VERSION 5.7 ;
BUSBITCHARS "[]" ;
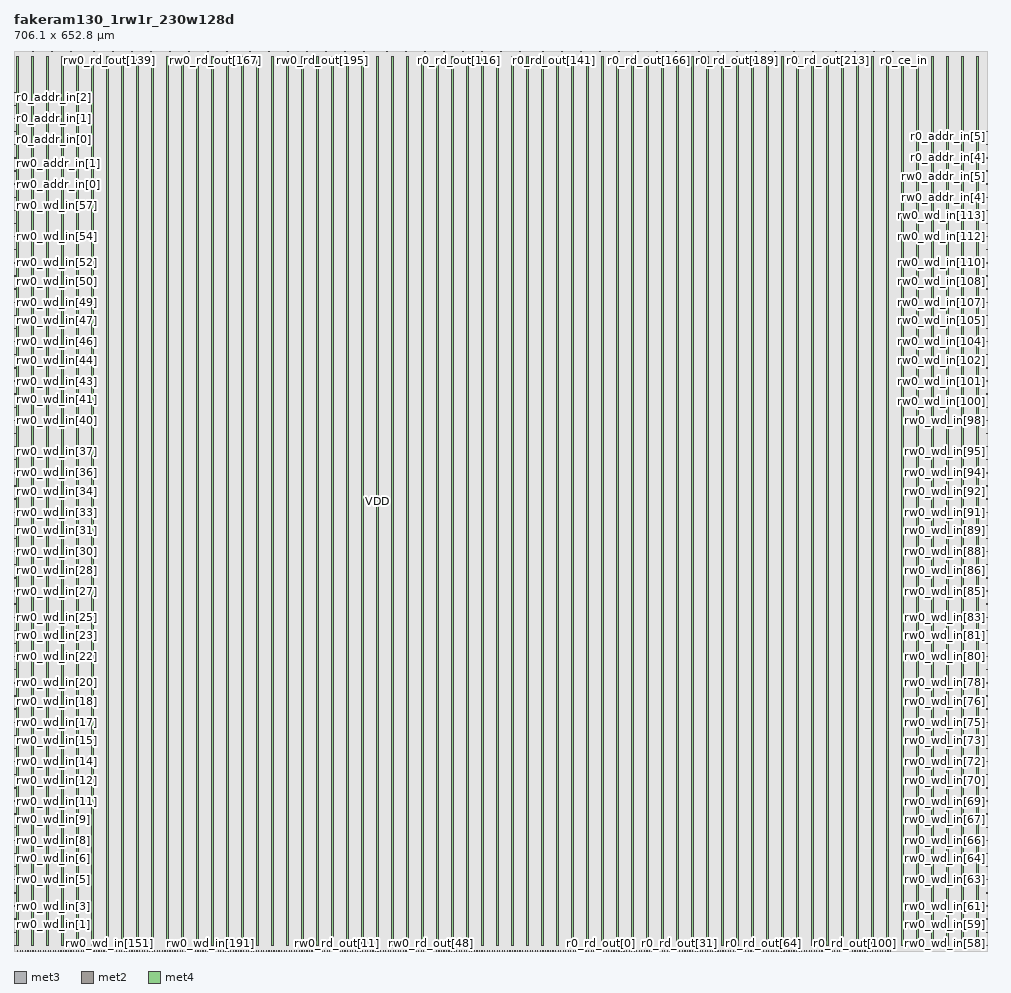
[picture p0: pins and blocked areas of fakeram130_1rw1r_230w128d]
MACRO fakeram130_1rw1r_230w128d
  FOREIGN fakeram130_1rw1r_230w128d 0 0 ;
  SYMMETRY X Y R90 ;
  SIZE 706.100 BY 652.800 ;
  CLASS BLOCK ;
  PIN rw0_wd_in[0]
    DIRECTION INPUT ;
    USE SIGNAL ;
    SHAPE ABUTMENT ;
    PORT
      LAYER met3 ;
      RECT 0.000 3.930 0.900 4.230 ;
    END
  END rw0_wd_in[0]
  PIN rw0_wd_in[1]
    DIRECTION INPUT ;
    USE SIGNAL ;
    SHAPE ABUTMENT ;
    PORT
      LAYER met3 ;
      RECT 0.000 13.450 0.900 13.750 ;
    END
  END rw0_wd_in[1]
  PIN rw0_wd_in[2]
    DIRECTION INPUT ;
    USE SIGNAL ;
    SHAPE ABUTMENT ;
    PORT
      LAYER met3 ;
      RECT 0.000 22.970 0.900 23.270 ;
    END
  END rw0_wd_in[2]
  PIN rw0_wd_in[3]
    DIRECTION INPUT ;
    USE SIGNAL ;
    SHAPE ABUTMENT ;
    PORT
      LAYER met3 ;
      RECT 0.000 32.490 0.900 32.790 ;
    END
  END rw0_wd_in[3]
  PIN rw0_wd_in[4]
    DIRECTION INPUT ;
    USE SIGNAL ;
    SHAPE ABUTMENT ;
    PORT
      LAYER met3 ;
      RECT 0.000 42.010 0.900 42.310 ;
    END
  END rw0_wd_in[4]
  PIN rw0_wd_in[5]
    DIRECTION INPUT ;
    USE SIGNAL ;
    SHAPE ABUTMENT ;
    PORT
      LAYER met3 ;
      RECT 0.000 51.530 0.900 51.830 ;
    END
  END rw0_wd_in[5]
  PIN rw0_wd_in[6]
    DIRECTION INPUT ;
    USE SIGNAL ;
    SHAPE ABUTMENT ;
    PORT
      LAYER met3 ;
      RECT 0.000 61.050 0.900 61.350 ;
    END
  END rw0_wd_in[6]
  PIN rw0_wd_in[7]
    DIRECTION INPUT ;
    USE SIGNAL ;
    SHAPE ABUTMENT ;
    PORT
      LAYER met3 ;
      RECT 0.000 70.570 0.900 70.870 ;
    END
  END rw0_wd_in[7]
  PIN rw0_wd_in[8]
    DIRECTION INPUT ;
    USE SIGNAL ;
    SHAPE ABUTMENT ;
    PORT
      LAYER met3 ;
      RECT 0.000 80.090 0.900 80.390 ;
    END
  END rw0_wd_in[8]
  PIN rw0_wd_in[9]
    DIRECTION INPUT ;
    USE SIGNAL ;
    SHAPE ABUTMENT ;
    PORT
      LAYER met3 ;
      RECT 0.000 89.610 0.900 89.910 ;
    END
  END rw0_wd_in[9]
  PIN rw0_wd_in[10]
    DIRECTION INPUT ;
    USE SIGNAL ;
    SHAPE ABUTMENT ;
    PORT
      LAYER met3 ;
      RECT 0.000 99.130 0.900 99.430 ;
    END
  END rw0_wd_in[10]
  PIN rw0_wd_in[11]
    DIRECTION INPUT ;
    USE SIGNAL ;
    SHAPE ABUTMENT ;
    PORT
      LAYER met3 ;
      RECT 0.000 108.650 0.900 108.950 ;
    END
  END rw0_wd_in[11]
  PIN rw0_wd_in[12]
    DIRECTION INPUT ;
    USE SIGNAL ;
    SHAPE ABUTMENT ;
    PORT
      LAYER met3 ;
      RECT 0.000 118.170 0.900 118.470 ;
    END
  END rw0_wd_in[12]
  PIN rw0_wd_in[13]
    DIRECTION INPUT ;
    USE SIGNAL ;
    SHAPE ABUTMENT ;
    PORT
      LAYER met3 ;
      RECT 0.000 127.690 0.900 127.990 ;
    END
  END rw0_wd_in[13]
  PIN rw0_wd_in[14]
    DIRECTION INPUT ;
    USE SIGNAL ;
    SHAPE ABUTMENT ;
    PORT
      LAYER met3 ;
      RECT 0.000 137.210 0.900 137.510 ;
    END
  END rw0_wd_in[14]
  PIN rw0_wd_in[15]
    DIRECTION INPUT ;
    USE SIGNAL ;
    SHAPE ABUTMENT ;
    PORT
      LAYER met3 ;
      RECT 0.000 146.730 0.900 147.030 ;
    END
  END rw0_wd_in[15]
  PIN rw0_wd_in[16]
    DIRECTION INPUT ;
    USE SIGNAL ;
    SHAPE ABUTMENT ;
    PORT
      LAYER met3 ;
      RECT 0.000 156.250 0.900 156.550 ;
    END
  END rw0_wd_in[16]
  PIN rw0_wd_in[17]
    DIRECTION INPUT ;
    USE SIGNAL ;
    SHAPE ABUTMENT ;
    PORT
      LAYER met3 ;
      RECT 0.000 165.770 0.900 166.070 ;
    END
  END rw0_wd_in[17]
  PIN rw0_wd_in[18]
    DIRECTION INPUT ;
    USE SIGNAL ;
    SHAPE ABUTMENT ;
    PORT
      LAYER met3 ;
      RECT 0.000 175.290 0.900 175.590 ;
    END
  END rw0_wd_in[18]
  PIN rw0_wd_in[19]
    DIRECTION INPUT ;
    USE SIGNAL ;
    SHAPE ABUTMENT ;
    PORT
      LAYER met3 ;
      RECT 0.000 184.810 0.900 185.110 ;
    END
  END rw0_wd_in[19]
  PIN rw0_wd_in[20]
    DIRECTION INPUT ;
    USE SIGNAL ;
    SHAPE ABUTMENT ;
    PORT
      LAYER met3 ;
      RECT 0.000 194.330 0.900 194.630 ;
    END
  END rw0_wd_in[20]
  PIN rw0_wd_in[21]
    DIRECTION INPUT ;
    USE SIGNAL ;
    SHAPE ABUTMENT ;
    PORT
      LAYER met3 ;
      RECT 0.000 203.850 0.900 204.150 ;
    END
  END rw0_wd_in[21]
  PIN rw0_wd_in[22]
    DIRECTION INPUT ;
    USE SIGNAL ;
    SHAPE ABUTMENT ;
    PORT
      LAYER met3 ;
      RECT 0.000 213.370 0.900 213.670 ;
    END
  END rw0_wd_in[22]
  PIN rw0_wd_in[23]
    DIRECTION INPUT ;
    USE SIGNAL ;
    SHAPE ABUTMENT ;
    PORT
      LAYER met3 ;
      RECT 0.000 222.890 0.900 223.190 ;
    END
  END rw0_wd_in[23]
  PIN rw0_wd_in[24]
    DIRECTION INPUT ;
    USE SIGNAL ;
    SHAPE ABUTMENT ;
    PORT
      LAYER met3 ;
      RECT 0.000 232.410 0.900 232.710 ;
    END
  END rw0_wd_in[24]
  PIN rw0_wd_in[25]
    DIRECTION INPUT ;
    USE SIGNAL ;
    SHAPE ABUTMENT ;
    PORT
      LAYER met3 ;
      RECT 0.000 241.930 0.900 242.230 ;
    END
  END rw0_wd_in[25]
  PIN rw0_wd_in[26]
    DIRECTION INPUT ;
    USE SIGNAL ;
    SHAPE ABUTMENT ;
    PORT
      LAYER met3 ;
      RECT 0.000 251.450 0.900 251.750 ;
    END
  END rw0_wd_in[26]
  PIN rw0_wd_in[27]
    DIRECTION INPUT ;
    USE SIGNAL ;
    SHAPE ABUTMENT ;
    PORT
      LAYER met3 ;
      RECT 0.000 260.970 0.900 261.270 ;
    END
  END rw0_wd_in[27]
  PIN rw0_wd_in[28]
    DIRECTION INPUT ;
    USE SIGNAL ;
    SHAPE ABUTMENT ;
    PORT
      LAYER met3 ;
      RECT 0.000 270.490 0.900 270.790 ;
    END
  END rw0_wd_in[28]
  PIN rw0_wd_in[29]
    DIRECTION INPUT ;
    USE SIGNAL ;
    SHAPE ABUTMENT ;
    PORT
      LAYER met3 ;
      RECT 0.000 280.010 0.900 280.310 ;
    END
  END rw0_wd_in[29]
  PIN rw0_wd_in[30]
    DIRECTION INPUT ;
    USE SIGNAL ;
    SHAPE ABUTMENT ;
    PORT
      LAYER met3 ;
      RECT 0.000 289.530 0.900 289.830 ;
    END
  END rw0_wd_in[30]
  PIN rw0_wd_in[31]
    DIRECTION INPUT ;
    USE SIGNAL ;
    SHAPE ABUTMENT ;
    PORT
      LAYER met3 ;
      RECT 0.000 299.050 0.900 299.350 ;
    END
  END rw0_wd_in[31]
  PIN rw0_wd_in[32]
    DIRECTION INPUT ;
    USE SIGNAL ;
    SHAPE ABUTMENT ;
    PORT
      LAYER met3 ;
      RECT 0.000 308.570 0.900 308.870 ;
    END
  END rw0_wd_in[32]
  PIN rw0_wd_in[33]
    DIRECTION INPUT ;
    USE SIGNAL ;
    SHAPE ABUTMENT ;
    PORT
      LAYER met3 ;
      RECT 0.000 318.090 0.900 318.390 ;
    END
  END rw0_wd_in[33]
  PIN rw0_wd_in[34]
    DIRECTION INPUT ;
    USE SIGNAL ;
    SHAPE ABUTMENT ;
    PORT
      LAYER met3 ;
      RECT 0.000 327.610 0.900 327.910 ;
    END
  END rw0_wd_in[34]
  PIN rw0_wd_in[35]
    DIRECTION INPUT ;
    USE SIGNAL ;
    SHAPE ABUTMENT ;
    PORT
      LAYER met3 ;
      RECT 0.000 337.130 0.900 337.430 ;
    END
  END rw0_wd_in[35]
  PIN rw0_wd_in[36]
    DIRECTION INPUT ;
    USE SIGNAL ;
    SHAPE ABUTMENT ;
    PORT
      LAYER met3 ;
      RECT 0.000 346.650 0.900 346.950 ;
    END
  END rw0_wd_in[36]
  PIN rw0_wd_in[37]
    DIRECTION INPUT ;
    USE SIGNAL ;
    SHAPE ABUTMENT ;
    PORT
      LAYER met3 ;
      RECT 0.000 356.170 0.900 356.470 ;
    END
  END rw0_wd_in[37]
  PIN rw0_wd_in[38]
    DIRECTION INPUT ;
    USE SIGNAL ;
    SHAPE ABUTMENT ;
    PORT
      LAYER met3 ;
      RECT 0.000 365.690 0.900 365.990 ;
    END
  END rw0_wd_in[38]
  PIN rw0_wd_in[39]
    DIRECTION INPUT ;
    USE SIGNAL ;
    SHAPE ABUTMENT ;
    PORT
      LAYER met3 ;
      RECT 0.000 375.210 0.900 375.510 ;
    END
  END rw0_wd_in[39]
  PIN rw0_wd_in[40]
    DIRECTION INPUT ;
    USE SIGNAL ;
    SHAPE ABUTMENT ;
    PORT
      LAYER met3 ;
      RECT 0.000 384.730 0.900 385.030 ;
    END
  END rw0_wd_in[40]
  PIN rw0_wd_in[41]
    DIRECTION INPUT ;
    USE SIGNAL ;
    SHAPE ABUTMENT ;
    PORT
      LAYER met3 ;
      RECT 0.000 394.250 0.900 394.550 ;
    END
  END rw0_wd_in[41]
  PIN rw0_wd_in[42]
    DIRECTION INPUT ;
    USE SIGNAL ;
    SHAPE ABUTMENT ;
    PORT
      LAYER met3 ;
      RECT 0.000 403.770 0.900 404.070 ;
    END
  END rw0_wd_in[42]
  PIN rw0_wd_in[43]
    DIRECTION INPUT ;
    USE SIGNAL ;
    SHAPE ABUTMENT ;
    PORT
      LAYER met3 ;
      RECT 0.000 413.290 0.900 413.590 ;
    END
  END rw0_wd_in[43]
  PIN rw0_wd_in[44]
    DIRECTION INPUT ;
    USE SIGNAL ;
    SHAPE ABUTMENT ;
    PORT
      LAYER met3 ;
      RECT 0.000 422.810 0.900 423.110 ;
    END
  END rw0_wd_in[44]
  PIN rw0_wd_in[45]
    DIRECTION INPUT ;
    USE SIGNAL ;
    SHAPE ABUTMENT ;
    PORT
      LAYER met3 ;
      RECT 0.000 432.330 0.900 432.630 ;
    END
  END rw0_wd_in[45]
  PIN rw0_wd_in[46]
    DIRECTION INPUT ;
    USE SIGNAL ;
    SHAPE ABUTMENT ;
    PORT
      LAYER met3 ;
      RECT 0.000 441.850 0.900 442.150 ;
    END
  END rw0_wd_in[46]
  PIN rw0_wd_in[47]
    DIRECTION INPUT ;
    USE SIGNAL ;
    SHAPE ABUTMENT ;
    PORT
      LAYER met3 ;
      RECT 0.000 451.370 0.900 451.670 ;
    END
  END rw0_wd_in[47]
  PIN rw0_wd_in[48]
    DIRECTION INPUT ;
    USE SIGNAL ;
    SHAPE ABUTMENT ;
    PORT
      LAYER met3 ;
      RECT 0.000 460.890 0.900 461.190 ;
    END
  END rw0_wd_in[48]
  PIN rw0_wd_in[49]
    DIRECTION INPUT ;
    USE SIGNAL ;
    SHAPE ABUTMENT ;
    PORT
      LAYER met3 ;
      RECT 0.000 470.410 0.900 470.710 ;
    END
  END rw0_wd_in[49]
  PIN rw0_wd_in[50]
    DIRECTION INPUT ;
    USE SIGNAL ;
    SHAPE ABUTMENT ;
    PORT
      LAYER met3 ;
      RECT 0.000 479.930 0.900 480.230 ;
    END
  END rw0_wd_in[50]
  PIN rw0_wd_in[51]
    DIRECTION INPUT ;
    USE SIGNAL ;
    SHAPE ABUTMENT ;
    PORT
      LAYER met3 ;
      RECT 0.000 489.450 0.900 489.750 ;
    END
  END rw0_wd_in[51]
  PIN rw0_wd_in[52]
    DIRECTION INPUT ;
    USE SIGNAL ;
    SHAPE ABUTMENT ;
    PORT
      LAYER met3 ;
      RECT 0.000 498.970 0.900 499.270 ;
    END
  END rw0_wd_in[52]
  PIN rw0_wd_in[53]
    DIRECTION INPUT ;
    USE SIGNAL ;
    SHAPE ABUTMENT ;
    PORT
      LAYER met3 ;
      RECT 0.000 508.490 0.900 508.790 ;
    END
  END rw0_wd_in[53]
  PIN rw0_wd_in[54]
    DIRECTION INPUT ;
    USE SIGNAL ;
    SHAPE ABUTMENT ;
    PORT
      LAYER met3 ;
      RECT 0.000 518.010 0.900 518.310 ;
    END
  END rw0_wd_in[54]
  PIN rw0_wd_in[55]
    DIRECTION INPUT ;
    USE SIGNAL ;
    SHAPE ABUTMENT ;
    PORT
      LAYER met3 ;
      RECT 0.000 527.530 0.900 527.830 ;
    END
  END rw0_wd_in[55]
  PIN rw0_wd_in[56]
    DIRECTION INPUT ;
    USE SIGNAL ;
    SHAPE ABUTMENT ;
    PORT
      LAYER met3 ;
      RECT 0.000 537.050 0.900 537.350 ;
    END
  END rw0_wd_in[56]
  PIN rw0_wd_in[57]
    DIRECTION INPUT ;
    USE SIGNAL ;
    SHAPE ABUTMENT ;
    PORT
      LAYER met3 ;
      RECT 0.000 546.570 0.900 546.870 ;
    END
  END rw0_wd_in[57]
  PIN rw0_wd_in[58]
    DIRECTION INPUT ;
    USE SIGNAL ;
    SHAPE ABUTMENT ;
    PORT
      LAYER met3 ;
      RECT 705.200 3.930 706.100 4.230 ;
    END
  END rw0_wd_in[58]
  PIN rw0_wd_in[59]
    DIRECTION INPUT ;
    USE SIGNAL ;
    SHAPE ABUTMENT ;
    PORT
      LAYER met3 ;
      RECT 705.200 13.450 706.100 13.750 ;
    END
  END rw0_wd_in[59]
  PIN rw0_wd_in[60]
    DIRECTION INPUT ;
    USE SIGNAL ;
    SHAPE ABUTMENT ;
    PORT
      LAYER met3 ;
      RECT 705.200 22.970 706.100 23.270 ;
    END
  END rw0_wd_in[60]
  PIN rw0_wd_in[61]
    DIRECTION INPUT ;
    USE SIGNAL ;
    SHAPE ABUTMENT ;
    PORT
      LAYER met3 ;
      RECT 705.200 32.490 706.100 32.790 ;
    END
  END rw0_wd_in[61]
  PIN rw0_wd_in[62]
    DIRECTION INPUT ;
    USE SIGNAL ;
    SHAPE ABUTMENT ;
    PORT
      LAYER met3 ;
      RECT 705.200 42.010 706.100 42.310 ;
    END
  END rw0_wd_in[62]
  PIN rw0_wd_in[63]
    DIRECTION INPUT ;
    USE SIGNAL ;
    SHAPE ABUTMENT ;
    PORT
      LAYER met3 ;
      RECT 705.200 51.530 706.100 51.830 ;
    END
  END rw0_wd_in[63]
  PIN rw0_wd_in[64]
    DIRECTION INPUT ;
    USE SIGNAL ;
    SHAPE ABUTMENT ;
    PORT
      LAYER met3 ;
      RECT 705.200 61.050 706.100 61.350 ;
    END
  END rw0_wd_in[64]
  PIN rw0_wd_in[65]
    DIRECTION INPUT ;
    USE SIGNAL ;
    SHAPE ABUTMENT ;
    PORT
      LAYER met3 ;
      RECT 705.200 70.570 706.100 70.870 ;
    END
  END rw0_wd_in[65]
  PIN rw0_wd_in[66]
    DIRECTION INPUT ;
    USE SIGNAL ;
    SHAPE ABUTMENT ;
    PORT
      LAYER met3 ;
      RECT 705.200 80.090 706.100 80.390 ;
    END
  END rw0_wd_in[66]
  PIN rw0_wd_in[67]
    DIRECTION INPUT ;
    USE SIGNAL ;
    SHAPE ABUTMENT ;
    PORT
      LAYER met3 ;
      RECT 705.200 89.610 706.100 89.910 ;
    END
  END rw0_wd_in[67]
  PIN rw0_wd_in[68]
    DIRECTION INPUT ;
    USE SIGNAL ;
    SHAPE ABUTMENT ;
    PORT
      LAYER met3 ;
      RECT 705.200 99.130 706.100 99.430 ;
    END
  END rw0_wd_in[68]
  PIN rw0_wd_in[69]
    DIRECTION INPUT ;
    USE SIGNAL ;
    SHAPE ABUTMENT ;
    PORT
      LAYER met3 ;
      RECT 705.200 108.650 706.100 108.950 ;
    END
  END rw0_wd_in[69]
  PIN rw0_wd_in[70]
    DIRECTION INPUT ;
    USE SIGNAL ;
    SHAPE ABUTMENT ;
    PORT
      LAYER met3 ;
      RECT 705.200 118.170 706.100 118.470 ;
    END
  END rw0_wd_in[70]
  PIN rw0_wd_in[71]
    DIRECTION INPUT ;
    USE SIGNAL ;
    SHAPE ABUTMENT ;
    PORT
      LAYER met3 ;
      RECT 705.200 127.690 706.100 127.990 ;
    END
  END rw0_wd_in[71]
  PIN rw0_wd_in[72]
    DIRECTION INPUT ;
    USE SIGNAL ;
    SHAPE ABUTMENT ;
    PORT
      LAYER met3 ;
      RECT 705.200 137.210 706.100 137.510 ;
    END
  END rw0_wd_in[72]
  PIN rw0_wd_in[73]
    DIRECTION INPUT ;
    USE SIGNAL ;
    SHAPE ABUTMENT ;
    PORT
      LAYER met3 ;
      RECT 705.200 146.730 706.100 147.030 ;
    END
  END rw0_wd_in[73]
  PIN rw0_wd_in[74]
    DIRECTION INPUT ;
    USE SIGNAL ;
    SHAPE ABUTMENT ;
    PORT
      LAYER met3 ;
      RECT 705.200 156.250 706.100 156.550 ;
    END
  END rw0_wd_in[74]
  PIN rw0_wd_in[75]
    DIRECTION INPUT ;
    USE SIGNAL ;
    SHAPE ABUTMENT ;
    PORT
      LAYER met3 ;
      RECT 705.200 165.770 706.100 166.070 ;
    END
  END rw0_wd_in[75]
  PIN rw0_wd_in[76]
    DIRECTION INPUT ;
    USE SIGNAL ;
    SHAPE ABUTMENT ;
    PORT
      LAYER met3 ;
      RECT 705.200 175.290 706.100 175.590 ;
    END
  END rw0_wd_in[76]
  PIN rw0_wd_in[77]
    DIRECTION INPUT ;
    USE SIGNAL ;
    SHAPE ABUTMENT ;
    PORT
      LAYER met3 ;
      RECT 705.200 184.810 706.100 185.110 ;
    END
  END rw0_wd_in[77]
  PIN rw0_wd_in[78]
    DIRECTION INPUT ;
    USE SIGNAL ;
    SHAPE ABUTMENT ;
    PORT
      LAYER met3 ;
      RECT 705.200 194.330 706.100 194.630 ;
    END
  END rw0_wd_in[78]
  PIN rw0_wd_in[79]
    DIRECTION INPUT ;
    USE SIGNAL ;
    SHAPE ABUTMENT ;
    PORT
      LAYER met3 ;
      RECT 705.200 203.850 706.100 204.150 ;
    END
  END rw0_wd_in[79]
  PIN rw0_wd_in[80]
    DIRECTION INPUT ;
    USE SIGNAL ;
    SHAPE ABUTMENT ;
    PORT
      LAYER met3 ;
      RECT 705.200 213.370 706.100 213.670 ;
    END
  END rw0_wd_in[80]
  PIN rw0_wd_in[81]
    DIRECTION INPUT ;
    USE SIGNAL ;
    SHAPE ABUTMENT ;
    PORT
      LAYER met3 ;
      RECT 705.200 222.890 706.100 223.190 ;
    END
  END rw0_wd_in[81]
  PIN rw0_wd_in[82]
    DIRECTION INPUT ;
    USE SIGNAL ;
    SHAPE ABUTMENT ;
    PORT
      LAYER met3 ;
      RECT 705.200 232.410 706.100 232.710 ;
    END
  END rw0_wd_in[82]
  PIN rw0_wd_in[83]
    DIRECTION INPUT ;
    USE SIGNAL ;
    SHAPE ABUTMENT ;
    PORT
      LAYER met3 ;
      RECT 705.200 241.930 706.100 242.230 ;
    END
  END rw0_wd_in[83]
  PIN rw0_wd_in[84]
    DIRECTION INPUT ;
    USE SIGNAL ;
    SHAPE ABUTMENT ;
    PORT
      LAYER met3 ;
      RECT 705.200 251.450 706.100 251.750 ;
    END
  END rw0_wd_in[84]
  PIN rw0_wd_in[85]
    DIRECTION INPUT ;
    USE SIGNAL ;
    SHAPE ABUTMENT ;
    PORT
      LAYER met3 ;
      RECT 705.200 260.970 706.100 261.270 ;
    END
  END rw0_wd_in[85]
  PIN rw0_wd_in[86]
    DIRECTION INPUT ;
    USE SIGNAL ;
    SHAPE ABUTMENT ;
    PORT
      LAYER met3 ;
      RECT 705.200 270.490 706.100 270.790 ;
    END
  END rw0_wd_in[86]
  PIN rw0_wd_in[87]
    DIRECTION INPUT ;
    USE SIGNAL ;
    SHAPE ABUTMENT ;
    PORT
      LAYER met3 ;
      RECT 705.200 280.010 706.100 280.310 ;
    END
  END rw0_wd_in[87]
  PIN rw0_wd_in[88]
    DIRECTION INPUT ;
    USE SIGNAL ;
    SHAPE ABUTMENT ;
    PORT
      LAYER met3 ;
      RECT 705.200 289.530 706.100 289.830 ;
    END
  END rw0_wd_in[88]
  PIN rw0_wd_in[89]
    DIRECTION INPUT ;
    USE SIGNAL ;
    SHAPE ABUTMENT ;
    PORT
      LAYER met3 ;
      RECT 705.200 299.050 706.100 299.350 ;
    END
  END rw0_wd_in[89]
  PIN rw0_wd_in[90]
    DIRECTION INPUT ;
    USE SIGNAL ;
    SHAPE ABUTMENT ;
    PORT
      LAYER met3 ;
      RECT 705.200 308.570 706.100 308.870 ;
    END
  END rw0_wd_in[90]
  PIN rw0_wd_in[91]
    DIRECTION INPUT ;
    USE SIGNAL ;
    SHAPE ABUTMENT ;
    PORT
      LAYER met3 ;
      RECT 705.200 318.090 706.100 318.390 ;
    END
  END rw0_wd_in[91]
  PIN rw0_wd_in[92]
    DIRECTION INPUT ;
    USE SIGNAL ;
    SHAPE ABUTMENT ;
    PORT
      LAYER met3 ;
      RECT 705.200 327.610 706.100 327.910 ;
    END
  END rw0_wd_in[92]
  PIN rw0_wd_in[93]
    DIRECTION INPUT ;
    USE SIGNAL ;
    SHAPE ABUTMENT ;
    PORT
      LAYER met3 ;
      RECT 705.200 337.130 706.100 337.430 ;
    END
  END rw0_wd_in[93]
  PIN rw0_wd_in[94]
    DIRECTION INPUT ;
    USE SIGNAL ;
    SHAPE ABUTMENT ;
    PORT
      LAYER met3 ;
      RECT 705.200 346.650 706.100 346.950 ;
    END
  END rw0_wd_in[94]
  PIN rw0_wd_in[95]
    DIRECTION INPUT ;
    USE SIGNAL ;
    SHAPE ABUTMENT ;
    PORT
      LAYER met3 ;
      RECT 705.200 356.170 706.100 356.470 ;
    END
  END rw0_wd_in[95]
  PIN rw0_wd_in[96]
    DIRECTION INPUT ;
    USE SIGNAL ;
    SHAPE ABUTMENT ;
    PORT
      LAYER met3 ;
      RECT 705.200 365.690 706.100 365.990 ;
    END
  END rw0_wd_in[96]
  PIN rw0_wd_in[97]
    DIRECTION INPUT ;
    USE SIGNAL ;
    SHAPE ABUTMENT ;
    PORT
      LAYER met3 ;
      RECT 705.200 375.210 706.100 375.510 ;
    END
  END rw0_wd_in[97]
  PIN rw0_wd_in[98]
    DIRECTION INPUT ;
    USE SIGNAL ;
    SHAPE ABUTMENT ;
    PORT
      LAYER met3 ;
      RECT 705.200 384.730 706.100 385.030 ;
    END
  END rw0_wd_in[98]
  PIN rw0_wd_in[99]
    DIRECTION INPUT ;
    USE SIGNAL ;
    SHAPE ABUTMENT ;
    PORT
      LAYER met3 ;
      RECT 705.200 394.250 706.100 394.550 ;
    END
  END rw0_wd_in[99]
  PIN rw0_wd_in[100]
    DIRECTION INPUT ;
    USE SIGNAL ;
    SHAPE ABUTMENT ;
    PORT
      LAYER met3 ;
      RECT 705.200 403.770 706.100 404.070 ;
    END
  END rw0_wd_in[100]
  PIN rw0_wd_in[101]
    DIRECTION INPUT ;
    USE SIGNAL ;
    SHAPE ABUTMENT ;
    PORT
      LAYER met3 ;
      RECT 705.200 413.290 706.100 413.590 ;
    END
  END rw0_wd_in[101]
  PIN rw0_wd_in[102]
    DIRECTION INPUT ;
    USE SIGNAL ;
    SHAPE ABUTMENT ;
    PORT
      LAYER met3 ;
      RECT 705.200 422.810 706.100 423.110 ;
    END
  END rw0_wd_in[102]
  PIN rw0_wd_in[103]
    DIRECTION INPUT ;
    USE SIGNAL ;
    SHAPE ABUTMENT ;
    PORT
      LAYER met3 ;
      RECT 705.200 432.330 706.100 432.630 ;
    END
  END rw0_wd_in[103]
  PIN rw0_wd_in[104]
    DIRECTION INPUT ;
    USE SIGNAL ;
    SHAPE ABUTMENT ;
    PORT
      LAYER met3 ;
      RECT 705.200 441.850 706.100 442.150 ;
    END
  END rw0_wd_in[104]
  PIN rw0_wd_in[105]
    DIRECTION INPUT ;
    USE SIGNAL ;
    SHAPE ABUTMENT ;
    PORT
      LAYER met3 ;
      RECT 705.200 451.370 706.100 451.670 ;
    END
  END rw0_wd_in[105]
  PIN rw0_wd_in[106]
    DIRECTION INPUT ;
    USE SIGNAL ;
    SHAPE ABUTMENT ;
    PORT
      LAYER met3 ;
      RECT 705.200 460.890 706.100 461.190 ;
    END
  END rw0_wd_in[106]
  PIN rw0_wd_in[107]
    DIRECTION INPUT ;
    USE SIGNAL ;
    SHAPE ABUTMENT ;
    PORT
      LAYER met3 ;
      RECT 705.200 470.410 706.100 470.710 ;
    END
  END rw0_wd_in[107]
  PIN rw0_wd_in[108]
    DIRECTION INPUT ;
    USE SIGNAL ;
    SHAPE ABUTMENT ;
    PORT
      LAYER met3 ;
      RECT 705.200 479.930 706.100 480.230 ;
    END
  END rw0_wd_in[108]
  PIN rw0_wd_in[109]
    DIRECTION INPUT ;
    USE SIGNAL ;
    SHAPE ABUTMENT ;
    PORT
      LAYER met3 ;
      RECT 705.200 489.450 706.100 489.750 ;
    END
  END rw0_wd_in[109]
  PIN rw0_wd_in[110]
    DIRECTION INPUT ;
    USE SIGNAL ;
    SHAPE ABUTMENT ;
    PORT
      LAYER met3 ;
      RECT 705.200 498.970 706.100 499.270 ;
    END
  END rw0_wd_in[110]
  PIN rw0_wd_in[111]
    DIRECTION INPUT ;
    USE SIGNAL ;
    SHAPE ABUTMENT ;
    PORT
      LAYER met3 ;
      RECT 705.200 508.490 706.100 508.790 ;
    END
  END rw0_wd_in[111]
  PIN rw0_wd_in[112]
    DIRECTION INPUT ;
    USE SIGNAL ;
    SHAPE ABUTMENT ;
    PORT
      LAYER met3 ;
      RECT 705.200 518.010 706.100 518.310 ;
    END
  END rw0_wd_in[112]
  PIN rw0_wd_in[113]
    DIRECTION INPUT ;
    USE SIGNAL ;
    SHAPE ABUTMENT ;
    PORT
      LAYER met3 ;
      RECT 705.200 527.530 706.100 527.830 ;
    END
  END rw0_wd_in[113]
  PIN rw0_wd_in[114]
    DIRECTION INPUT ;
    USE SIGNAL ;
    SHAPE ABUTMENT ;
    PORT
      LAYER met3 ;
      RECT 705.200 537.050 706.100 537.350 ;
    END
  END rw0_wd_in[114]
  PIN rw0_wd_in[115]
    DIRECTION OUTPUT ;
    USE SIGNAL ;
    SHAPE ABUTMENT ;
    PORT
      LAYER met2 ;
      RECT 2.690 0.000 2.830 0.420 ;
    END
  END rw0_wd_in[115]
  PIN rw0_wd_in[116]
    DIRECTION OUTPUT ;
    USE SIGNAL ;
    SHAPE ABUTMENT ;
    PORT
      LAYER met2 ;
      RECT 4.530 0.000 4.670 0.420 ;
    END
  END rw0_wd_in[116]
  PIN rw0_wd_in[117]
    DIRECTION OUTPUT ;
    USE SIGNAL ;
    SHAPE ABUTMENT ;
    PORT
      LAYER met2 ;
      RECT 6.370 0.000 6.510 0.420 ;
    END
  END rw0_wd_in[117]
  PIN rw0_wd_in[118]
    DIRECTION OUTPUT ;
    USE SIGNAL ;
    SHAPE ABUTMENT ;
    PORT
      LAYER met2 ;
      RECT 8.210 0.000 8.350 0.420 ;
    END
  END rw0_wd_in[118]
  PIN rw0_wd_in[119]
    DIRECTION OUTPUT ;
    USE SIGNAL ;
    SHAPE ABUTMENT ;
    PORT
      LAYER met2 ;
      RECT 10.050 0.000 10.190 0.420 ;
    END
  END rw0_wd_in[119]
  PIN rw0_wd_in[120]
    DIRECTION OUTPUT ;
    USE SIGNAL ;
    SHAPE ABUTMENT ;
    PORT
      LAYER met2 ;
      RECT 11.890 0.000 12.030 0.420 ;
    END
  END rw0_wd_in[120]
  PIN rw0_wd_in[121]
    DIRECTION OUTPUT ;
    USE SIGNAL ;
    SHAPE ABUTMENT ;
    PORT
      LAYER met2 ;
      RECT 13.730 0.000 13.870 0.420 ;
    END
  END rw0_wd_in[121]
  PIN rw0_wd_in[122]
    DIRECTION OUTPUT ;
    USE SIGNAL ;
    SHAPE ABUTMENT ;
    PORT
      LAYER met2 ;
      RECT 15.570 0.000 15.710 0.420 ;
    END
  END rw0_wd_in[122]
  PIN rw0_wd_in[123]
    DIRECTION OUTPUT ;
    USE SIGNAL ;
    SHAPE ABUTMENT ;
    PORT
      LAYER met2 ;
      RECT 17.410 0.000 17.550 0.420 ;
    END
  END rw0_wd_in[123]
  PIN rw0_wd_in[124]
    DIRECTION OUTPUT ;
    USE SIGNAL ;
    SHAPE ABUTMENT ;
    PORT
      LAYER met2 ;
      RECT 19.250 0.000 19.390 0.420 ;
    END
  END rw0_wd_in[124]
  PIN rw0_wd_in[125]
    DIRECTION OUTPUT ;
    USE SIGNAL ;
    SHAPE ABUTMENT ;
    PORT
      LAYER met2 ;
      RECT 21.090 0.000 21.230 0.420 ;
    END
  END rw0_wd_in[125]
  PIN rw0_wd_in[126]
    DIRECTION OUTPUT ;
    USE SIGNAL ;
    SHAPE ABUTMENT ;
    PORT
      LAYER met2 ;
      RECT 22.930 0.000 23.070 0.420 ;
    END
  END rw0_wd_in[126]
  PIN rw0_wd_in[127]
    DIRECTION OUTPUT ;
    USE SIGNAL ;
    SHAPE ABUTMENT ;
    PORT
      LAYER met2 ;
      RECT 24.770 0.000 24.910 0.420 ;
    END
  END rw0_wd_in[127]
  PIN rw0_wd_in[128]
    DIRECTION OUTPUT ;
    USE SIGNAL ;
    SHAPE ABUTMENT ;
    PORT
      LAYER met2 ;
      RECT 26.610 0.000 26.750 0.420 ;
    END
  END rw0_wd_in[128]
  PIN rw0_wd_in[129]
    DIRECTION OUTPUT ;
    USE SIGNAL ;
    SHAPE ABUTMENT ;
    PORT
      LAYER met2 ;
      RECT 28.450 0.000 28.590 0.420 ;
    END
  END rw0_wd_in[129]
  PIN rw0_wd_in[130]
    DIRECTION OUTPUT ;
    USE SIGNAL ;
    SHAPE ABUTMENT ;
    PORT
      LAYER met2 ;
      RECT 30.290 0.000 30.430 0.420 ;
    END
  END rw0_wd_in[130]
  PIN rw0_wd_in[131]
    DIRECTION OUTPUT ;
    USE SIGNAL ;
    SHAPE ABUTMENT ;
    PORT
      LAYER met2 ;
      RECT 32.130 0.000 32.270 0.420 ;
    END
  END rw0_wd_in[131]
  PIN rw0_wd_in[132]
    DIRECTION OUTPUT ;
    USE SIGNAL ;
    SHAPE ABUTMENT ;
    PORT
      LAYER met2 ;
      RECT 33.970 0.000 34.110 0.420 ;
    END
  END rw0_wd_in[132]
  PIN rw0_wd_in[133]
    DIRECTION OUTPUT ;
    USE SIGNAL ;
    SHAPE ABUTMENT ;
    PORT
      LAYER met2 ;
      RECT 35.810 0.000 35.950 0.420 ;
    END
  END rw0_wd_in[133]
  PIN rw0_wd_in[134]
    DIRECTION OUTPUT ;
    USE SIGNAL ;
    SHAPE ABUTMENT ;
    PORT
      LAYER met2 ;
      RECT 37.650 0.000 37.790 0.420 ;
    END
  END rw0_wd_in[134]
  PIN rw0_wd_in[135]
    DIRECTION OUTPUT ;
    USE SIGNAL ;
    SHAPE ABUTMENT ;
    PORT
      LAYER met2 ;
      RECT 39.490 0.000 39.630 0.420 ;
    END
  END rw0_wd_in[135]
  PIN rw0_wd_in[136]
    DIRECTION OUTPUT ;
    USE SIGNAL ;
    SHAPE ABUTMENT ;
    PORT
      LAYER met2 ;
      RECT 41.330 0.000 41.470 0.420 ;
    END
  END rw0_wd_in[136]
  PIN rw0_wd_in[137]
    DIRECTION OUTPUT ;
    USE SIGNAL ;
    SHAPE ABUTMENT ;
    PORT
      LAYER met2 ;
      RECT 43.170 0.000 43.310 0.420 ;
    END
  END rw0_wd_in[137]
  PIN rw0_wd_in[138]
    DIRECTION OUTPUT ;
    USE SIGNAL ;
    SHAPE ABUTMENT ;
    PORT
      LAYER met2 ;
      RECT 45.010 0.000 45.150 0.420 ;
    END
  END rw0_wd_in[138]
  PIN rw0_wd_in[139]
    DIRECTION OUTPUT ;
    USE SIGNAL ;
    SHAPE ABUTMENT ;
    PORT
      LAYER met2 ;
      RECT 46.850 0.000 46.990 0.420 ;
    END
  END rw0_wd_in[139]
  PIN rw0_wd_in[140]
    DIRECTION OUTPUT ;
    USE SIGNAL ;
    SHAPE ABUTMENT ;
    PORT
      LAYER met2 ;
      RECT 48.690 0.000 48.830 0.420 ;
    END
  END rw0_wd_in[140]
  PIN rw0_wd_in[141]
    DIRECTION OUTPUT ;
    USE SIGNAL ;
    SHAPE ABUTMENT ;
    PORT
      LAYER met2 ;
      RECT 50.530 0.000 50.670 0.420 ;
    END
  END rw0_wd_in[141]
  PIN rw0_wd_in[142]
    DIRECTION OUTPUT ;
    USE SIGNAL ;
    SHAPE ABUTMENT ;
    PORT
      LAYER met2 ;
      RECT 52.370 0.000 52.510 0.420 ;
    END
  END rw0_wd_in[142]
  PIN rw0_wd_in[143]
    DIRECTION OUTPUT ;
    USE SIGNAL ;
    SHAPE ABUTMENT ;
    PORT
      LAYER met2 ;
      RECT 54.210 0.000 54.350 0.420 ;
    END
  END rw0_wd_in[143]
  PIN rw0_wd_in[144]
    DIRECTION OUTPUT ;
    USE SIGNAL ;
    SHAPE ABUTMENT ;
    PORT
      LAYER met2 ;
      RECT 56.050 0.000 56.190 0.420 ;
    END
  END rw0_wd_in[144]
  PIN rw0_wd_in[145]
    DIRECTION OUTPUT ;
    USE SIGNAL ;
    SHAPE ABUTMENT ;
    PORT
      LAYER met2 ;
      RECT 57.890 0.000 58.030 0.420 ;
    END
  END rw0_wd_in[145]
  PIN rw0_wd_in[146]
    DIRECTION OUTPUT ;
    USE SIGNAL ;
    SHAPE ABUTMENT ;
    PORT
      LAYER met2 ;
      RECT 59.730 0.000 59.870 0.420 ;
    END
  END rw0_wd_in[146]
  PIN rw0_wd_in[147]
    DIRECTION OUTPUT ;
    USE SIGNAL ;
    SHAPE ABUTMENT ;
    PORT
      LAYER met2 ;
      RECT 61.570 0.000 61.710 0.420 ;
    END
  END rw0_wd_in[147]
  PIN rw0_wd_in[148]
    DIRECTION OUTPUT ;
    USE SIGNAL ;
    SHAPE ABUTMENT ;
    PORT
      LAYER met2 ;
      RECT 63.410 0.000 63.550 0.420 ;
    END
  END rw0_wd_in[148]
  PIN rw0_wd_in[149]
    DIRECTION OUTPUT ;
    USE SIGNAL ;
    SHAPE ABUTMENT ;
    PORT
      LAYER met2 ;
      RECT 65.250 0.000 65.390 0.420 ;
    END
  END rw0_wd_in[149]
  PIN rw0_wd_in[150]
    DIRECTION OUTPUT ;
    USE SIGNAL ;
    SHAPE ABUTMENT ;
    PORT
      LAYER met2 ;
      RECT 67.090 0.000 67.230 0.420 ;
    END
  END rw0_wd_in[150]
  PIN rw0_wd_in[151]
    DIRECTION OUTPUT ;
    USE SIGNAL ;
    SHAPE ABUTMENT ;
    PORT
      LAYER met2 ;
      RECT 68.930 0.000 69.070 0.420 ;
    END
  END rw0_wd_in[151]
  PIN rw0_wd_in[152]
    DIRECTION OUTPUT ;
    USE SIGNAL ;
    SHAPE ABUTMENT ;
    PORT
      LAYER met2 ;
      RECT 70.770 0.000 70.910 0.420 ;
    END
  END rw0_wd_in[152]
  PIN rw0_wd_in[153]
    DIRECTION OUTPUT ;
    USE SIGNAL ;
    SHAPE ABUTMENT ;
    PORT
      LAYER met2 ;
      RECT 72.610 0.000 72.750 0.420 ;
    END
  END rw0_wd_in[153]
  PIN rw0_wd_in[154]
    DIRECTION OUTPUT ;
    USE SIGNAL ;
    SHAPE ABUTMENT ;
    PORT
      LAYER met2 ;
      RECT 74.450 0.000 74.590 0.420 ;
    END
  END rw0_wd_in[154]
  PIN rw0_wd_in[155]
    DIRECTION OUTPUT ;
    USE SIGNAL ;
    SHAPE ABUTMENT ;
    PORT
      LAYER met2 ;
      RECT 76.290 0.000 76.430 0.420 ;
    END
  END rw0_wd_in[155]
  PIN rw0_wd_in[156]
    DIRECTION OUTPUT ;
    USE SIGNAL ;
    SHAPE ABUTMENT ;
    PORT
      LAYER met2 ;
      RECT 78.130 0.000 78.270 0.420 ;
    END
  END rw0_wd_in[156]
  PIN rw0_wd_in[157]
    DIRECTION OUTPUT ;
    USE SIGNAL ;
    SHAPE ABUTMENT ;
    PORT
      LAYER met2 ;
      RECT 79.970 0.000 80.110 0.420 ;
    END
  END rw0_wd_in[157]
  PIN rw0_wd_in[158]
    DIRECTION OUTPUT ;
    USE SIGNAL ;
    SHAPE ABUTMENT ;
    PORT
      LAYER met2 ;
      RECT 81.810 0.000 81.950 0.420 ;
    END
  END rw0_wd_in[158]
  PIN rw0_wd_in[159]
    DIRECTION OUTPUT ;
    USE SIGNAL ;
    SHAPE ABUTMENT ;
    PORT
      LAYER met2 ;
      RECT 83.650 0.000 83.790 0.420 ;
    END
  END rw0_wd_in[159]
  PIN rw0_wd_in[160]
    DIRECTION OUTPUT ;
    USE SIGNAL ;
    SHAPE ABUTMENT ;
    PORT
      LAYER met2 ;
      RECT 85.490 0.000 85.630 0.420 ;
    END
  END rw0_wd_in[160]
  PIN rw0_wd_in[161]
    DIRECTION OUTPUT ;
    USE SIGNAL ;
    SHAPE ABUTMENT ;
    PORT
      LAYER met2 ;
      RECT 87.330 0.000 87.470 0.420 ;
    END
  END rw0_wd_in[161]
  PIN rw0_wd_in[162]
    DIRECTION OUTPUT ;
    USE SIGNAL ;
    SHAPE ABUTMENT ;
    PORT
      LAYER met2 ;
      RECT 89.170 0.000 89.310 0.420 ;
    END
  END rw0_wd_in[162]
  PIN rw0_wd_in[163]
    DIRECTION OUTPUT ;
    USE SIGNAL ;
    SHAPE ABUTMENT ;
    PORT
      LAYER met2 ;
      RECT 91.010 0.000 91.150 0.420 ;
    END
  END rw0_wd_in[163]
  PIN rw0_wd_in[164]
    DIRECTION OUTPUT ;
    USE SIGNAL ;
    SHAPE ABUTMENT ;
    PORT
      LAYER met2 ;
      RECT 92.850 0.000 92.990 0.420 ;
    END
  END rw0_wd_in[164]
  PIN rw0_wd_in[165]
    DIRECTION OUTPUT ;
    USE SIGNAL ;
    SHAPE ABUTMENT ;
    PORT
      LAYER met2 ;
      RECT 94.690 0.000 94.830 0.420 ;
    END
  END rw0_wd_in[165]
  PIN rw0_wd_in[166]
    DIRECTION OUTPUT ;
    USE SIGNAL ;
    SHAPE ABUTMENT ;
    PORT
      LAYER met2 ;
      RECT 96.530 0.000 96.670 0.420 ;
    END
  END rw0_wd_in[166]
  PIN rw0_wd_in[167]
    DIRECTION OUTPUT ;
    USE SIGNAL ;
    SHAPE ABUTMENT ;
    PORT
      LAYER met2 ;
      RECT 98.370 0.000 98.510 0.420 ;
    END
  END rw0_wd_in[167]
  PIN rw0_wd_in[168]
    DIRECTION OUTPUT ;
    USE SIGNAL ;
    SHAPE ABUTMENT ;
    PORT
      LAYER met2 ;
      RECT 100.210 0.000 100.350 0.420 ;
    END
  END rw0_wd_in[168]
  PIN rw0_wd_in[169]
    DIRECTION OUTPUT ;
    USE SIGNAL ;
    SHAPE ABUTMENT ;
    PORT
      LAYER met2 ;
      RECT 102.050 0.000 102.190 0.420 ;
    END
  END rw0_wd_in[169]
  PIN rw0_wd_in[170]
    DIRECTION OUTPUT ;
    USE SIGNAL ;
    SHAPE ABUTMENT ;
    PORT
      LAYER met2 ;
      RECT 103.890 0.000 104.030 0.420 ;
    END
  END rw0_wd_in[170]
  PIN rw0_wd_in[171]
    DIRECTION OUTPUT ;
    USE SIGNAL ;
    SHAPE ABUTMENT ;
    PORT
      LAYER met2 ;
      RECT 105.730 0.000 105.870 0.420 ;
    END
  END rw0_wd_in[171]
  PIN rw0_wd_in[172]
    DIRECTION OUTPUT ;
    USE SIGNAL ;
    SHAPE ABUTMENT ;
    PORT
      LAYER met2 ;
      RECT 107.570 0.000 107.710 0.420 ;
    END
  END rw0_wd_in[172]
  PIN rw0_wd_in[173]
    DIRECTION OUTPUT ;
    USE SIGNAL ;
    SHAPE ABUTMENT ;
    PORT
      LAYER met2 ;
      RECT 109.410 0.000 109.550 0.420 ;
    END
  END rw0_wd_in[173]
  PIN rw0_wd_in[174]
    DIRECTION OUTPUT ;
    USE SIGNAL ;
    SHAPE ABUTMENT ;
    PORT
      LAYER met2 ;
      RECT 111.250 0.000 111.390 0.420 ;
    END
  END rw0_wd_in[174]
  PIN rw0_wd_in[175]
    DIRECTION OUTPUT ;
    USE SIGNAL ;
    SHAPE ABUTMENT ;
    PORT
      LAYER met2 ;
      RECT 113.090 0.000 113.230 0.420 ;
    END
  END rw0_wd_in[175]
  PIN rw0_wd_in[176]
    DIRECTION OUTPUT ;
    USE SIGNAL ;
    SHAPE ABUTMENT ;
    PORT
      LAYER met2 ;
      RECT 114.930 0.000 115.070 0.420 ;
    END
  END rw0_wd_in[176]
  PIN rw0_wd_in[177]
    DIRECTION OUTPUT ;
    USE SIGNAL ;
    SHAPE ABUTMENT ;
    PORT
      LAYER met2 ;
      RECT 116.770 0.000 116.910 0.420 ;
    END
  END rw0_wd_in[177]
  PIN rw0_wd_in[178]
    DIRECTION OUTPUT ;
    USE SIGNAL ;
    SHAPE ABUTMENT ;
    PORT
      LAYER met2 ;
      RECT 118.610 0.000 118.750 0.420 ;
    END
  END rw0_wd_in[178]
  PIN rw0_wd_in[179]
    DIRECTION OUTPUT ;
    USE SIGNAL ;
    SHAPE ABUTMENT ;
    PORT
      LAYER met2 ;
      RECT 120.450 0.000 120.590 0.420 ;
    END
  END rw0_wd_in[179]
  PIN rw0_wd_in[180]
    DIRECTION OUTPUT ;
    USE SIGNAL ;
    SHAPE ABUTMENT ;
    PORT
      LAYER met2 ;
      RECT 122.290 0.000 122.430 0.420 ;
    END
  END rw0_wd_in[180]
  PIN rw0_wd_in[181]
    DIRECTION OUTPUT ;
    USE SIGNAL ;
    SHAPE ABUTMENT ;
    PORT
      LAYER met2 ;
      RECT 124.130 0.000 124.270 0.420 ;
    END
  END rw0_wd_in[181]
  PIN rw0_wd_in[182]
    DIRECTION OUTPUT ;
    USE SIGNAL ;
    SHAPE ABUTMENT ;
    PORT
      LAYER met2 ;
      RECT 125.970 0.000 126.110 0.420 ;
    END
  END rw0_wd_in[182]
  PIN rw0_wd_in[183]
    DIRECTION OUTPUT ;
    USE SIGNAL ;
    SHAPE ABUTMENT ;
    PORT
      LAYER met2 ;
      RECT 127.810 0.000 127.950 0.420 ;
    END
  END rw0_wd_in[183]
  PIN rw0_wd_in[184]
    DIRECTION OUTPUT ;
    USE SIGNAL ;
    SHAPE ABUTMENT ;
    PORT
      LAYER met2 ;
      RECT 129.650 0.000 129.790 0.420 ;
    END
  END rw0_wd_in[184]
  PIN rw0_wd_in[185]
    DIRECTION OUTPUT ;
    USE SIGNAL ;
    SHAPE ABUTMENT ;
    PORT
      LAYER met2 ;
      RECT 131.490 0.000 131.630 0.420 ;
    END
  END rw0_wd_in[185]
  PIN rw0_wd_in[186]
    DIRECTION OUTPUT ;
    USE SIGNAL ;
    SHAPE ABUTMENT ;
    PORT
      LAYER met2 ;
      RECT 133.330 0.000 133.470 0.420 ;
    END
  END rw0_wd_in[186]
  PIN rw0_wd_in[187]
    DIRECTION OUTPUT ;
    USE SIGNAL ;
    SHAPE ABUTMENT ;
    PORT
      LAYER met2 ;
      RECT 135.170 0.000 135.310 0.420 ;
    END
  END rw0_wd_in[187]
  PIN rw0_wd_in[188]
    DIRECTION OUTPUT ;
    USE SIGNAL ;
    SHAPE ABUTMENT ;
    PORT
      LAYER met2 ;
      RECT 137.010 0.000 137.150 0.420 ;
    END
  END rw0_wd_in[188]
  PIN rw0_wd_in[189]
    DIRECTION OUTPUT ;
    USE SIGNAL ;
    SHAPE ABUTMENT ;
    PORT
      LAYER met2 ;
      RECT 138.850 0.000 138.990 0.420 ;
    END
  END rw0_wd_in[189]
  PIN rw0_wd_in[190]
    DIRECTION OUTPUT ;
    USE SIGNAL ;
    SHAPE ABUTMENT ;
    PORT
      LAYER met2 ;
      RECT 140.690 0.000 140.830 0.420 ;
    END
  END rw0_wd_in[190]
  PIN rw0_wd_in[191]
    DIRECTION OUTPUT ;
    USE SIGNAL ;
    SHAPE ABUTMENT ;
    PORT
      LAYER met2 ;
      RECT 142.530 0.000 142.670 0.420 ;
    END
  END rw0_wd_in[191]
  PIN rw0_wd_in[192]
    DIRECTION OUTPUT ;
    USE SIGNAL ;
    SHAPE ABUTMENT ;
    PORT
      LAYER met2 ;
      RECT 144.370 0.000 144.510 0.420 ;
    END
  END rw0_wd_in[192]
  PIN rw0_wd_in[193]
    DIRECTION OUTPUT ;
    USE SIGNAL ;
    SHAPE ABUTMENT ;
    PORT
      LAYER met2 ;
      RECT 146.210 0.000 146.350 0.420 ;
    END
  END rw0_wd_in[193]
  PIN rw0_wd_in[194]
    DIRECTION OUTPUT ;
    USE SIGNAL ;
    SHAPE ABUTMENT ;
    PORT
      LAYER met2 ;
      RECT 148.050 0.000 148.190 0.420 ;
    END
  END rw0_wd_in[194]
  PIN rw0_wd_in[195]
    DIRECTION OUTPUT ;
    USE SIGNAL ;
    SHAPE ABUTMENT ;
    PORT
      LAYER met2 ;
      RECT 149.890 0.000 150.030 0.420 ;
    END
  END rw0_wd_in[195]
  PIN rw0_wd_in[196]
    DIRECTION OUTPUT ;
    USE SIGNAL ;
    SHAPE ABUTMENT ;
    PORT
      LAYER met2 ;
      RECT 151.730 0.000 151.870 0.420 ;
    END
  END rw0_wd_in[196]
  PIN rw0_wd_in[197]
    DIRECTION OUTPUT ;
    USE SIGNAL ;
    SHAPE ABUTMENT ;
    PORT
      LAYER met2 ;
      RECT 153.570 0.000 153.710 0.420 ;
    END
  END rw0_wd_in[197]
  PIN rw0_wd_in[198]
    DIRECTION OUTPUT ;
    USE SIGNAL ;
    SHAPE ABUTMENT ;
    PORT
      LAYER met2 ;
      RECT 155.410 0.000 155.550 0.420 ;
    END
  END rw0_wd_in[198]
  PIN rw0_wd_in[199]
    DIRECTION OUTPUT ;
    USE SIGNAL ;
    SHAPE ABUTMENT ;
    PORT
      LAYER met2 ;
      RECT 157.250 0.000 157.390 0.420 ;
    END
  END rw0_wd_in[199]
  PIN rw0_wd_in[200]
    DIRECTION OUTPUT ;
    USE SIGNAL ;
    SHAPE ABUTMENT ;
    PORT
      LAYER met2 ;
      RECT 159.090 0.000 159.230 0.420 ;
    END
  END rw0_wd_in[200]
  PIN rw0_wd_in[201]
    DIRECTION OUTPUT ;
    USE SIGNAL ;
    SHAPE ABUTMENT ;
    PORT
      LAYER met2 ;
      RECT 160.930 0.000 161.070 0.420 ;
    END
  END rw0_wd_in[201]
  PIN rw0_wd_in[202]
    DIRECTION OUTPUT ;
    USE SIGNAL ;
    SHAPE ABUTMENT ;
    PORT
      LAYER met2 ;
      RECT 162.770 0.000 162.910 0.420 ;
    END
  END rw0_wd_in[202]
  PIN rw0_wd_in[203]
    DIRECTION OUTPUT ;
    USE SIGNAL ;
    SHAPE ABUTMENT ;
    PORT
      LAYER met2 ;
      RECT 164.610 0.000 164.750 0.420 ;
    END
  END rw0_wd_in[203]
  PIN rw0_wd_in[204]
    DIRECTION OUTPUT ;
    USE SIGNAL ;
    SHAPE ABUTMENT ;
    PORT
      LAYER met2 ;
      RECT 166.450 0.000 166.590 0.420 ;
    END
  END rw0_wd_in[204]
  PIN rw0_wd_in[205]
    DIRECTION OUTPUT ;
    USE SIGNAL ;
    SHAPE ABUTMENT ;
    PORT
      LAYER met2 ;
      RECT 168.290 0.000 168.430 0.420 ;
    END
  END rw0_wd_in[205]
  PIN rw0_wd_in[206]
    DIRECTION OUTPUT ;
    USE SIGNAL ;
    SHAPE ABUTMENT ;
    PORT
      LAYER met2 ;
      RECT 170.130 0.000 170.270 0.420 ;
    END
  END rw0_wd_in[206]
  PIN rw0_wd_in[207]
    DIRECTION OUTPUT ;
    USE SIGNAL ;
    SHAPE ABUTMENT ;
    PORT
      LAYER met2 ;
      RECT 171.970 0.000 172.110 0.420 ;
    END
  END rw0_wd_in[207]
  PIN rw0_wd_in[208]
    DIRECTION OUTPUT ;
    USE SIGNAL ;
    SHAPE ABUTMENT ;
    PORT
      LAYER met2 ;
      RECT 173.810 0.000 173.950 0.420 ;
    END
  END rw0_wd_in[208]
  PIN rw0_wd_in[209]
    DIRECTION OUTPUT ;
    USE SIGNAL ;
    SHAPE ABUTMENT ;
    PORT
      LAYER met2 ;
      RECT 175.650 0.000 175.790 0.420 ;
    END
  END rw0_wd_in[209]
  PIN rw0_wd_in[210]
    DIRECTION OUTPUT ;
    USE SIGNAL ;
    SHAPE ABUTMENT ;
    PORT
      LAYER met2 ;
      RECT 177.490 0.000 177.630 0.420 ;
    END
  END rw0_wd_in[210]
  PIN rw0_wd_in[211]
    DIRECTION OUTPUT ;
    USE SIGNAL ;
    SHAPE ABUTMENT ;
    PORT
      LAYER met2 ;
      RECT 179.330 0.000 179.470 0.420 ;
    END
  END rw0_wd_in[211]
  PIN rw0_wd_in[212]
    DIRECTION OUTPUT ;
    USE SIGNAL ;
    SHAPE ABUTMENT ;
    PORT
      LAYER met2 ;
      RECT 181.170 0.000 181.310 0.420 ;
    END
  END rw0_wd_in[212]
  PIN rw0_wd_in[213]
    DIRECTION OUTPUT ;
    USE SIGNAL ;
    SHAPE ABUTMENT ;
    PORT
      LAYER met2 ;
      RECT 183.010 0.000 183.150 0.420 ;
    END
  END rw0_wd_in[213]
  PIN rw0_wd_in[214]
    DIRECTION OUTPUT ;
    USE SIGNAL ;
    SHAPE ABUTMENT ;
    PORT
      LAYER met2 ;
      RECT 184.850 0.000 184.990 0.420 ;
    END
  END rw0_wd_in[214]
  PIN rw0_wd_in[215]
    DIRECTION OUTPUT ;
    USE SIGNAL ;
    SHAPE ABUTMENT ;
    PORT
      LAYER met2 ;
      RECT 186.690 0.000 186.830 0.420 ;
    END
  END rw0_wd_in[215]
  PIN rw0_wd_in[216]
    DIRECTION OUTPUT ;
    USE SIGNAL ;
    SHAPE ABUTMENT ;
    PORT
      LAYER met2 ;
      RECT 188.530 0.000 188.670 0.420 ;
    END
  END rw0_wd_in[216]
  PIN rw0_wd_in[217]
    DIRECTION OUTPUT ;
    USE SIGNAL ;
    SHAPE ABUTMENT ;
    PORT
      LAYER met2 ;
      RECT 190.370 0.000 190.510 0.420 ;
    END
  END rw0_wd_in[217]
  PIN rw0_wd_in[218]
    DIRECTION OUTPUT ;
    USE SIGNAL ;
    SHAPE ABUTMENT ;
    PORT
      LAYER met2 ;
      RECT 192.210 0.000 192.350 0.420 ;
    END
  END rw0_wd_in[218]
  PIN rw0_wd_in[219]
    DIRECTION OUTPUT ;
    USE SIGNAL ;
    SHAPE ABUTMENT ;
    PORT
      LAYER met2 ;
      RECT 194.050 0.000 194.190 0.420 ;
    END
  END rw0_wd_in[219]
  PIN rw0_wd_in[220]
    DIRECTION OUTPUT ;
    USE SIGNAL ;
    SHAPE ABUTMENT ;
    PORT
      LAYER met2 ;
      RECT 195.890 0.000 196.030 0.420 ;
    END
  END rw0_wd_in[220]
  PIN rw0_wd_in[221]
    DIRECTION OUTPUT ;
    USE SIGNAL ;
    SHAPE ABUTMENT ;
    PORT
      LAYER met2 ;
      RECT 197.730 0.000 197.870 0.420 ;
    END
  END rw0_wd_in[221]
  PIN rw0_wd_in[222]
    DIRECTION OUTPUT ;
    USE SIGNAL ;
    SHAPE ABUTMENT ;
    PORT
      LAYER met2 ;
      RECT 199.570 0.000 199.710 0.420 ;
    END
  END rw0_wd_in[222]
  PIN rw0_wd_in[223]
    DIRECTION OUTPUT ;
    USE SIGNAL ;
    SHAPE ABUTMENT ;
    PORT
      LAYER met2 ;
      RECT 201.410 0.000 201.550 0.420 ;
    END
  END rw0_wd_in[223]
  PIN rw0_wd_in[224]
    DIRECTION OUTPUT ;
    USE SIGNAL ;
    SHAPE ABUTMENT ;
    PORT
      LAYER met2 ;
      RECT 203.250 0.000 203.390 0.420 ;
    END
  END rw0_wd_in[224]
  PIN rw0_wd_in[225]
    DIRECTION OUTPUT ;
    USE SIGNAL ;
    SHAPE ABUTMENT ;
    PORT
      LAYER met2 ;
      RECT 205.090 0.000 205.230 0.420 ;
    END
  END rw0_wd_in[225]
  PIN rw0_wd_in[226]
    DIRECTION OUTPUT ;
    USE SIGNAL ;
    SHAPE ABUTMENT ;
    PORT
      LAYER met2 ;
      RECT 206.930 0.000 207.070 0.420 ;
    END
  END rw0_wd_in[226]
  PIN rw0_wd_in[227]
    DIRECTION OUTPUT ;
    USE SIGNAL ;
    SHAPE ABUTMENT ;
    PORT
      LAYER met2 ;
      RECT 208.770 0.000 208.910 0.420 ;
    END
  END rw0_wd_in[227]
  PIN rw0_wd_in[228]
    DIRECTION OUTPUT ;
    USE SIGNAL ;
    SHAPE ABUTMENT ;
    PORT
      LAYER met2 ;
      RECT 210.610 0.000 210.750 0.420 ;
    END
  END rw0_wd_in[228]
  PIN rw0_wd_in[229]
    DIRECTION OUTPUT ;
    USE SIGNAL ;
    SHAPE ABUTMENT ;
    PORT
      LAYER met2 ;
      RECT 212.450 0.000 212.590 0.420 ;
    END
  END rw0_wd_in[229]
  PIN rw0_rd_out[0]
    DIRECTION OUTPUT ;
    USE SIGNAL ;
    SHAPE ABUTMENT ;
    PORT
      LAYER met2 ;
      RECT 214.290 0.000 214.430 0.420 ;
    END
  END rw0_rd_out[0]
  PIN rw0_rd_out[1]
    DIRECTION OUTPUT ;
    USE SIGNAL ;
    SHAPE ABUTMENT ;
    PORT
      LAYER met2 ;
      RECT 216.130 0.000 216.270 0.420 ;
    END
  END rw0_rd_out[1]
  PIN rw0_rd_out[2]
    DIRECTION OUTPUT ;
    USE SIGNAL ;
    SHAPE ABUTMENT ;
    PORT
      LAYER met2 ;
      RECT 217.970 0.000 218.110 0.420 ;
    END
  END rw0_rd_out[2]
  PIN rw0_rd_out[3]
    DIRECTION OUTPUT ;
    USE SIGNAL ;
    SHAPE ABUTMENT ;
    PORT
      LAYER met2 ;
      RECT 219.810 0.000 219.950 0.420 ;
    END
  END rw0_rd_out[3]
  PIN rw0_rd_out[4]
    DIRECTION OUTPUT ;
    USE SIGNAL ;
    SHAPE ABUTMENT ;
    PORT
      LAYER met2 ;
      RECT 221.650 0.000 221.790 0.420 ;
    END
  END rw0_rd_out[4]
  PIN rw0_rd_out[5]
    DIRECTION OUTPUT ;
    USE SIGNAL ;
    SHAPE ABUTMENT ;
    PORT
      LAYER met2 ;
      RECT 223.490 0.000 223.630 0.420 ;
    END
  END rw0_rd_out[5]
  PIN rw0_rd_out[6]
    DIRECTION OUTPUT ;
    USE SIGNAL ;
    SHAPE ABUTMENT ;
    PORT
      LAYER met2 ;
      RECT 225.330 0.000 225.470 0.420 ;
    END
  END rw0_rd_out[6]
  PIN rw0_rd_out[7]
    DIRECTION OUTPUT ;
    USE SIGNAL ;
    SHAPE ABUTMENT ;
    PORT
      LAYER met2 ;
      RECT 227.170 0.000 227.310 0.420 ;
    END
  END rw0_rd_out[7]
  PIN rw0_rd_out[8]
    DIRECTION OUTPUT ;
    USE SIGNAL ;
    SHAPE ABUTMENT ;
    PORT
      LAYER met2 ;
      RECT 229.010 0.000 229.150 0.420 ;
    END
  END rw0_rd_out[8]
  PIN rw0_rd_out[9]
    DIRECTION OUTPUT ;
    USE SIGNAL ;
    SHAPE ABUTMENT ;
    PORT
      LAYER met2 ;
      RECT 230.850 0.000 230.990 0.420 ;
    END
  END rw0_rd_out[9]
  PIN rw0_rd_out[10]
    DIRECTION OUTPUT ;
    USE SIGNAL ;
    SHAPE ABUTMENT ;
    PORT
      LAYER met2 ;
      RECT 232.690 0.000 232.830 0.420 ;
    END
  END rw0_rd_out[10]
  PIN rw0_rd_out[11]
    DIRECTION OUTPUT ;
    USE SIGNAL ;
    SHAPE ABUTMENT ;
    PORT
      LAYER met2 ;
      RECT 234.530 0.000 234.670 0.420 ;
    END
  END rw0_rd_out[11]
  PIN rw0_rd_out[12]
    DIRECTION OUTPUT ;
    USE SIGNAL ;
    SHAPE ABUTMENT ;
    PORT
      LAYER met2 ;
      RECT 236.370 0.000 236.510 0.420 ;
    END
  END rw0_rd_out[12]
  PIN rw0_rd_out[13]
    DIRECTION OUTPUT ;
    USE SIGNAL ;
    SHAPE ABUTMENT ;
    PORT
      LAYER met2 ;
      RECT 238.210 0.000 238.350 0.420 ;
    END
  END rw0_rd_out[13]
  PIN rw0_rd_out[14]
    DIRECTION OUTPUT ;
    USE SIGNAL ;
    SHAPE ABUTMENT ;
    PORT
      LAYER met2 ;
      RECT 240.050 0.000 240.190 0.420 ;
    END
  END rw0_rd_out[14]
  PIN rw0_rd_out[15]
    DIRECTION OUTPUT ;
    USE SIGNAL ;
    SHAPE ABUTMENT ;
    PORT
      LAYER met2 ;
      RECT 241.890 0.000 242.030 0.420 ;
    END
  END rw0_rd_out[15]
  PIN rw0_rd_out[16]
    DIRECTION OUTPUT ;
    USE SIGNAL ;
    SHAPE ABUTMENT ;
    PORT
      LAYER met2 ;
      RECT 243.730 0.000 243.870 0.420 ;
    END
  END rw0_rd_out[16]
  PIN rw0_rd_out[17]
    DIRECTION OUTPUT ;
    USE SIGNAL ;
    SHAPE ABUTMENT ;
    PORT
      LAYER met2 ;
      RECT 245.570 0.000 245.710 0.420 ;
    END
  END rw0_rd_out[17]
  PIN rw0_rd_out[18]
    DIRECTION OUTPUT ;
    USE SIGNAL ;
    SHAPE ABUTMENT ;
    PORT
      LAYER met2 ;
      RECT 247.410 0.000 247.550 0.420 ;
    END
  END rw0_rd_out[18]
  PIN rw0_rd_out[19]
    DIRECTION OUTPUT ;
    USE SIGNAL ;
    SHAPE ABUTMENT ;
    PORT
      LAYER met2 ;
      RECT 249.250 0.000 249.390 0.420 ;
    END
  END rw0_rd_out[19]
  PIN rw0_rd_out[20]
    DIRECTION OUTPUT ;
    USE SIGNAL ;
    SHAPE ABUTMENT ;
    PORT
      LAYER met2 ;
      RECT 251.090 0.000 251.230 0.420 ;
    END
  END rw0_rd_out[20]
  PIN rw0_rd_out[21]
    DIRECTION OUTPUT ;
    USE SIGNAL ;
    SHAPE ABUTMENT ;
    PORT
      LAYER met2 ;
      RECT 252.930 0.000 253.070 0.420 ;
    END
  END rw0_rd_out[21]
  PIN rw0_rd_out[22]
    DIRECTION OUTPUT ;
    USE SIGNAL ;
    SHAPE ABUTMENT ;
    PORT
      LAYER met2 ;
      RECT 254.770 0.000 254.910 0.420 ;
    END
  END rw0_rd_out[22]
  PIN rw0_rd_out[23]
    DIRECTION OUTPUT ;
    USE SIGNAL ;
    SHAPE ABUTMENT ;
    PORT
      LAYER met2 ;
      RECT 256.610 0.000 256.750 0.420 ;
    END
  END rw0_rd_out[23]
  PIN rw0_rd_out[24]
    DIRECTION OUTPUT ;
    USE SIGNAL ;
    SHAPE ABUTMENT ;
    PORT
      LAYER met2 ;
      RECT 258.450 0.000 258.590 0.420 ;
    END
  END rw0_rd_out[24]
  PIN rw0_rd_out[25]
    DIRECTION OUTPUT ;
    USE SIGNAL ;
    SHAPE ABUTMENT ;
    PORT
      LAYER met2 ;
      RECT 260.290 0.000 260.430 0.420 ;
    END
  END rw0_rd_out[25]
  PIN rw0_rd_out[26]
    DIRECTION OUTPUT ;
    USE SIGNAL ;
    SHAPE ABUTMENT ;
    PORT
      LAYER met2 ;
      RECT 262.130 0.000 262.270 0.420 ;
    END
  END rw0_rd_out[26]
  PIN rw0_rd_out[27]
    DIRECTION OUTPUT ;
    USE SIGNAL ;
    SHAPE ABUTMENT ;
    PORT
      LAYER met2 ;
      RECT 263.970 0.000 264.110 0.420 ;
    END
  END rw0_rd_out[27]
  PIN rw0_rd_out[28]
    DIRECTION OUTPUT ;
    USE SIGNAL ;
    SHAPE ABUTMENT ;
    PORT
      LAYER met2 ;
      RECT 265.810 0.000 265.950 0.420 ;
    END
  END rw0_rd_out[28]
  PIN rw0_rd_out[29]
    DIRECTION OUTPUT ;
    USE SIGNAL ;
    SHAPE ABUTMENT ;
    PORT
      LAYER met2 ;
      RECT 267.650 0.000 267.790 0.420 ;
    END
  END rw0_rd_out[29]
  PIN rw0_rd_out[30]
    DIRECTION OUTPUT ;
    USE SIGNAL ;
    SHAPE ABUTMENT ;
    PORT
      LAYER met2 ;
      RECT 269.490 0.000 269.630 0.420 ;
    END
  END rw0_rd_out[30]
  PIN rw0_rd_out[31]
    DIRECTION OUTPUT ;
    USE SIGNAL ;
    SHAPE ABUTMENT ;
    PORT
      LAYER met2 ;
      RECT 271.330 0.000 271.470 0.420 ;
    END
  END rw0_rd_out[31]
  PIN rw0_rd_out[32]
    DIRECTION OUTPUT ;
    USE SIGNAL ;
    SHAPE ABUTMENT ;
    PORT
      LAYER met2 ;
      RECT 273.170 0.000 273.310 0.420 ;
    END
  END rw0_rd_out[32]
  PIN rw0_rd_out[33]
    DIRECTION OUTPUT ;
    USE SIGNAL ;
    SHAPE ABUTMENT ;
    PORT
      LAYER met2 ;
      RECT 275.010 0.000 275.150 0.420 ;
    END
  END rw0_rd_out[33]
  PIN rw0_rd_out[34]
    DIRECTION OUTPUT ;
    USE SIGNAL ;
    SHAPE ABUTMENT ;
    PORT
      LAYER met2 ;
      RECT 276.850 0.000 276.990 0.420 ;
    END
  END rw0_rd_out[34]
  PIN rw0_rd_out[35]
    DIRECTION OUTPUT ;
    USE SIGNAL ;
    SHAPE ABUTMENT ;
    PORT
      LAYER met2 ;
      RECT 278.690 0.000 278.830 0.420 ;
    END
  END rw0_rd_out[35]
  PIN rw0_rd_out[36]
    DIRECTION OUTPUT ;
    USE SIGNAL ;
    SHAPE ABUTMENT ;
    PORT
      LAYER met2 ;
      RECT 280.530 0.000 280.670 0.420 ;
    END
  END rw0_rd_out[36]
  PIN rw0_rd_out[37]
    DIRECTION OUTPUT ;
    USE SIGNAL ;
    SHAPE ABUTMENT ;
    PORT
      LAYER met2 ;
      RECT 282.370 0.000 282.510 0.420 ;
    END
  END rw0_rd_out[37]
  PIN rw0_rd_out[38]
    DIRECTION OUTPUT ;
    USE SIGNAL ;
    SHAPE ABUTMENT ;
    PORT
      LAYER met2 ;
      RECT 284.210 0.000 284.350 0.420 ;
    END
  END rw0_rd_out[38]
  PIN rw0_rd_out[39]
    DIRECTION OUTPUT ;
    USE SIGNAL ;
    SHAPE ABUTMENT ;
    PORT
      LAYER met2 ;
      RECT 286.050 0.000 286.190 0.420 ;
    END
  END rw0_rd_out[39]
  PIN rw0_rd_out[40]
    DIRECTION OUTPUT ;
    USE SIGNAL ;
    SHAPE ABUTMENT ;
    PORT
      LAYER met2 ;
      RECT 287.890 0.000 288.030 0.420 ;
    END
  END rw0_rd_out[40]
  PIN rw0_rd_out[41]
    DIRECTION OUTPUT ;
    USE SIGNAL ;
    SHAPE ABUTMENT ;
    PORT
      LAYER met2 ;
      RECT 289.730 0.000 289.870 0.420 ;
    END
  END rw0_rd_out[41]
  PIN rw0_rd_out[42]
    DIRECTION OUTPUT ;
    USE SIGNAL ;
    SHAPE ABUTMENT ;
    PORT
      LAYER met2 ;
      RECT 291.570 0.000 291.710 0.420 ;
    END
  END rw0_rd_out[42]
  PIN rw0_rd_out[43]
    DIRECTION OUTPUT ;
    USE SIGNAL ;
    SHAPE ABUTMENT ;
    PORT
      LAYER met2 ;
      RECT 293.410 0.000 293.550 0.420 ;
    END
  END rw0_rd_out[43]
  PIN rw0_rd_out[44]
    DIRECTION OUTPUT ;
    USE SIGNAL ;
    SHAPE ABUTMENT ;
    PORT
      LAYER met2 ;
      RECT 295.250 0.000 295.390 0.420 ;
    END
  END rw0_rd_out[44]
  PIN rw0_rd_out[45]
    DIRECTION OUTPUT ;
    USE SIGNAL ;
    SHAPE ABUTMENT ;
    PORT
      LAYER met2 ;
      RECT 297.090 0.000 297.230 0.420 ;
    END
  END rw0_rd_out[45]
  PIN rw0_rd_out[46]
    DIRECTION OUTPUT ;
    USE SIGNAL ;
    SHAPE ABUTMENT ;
    PORT
      LAYER met2 ;
      RECT 298.930 0.000 299.070 0.420 ;
    END
  END rw0_rd_out[46]
  PIN rw0_rd_out[47]
    DIRECTION OUTPUT ;
    USE SIGNAL ;
    SHAPE ABUTMENT ;
    PORT
      LAYER met2 ;
      RECT 300.770 0.000 300.910 0.420 ;
    END
  END rw0_rd_out[47]
  PIN rw0_rd_out[48]
    DIRECTION OUTPUT ;
    USE SIGNAL ;
    SHAPE ABUTMENT ;
    PORT
      LAYER met2 ;
      RECT 302.610 0.000 302.750 0.420 ;
    END
  END rw0_rd_out[48]
  PIN rw0_rd_out[49]
    DIRECTION OUTPUT ;
    USE SIGNAL ;
    SHAPE ABUTMENT ;
    PORT
      LAYER met2 ;
      RECT 304.450 0.000 304.590 0.420 ;
    END
  END rw0_rd_out[49]
  PIN rw0_rd_out[50]
    DIRECTION OUTPUT ;
    USE SIGNAL ;
    SHAPE ABUTMENT ;
    PORT
      LAYER met2 ;
      RECT 306.290 0.000 306.430 0.420 ;
    END
  END rw0_rd_out[50]
  PIN rw0_rd_out[51]
    DIRECTION OUTPUT ;
    USE SIGNAL ;
    SHAPE ABUTMENT ;
    PORT
      LAYER met2 ;
      RECT 308.130 0.000 308.270 0.420 ;
    END
  END rw0_rd_out[51]
  PIN rw0_rd_out[52]
    DIRECTION OUTPUT ;
    USE SIGNAL ;
    SHAPE ABUTMENT ;
    PORT
      LAYER met2 ;
      RECT 309.970 0.000 310.110 0.420 ;
    END
  END rw0_rd_out[52]
  PIN rw0_rd_out[53]
    DIRECTION OUTPUT ;
    USE SIGNAL ;
    SHAPE ABUTMENT ;
    PORT
      LAYER met2 ;
      RECT 311.810 0.000 311.950 0.420 ;
    END
  END rw0_rd_out[53]
  PIN rw0_rd_out[54]
    DIRECTION OUTPUT ;
    USE SIGNAL ;
    SHAPE ABUTMENT ;
    PORT
      LAYER met2 ;
      RECT 313.650 0.000 313.790 0.420 ;
    END
  END rw0_rd_out[54]
  PIN rw0_rd_out[55]
    DIRECTION OUTPUT ;
    USE SIGNAL ;
    SHAPE ABUTMENT ;
    PORT
      LAYER met2 ;
      RECT 315.490 0.000 315.630 0.420 ;
    END
  END rw0_rd_out[55]
  PIN rw0_rd_out[56]
    DIRECTION OUTPUT ;
    USE SIGNAL ;
    SHAPE ABUTMENT ;
    PORT
      LAYER met2 ;
      RECT 317.330 0.000 317.470 0.420 ;
    END
  END rw0_rd_out[56]
  PIN rw0_rd_out[57]
    DIRECTION OUTPUT ;
    USE SIGNAL ;
    SHAPE ABUTMENT ;
    PORT
      LAYER met2 ;
      RECT 319.170 0.000 319.310 0.420 ;
    END
  END rw0_rd_out[57]
  PIN rw0_rd_out[58]
    DIRECTION OUTPUT ;
    USE SIGNAL ;
    SHAPE ABUTMENT ;
    PORT
      LAYER met2 ;
      RECT 321.010 0.000 321.150 0.420 ;
    END
  END rw0_rd_out[58]
  PIN rw0_rd_out[59]
    DIRECTION OUTPUT ;
    USE SIGNAL ;
    SHAPE ABUTMENT ;
    PORT
      LAYER met2 ;
      RECT 322.850 0.000 322.990 0.420 ;
    END
  END rw0_rd_out[59]
  PIN rw0_rd_out[60]
    DIRECTION OUTPUT ;
    USE SIGNAL ;
    SHAPE ABUTMENT ;
    PORT
      LAYER met2 ;
      RECT 324.690 0.000 324.830 0.420 ;
    END
  END rw0_rd_out[60]
  PIN rw0_rd_out[61]
    DIRECTION OUTPUT ;
    USE SIGNAL ;
    SHAPE ABUTMENT ;
    PORT
      LAYER met2 ;
      RECT 326.530 0.000 326.670 0.420 ;
    END
  END rw0_rd_out[61]
  PIN rw0_rd_out[62]
    DIRECTION OUTPUT ;
    USE SIGNAL ;
    SHAPE ABUTMENT ;
    PORT
      LAYER met2 ;
      RECT 328.370 0.000 328.510 0.420 ;
    END
  END rw0_rd_out[62]
  PIN rw0_rd_out[63]
    DIRECTION OUTPUT ;
    USE SIGNAL ;
    SHAPE ABUTMENT ;
    PORT
      LAYER met2 ;
      RECT 330.210 0.000 330.350 0.420 ;
    END
  END rw0_rd_out[63]
  PIN rw0_rd_out[64]
    DIRECTION OUTPUT ;
    USE SIGNAL ;
    SHAPE ABUTMENT ;
    PORT
      LAYER met2 ;
      RECT 332.050 0.000 332.190 0.420 ;
    END
  END rw0_rd_out[64]
  PIN rw0_rd_out[65]
    DIRECTION OUTPUT ;
    USE SIGNAL ;
    SHAPE ABUTMENT ;
    PORT
      LAYER met2 ;
      RECT 333.890 0.000 334.030 0.420 ;
    END
  END rw0_rd_out[65]
  PIN rw0_rd_out[66]
    DIRECTION OUTPUT ;
    USE SIGNAL ;
    SHAPE ABUTMENT ;
    PORT
      LAYER met2 ;
      RECT 335.730 0.000 335.870 0.420 ;
    END
  END rw0_rd_out[66]
  PIN rw0_rd_out[67]
    DIRECTION OUTPUT ;
    USE SIGNAL ;
    SHAPE ABUTMENT ;
    PORT
      LAYER met2 ;
      RECT 337.570 0.000 337.710 0.420 ;
    END
  END rw0_rd_out[67]
  PIN rw0_rd_out[68]
    DIRECTION OUTPUT ;
    USE SIGNAL ;
    SHAPE ABUTMENT ;
    PORT
      LAYER met2 ;
      RECT 339.410 0.000 339.550 0.420 ;
    END
  END rw0_rd_out[68]
  PIN rw0_rd_out[69]
    DIRECTION OUTPUT ;
    USE SIGNAL ;
    SHAPE ABUTMENT ;
    PORT
      LAYER met2 ;
      RECT 341.250 0.000 341.390 0.420 ;
    END
  END rw0_rd_out[69]
  PIN rw0_rd_out[70]
    DIRECTION OUTPUT ;
    USE SIGNAL ;
    SHAPE ABUTMENT ;
    PORT
      LAYER met2 ;
      RECT 343.090 0.000 343.230 0.420 ;
    END
  END rw0_rd_out[70]
  PIN rw0_rd_out[71]
    DIRECTION OUTPUT ;
    USE SIGNAL ;
    SHAPE ABUTMENT ;
    PORT
      LAYER met2 ;
      RECT 344.930 0.000 345.070 0.420 ;
    END
  END rw0_rd_out[71]
  PIN rw0_rd_out[72]
    DIRECTION OUTPUT ;
    USE SIGNAL ;
    SHAPE ABUTMENT ;
    PORT
      LAYER met2 ;
      RECT 346.770 0.000 346.910 0.420 ;
    END
  END rw0_rd_out[72]
  PIN rw0_rd_out[73]
    DIRECTION OUTPUT ;
    USE SIGNAL ;
    SHAPE ABUTMENT ;
    PORT
      LAYER met2 ;
      RECT 348.610 0.000 348.750 0.420 ;
    END
  END rw0_rd_out[73]
  PIN rw0_rd_out[74]
    DIRECTION OUTPUT ;
    USE SIGNAL ;
    SHAPE ABUTMENT ;
    PORT
      LAYER met2 ;
      RECT 350.450 0.000 350.590 0.420 ;
    END
  END rw0_rd_out[74]
  PIN rw0_rd_out[75]
    DIRECTION OUTPUT ;
    USE SIGNAL ;
    SHAPE ABUTMENT ;
    PORT
      LAYER met2 ;
      RECT 352.290 0.000 352.430 0.420 ;
    END
  END rw0_rd_out[75]
  PIN rw0_rd_out[76]
    DIRECTION OUTPUT ;
    USE SIGNAL ;
    SHAPE ABUTMENT ;
    PORT
      LAYER met2 ;
      RECT 354.130 0.000 354.270 0.420 ;
    END
  END rw0_rd_out[76]
  PIN rw0_rd_out[77]
    DIRECTION OUTPUT ;
    USE SIGNAL ;
    SHAPE ABUTMENT ;
    PORT
      LAYER met2 ;
      RECT 355.970 0.000 356.110 0.420 ;
    END
  END rw0_rd_out[77]
  PIN rw0_rd_out[78]
    DIRECTION OUTPUT ;
    USE SIGNAL ;
    SHAPE ABUTMENT ;
    PORT
      LAYER met2 ;
      RECT 357.810 0.000 357.950 0.420 ;
    END
  END rw0_rd_out[78]
  PIN rw0_rd_out[79]
    DIRECTION OUTPUT ;
    USE SIGNAL ;
    SHAPE ABUTMENT ;
    PORT
      LAYER met2 ;
      RECT 359.650 0.000 359.790 0.420 ;
    END
  END rw0_rd_out[79]
  PIN rw0_rd_out[80]
    DIRECTION OUTPUT ;
    USE SIGNAL ;
    SHAPE ABUTMENT ;
    PORT
      LAYER met2 ;
      RECT 361.490 0.000 361.630 0.420 ;
    END
  END rw0_rd_out[80]
  PIN rw0_rd_out[81]
    DIRECTION OUTPUT ;
    USE SIGNAL ;
    SHAPE ABUTMENT ;
    PORT
      LAYER met2 ;
      RECT 363.330 0.000 363.470 0.420 ;
    END
  END rw0_rd_out[81]
  PIN rw0_rd_out[82]
    DIRECTION OUTPUT ;
    USE SIGNAL ;
    SHAPE ABUTMENT ;
    PORT
      LAYER met2 ;
      RECT 365.170 0.000 365.310 0.420 ;
    END
  END rw0_rd_out[82]
  PIN rw0_rd_out[83]
    DIRECTION OUTPUT ;
    USE SIGNAL ;
    SHAPE ABUTMENT ;
    PORT
      LAYER met2 ;
      RECT 367.010 0.000 367.150 0.420 ;
    END
  END rw0_rd_out[83]
  PIN rw0_rd_out[84]
    DIRECTION OUTPUT ;
    USE SIGNAL ;
    SHAPE ABUTMENT ;
    PORT
      LAYER met2 ;
      RECT 368.850 0.000 368.990 0.420 ;
    END
  END rw0_rd_out[84]
  PIN rw0_rd_out[85]
    DIRECTION OUTPUT ;
    USE SIGNAL ;
    SHAPE ABUTMENT ;
    PORT
      LAYER met2 ;
      RECT 370.690 0.000 370.830 0.420 ;
    END
  END rw0_rd_out[85]
  PIN rw0_rd_out[86]
    DIRECTION OUTPUT ;
    USE SIGNAL ;
    SHAPE ABUTMENT ;
    PORT
      LAYER met2 ;
      RECT 372.530 0.000 372.670 0.420 ;
    END
  END rw0_rd_out[86]
  PIN rw0_rd_out[87]
    DIRECTION OUTPUT ;
    USE SIGNAL ;
    SHAPE ABUTMENT ;
    PORT
      LAYER met2 ;
      RECT 374.370 0.000 374.510 0.420 ;
    END
  END rw0_rd_out[87]
  PIN rw0_rd_out[88]
    DIRECTION OUTPUT ;
    USE SIGNAL ;
    SHAPE ABUTMENT ;
    PORT
      LAYER met2 ;
      RECT 376.210 0.000 376.350 0.420 ;
    END
  END rw0_rd_out[88]
  PIN rw0_rd_out[89]
    DIRECTION OUTPUT ;
    USE SIGNAL ;
    SHAPE ABUTMENT ;
    PORT
      LAYER met2 ;
      RECT 378.050 0.000 378.190 0.420 ;
    END
  END rw0_rd_out[89]
  PIN rw0_rd_out[90]
    DIRECTION OUTPUT ;
    USE SIGNAL ;
    SHAPE ABUTMENT ;
    PORT
      LAYER met2 ;
      RECT 379.890 0.000 380.030 0.420 ;
    END
  END rw0_rd_out[90]
  PIN rw0_rd_out[91]
    DIRECTION OUTPUT ;
    USE SIGNAL ;
    SHAPE ABUTMENT ;
    PORT
      LAYER met2 ;
      RECT 381.730 0.000 381.870 0.420 ;
    END
  END rw0_rd_out[91]
  PIN rw0_rd_out[92]
    DIRECTION OUTPUT ;
    USE SIGNAL ;
    SHAPE ABUTMENT ;
    PORT
      LAYER met2 ;
      RECT 383.570 0.000 383.710 0.420 ;
    END
  END rw0_rd_out[92]
  PIN rw0_rd_out[93]
    DIRECTION OUTPUT ;
    USE SIGNAL ;
    SHAPE ABUTMENT ;
    PORT
      LAYER met2 ;
      RECT 385.410 0.000 385.550 0.420 ;
    END
  END rw0_rd_out[93]
  PIN rw0_rd_out[94]
    DIRECTION OUTPUT ;
    USE SIGNAL ;
    SHAPE ABUTMENT ;
    PORT
      LAYER met2 ;
      RECT 387.250 0.000 387.390 0.420 ;
    END
  END rw0_rd_out[94]
  PIN rw0_rd_out[95]
    DIRECTION OUTPUT ;
    USE SIGNAL ;
    SHAPE ABUTMENT ;
    PORT
      LAYER met2 ;
      RECT 389.090 0.000 389.230 0.420 ;
    END
  END rw0_rd_out[95]
  PIN rw0_rd_out[96]
    DIRECTION OUTPUT ;
    USE SIGNAL ;
    SHAPE ABUTMENT ;
    PORT
      LAYER met2 ;
      RECT 390.930 0.000 391.070 0.420 ;
    END
  END rw0_rd_out[96]
  PIN rw0_rd_out[97]
    DIRECTION OUTPUT ;
    USE SIGNAL ;
    SHAPE ABUTMENT ;
    PORT
      LAYER met2 ;
      RECT 392.770 0.000 392.910 0.420 ;
    END
  END rw0_rd_out[97]
  PIN rw0_rd_out[98]
    DIRECTION OUTPUT ;
    USE SIGNAL ;
    SHAPE ABUTMENT ;
    PORT
      LAYER met2 ;
      RECT 394.610 0.000 394.750 0.420 ;
    END
  END rw0_rd_out[98]
  PIN rw0_rd_out[99]
    DIRECTION OUTPUT ;
    USE SIGNAL ;
    SHAPE ABUTMENT ;
    PORT
      LAYER met2 ;
      RECT 396.450 0.000 396.590 0.420 ;
    END
  END rw0_rd_out[99]
  PIN rw0_rd_out[100]
    DIRECTION OUTPUT ;
    USE SIGNAL ;
    SHAPE ABUTMENT ;
    PORT
      LAYER met2 ;
      RECT 398.290 0.000 398.430 0.420 ;
    END
  END rw0_rd_out[100]
  PIN rw0_rd_out[101]
    DIRECTION OUTPUT ;
    USE SIGNAL ;
    SHAPE ABUTMENT ;
    PORT
      LAYER met2 ;
      RECT 400.130 0.000 400.270 0.420 ;
    END
  END rw0_rd_out[101]
  PIN rw0_rd_out[102]
    DIRECTION OUTPUT ;
    USE SIGNAL ;
    SHAPE ABUTMENT ;
    PORT
      LAYER met2 ;
      RECT 401.970 0.000 402.110 0.420 ;
    END
  END rw0_rd_out[102]
  PIN rw0_rd_out[103]
    DIRECTION OUTPUT ;
    USE SIGNAL ;
    SHAPE ABUTMENT ;
    PORT
      LAYER met2 ;
      RECT 403.810 0.000 403.950 0.420 ;
    END
  END rw0_rd_out[103]
  PIN rw0_rd_out[104]
    DIRECTION OUTPUT ;
    USE SIGNAL ;
    SHAPE ABUTMENT ;
    PORT
      LAYER met2 ;
      RECT 405.650 0.000 405.790 0.420 ;
    END
  END rw0_rd_out[104]
  PIN rw0_rd_out[105]
    DIRECTION OUTPUT ;
    USE SIGNAL ;
    SHAPE ABUTMENT ;
    PORT
      LAYER met2 ;
      RECT 407.490 0.000 407.630 0.420 ;
    END
  END rw0_rd_out[105]
  PIN rw0_rd_out[106]
    DIRECTION OUTPUT ;
    USE SIGNAL ;
    SHAPE ABUTMENT ;
    PORT
      LAYER met2 ;
      RECT 409.330 0.000 409.470 0.420 ;
    END
  END rw0_rd_out[106]
  PIN rw0_rd_out[107]
    DIRECTION OUTPUT ;
    USE SIGNAL ;
    SHAPE ABUTMENT ;
    PORT
      LAYER met2 ;
      RECT 411.170 0.000 411.310 0.420 ;
    END
  END rw0_rd_out[107]
  PIN rw0_rd_out[108]
    DIRECTION OUTPUT ;
    USE SIGNAL ;
    SHAPE ABUTMENT ;
    PORT
      LAYER met2 ;
      RECT 413.010 0.000 413.150 0.420 ;
    END
  END rw0_rd_out[108]
  PIN rw0_rd_out[109]
    DIRECTION OUTPUT ;
    USE SIGNAL ;
    SHAPE ABUTMENT ;
    PORT
      LAYER met2 ;
      RECT 414.850 0.000 414.990 0.420 ;
    END
  END rw0_rd_out[109]
  PIN rw0_rd_out[110]
    DIRECTION OUTPUT ;
    USE SIGNAL ;
    SHAPE ABUTMENT ;
    PORT
      LAYER met2 ;
      RECT 416.690 0.000 416.830 0.420 ;
    END
  END rw0_rd_out[110]
  PIN rw0_rd_out[111]
    DIRECTION OUTPUT ;
    USE SIGNAL ;
    SHAPE ABUTMENT ;
    PORT
      LAYER met2 ;
      RECT 418.530 0.000 418.670 0.420 ;
    END
  END rw0_rd_out[111]
  PIN rw0_rd_out[112]
    DIRECTION OUTPUT ;
    USE SIGNAL ;
    SHAPE ABUTMENT ;
    PORT
      LAYER met2 ;
      RECT 420.370 0.000 420.510 0.420 ;
    END
  END rw0_rd_out[112]
  PIN rw0_rd_out[113]
    DIRECTION OUTPUT ;
    USE SIGNAL ;
    SHAPE ABUTMENT ;
    PORT
      LAYER met2 ;
      RECT 422.210 0.000 422.350 0.420 ;
    END
  END rw0_rd_out[113]
  PIN rw0_rd_out[114]
    DIRECTION OUTPUT ;
    USE SIGNAL ;
    SHAPE ABUTMENT ;
    PORT
      LAYER met2 ;
      RECT 424.050 0.000 424.190 0.420 ;
    END
  END rw0_rd_out[114]
  PIN rw0_rd_out[115]
    DIRECTION OUTPUT ;
    USE SIGNAL ;
    SHAPE ABUTMENT ;
    PORT
      LAYER met2 ;
      RECT 2.690 652.380 2.830 652.800 ;
    END
  END rw0_rd_out[115]
  PIN rw0_rd_out[116]
    DIRECTION OUTPUT ;
    USE SIGNAL ;
    SHAPE ABUTMENT ;
    PORT
      LAYER met2 ;
      RECT 5.450 652.380 5.590 652.800 ;
    END
  END rw0_rd_out[116]
  PIN rw0_rd_out[117]
    DIRECTION OUTPUT ;
    USE SIGNAL ;
    SHAPE ABUTMENT ;
    PORT
      LAYER met2 ;
      RECT 8.210 652.380 8.350 652.800 ;
    END
  END rw0_rd_out[117]
  PIN rw0_rd_out[118]
    DIRECTION OUTPUT ;
    USE SIGNAL ;
    SHAPE ABUTMENT ;
    PORT
      LAYER met2 ;
      RECT 10.970 652.380 11.110 652.800 ;
    END
  END rw0_rd_out[118]
  PIN rw0_rd_out[119]
    DIRECTION OUTPUT ;
    USE SIGNAL ;
    SHAPE ABUTMENT ;
    PORT
      LAYER met2 ;
      RECT 13.730 652.380 13.870 652.800 ;
    END
  END rw0_rd_out[119]
  PIN rw0_rd_out[120]
    DIRECTION OUTPUT ;
    USE SIGNAL ;
    SHAPE ABUTMENT ;
    PORT
      LAYER met2 ;
      RECT 16.490 652.380 16.630 652.800 ;
    END
  END rw0_rd_out[120]
  PIN rw0_rd_out[121]
    DIRECTION OUTPUT ;
    USE SIGNAL ;
    SHAPE ABUTMENT ;
    PORT
      LAYER met2 ;
      RECT 19.250 652.380 19.390 652.800 ;
    END
  END rw0_rd_out[121]
  PIN rw0_rd_out[122]
    DIRECTION OUTPUT ;
    USE SIGNAL ;
    SHAPE ABUTMENT ;
    PORT
      LAYER met2 ;
      RECT 22.010 652.380 22.150 652.800 ;
    END
  END rw0_rd_out[122]
  PIN rw0_rd_out[123]
    DIRECTION OUTPUT ;
    USE SIGNAL ;
    SHAPE ABUTMENT ;
    PORT
      LAYER met2 ;
      RECT 24.770 652.380 24.910 652.800 ;
    END
  END rw0_rd_out[123]
  PIN rw0_rd_out[124]
    DIRECTION OUTPUT ;
    USE SIGNAL ;
    SHAPE ABUTMENT ;
    PORT
      LAYER met2 ;
      RECT 27.530 652.380 27.670 652.800 ;
    END
  END rw0_rd_out[124]
  PIN rw0_rd_out[125]
    DIRECTION OUTPUT ;
    USE SIGNAL ;
    SHAPE ABUTMENT ;
    PORT
      LAYER met2 ;
      RECT 30.290 652.380 30.430 652.800 ;
    END
  END rw0_rd_out[125]
  PIN rw0_rd_out[126]
    DIRECTION OUTPUT ;
    USE SIGNAL ;
    SHAPE ABUTMENT ;
    PORT
      LAYER met2 ;
      RECT 33.050 652.380 33.190 652.800 ;
    END
  END rw0_rd_out[126]
  PIN rw0_rd_out[127]
    DIRECTION OUTPUT ;
    USE SIGNAL ;
    SHAPE ABUTMENT ;
    PORT
      LAYER met2 ;
      RECT 35.810 652.380 35.950 652.800 ;
    END
  END rw0_rd_out[127]
  PIN rw0_rd_out[128]
    DIRECTION OUTPUT ;
    USE SIGNAL ;
    SHAPE ABUTMENT ;
    PORT
      LAYER met2 ;
      RECT 38.570 652.380 38.710 652.800 ;
    END
  END rw0_rd_out[128]
  PIN rw0_rd_out[129]
    DIRECTION OUTPUT ;
    USE SIGNAL ;
    SHAPE ABUTMENT ;
    PORT
      LAYER met2 ;
      RECT 41.330 652.380 41.470 652.800 ;
    END
  END rw0_rd_out[129]
  PIN rw0_rd_out[130]
    DIRECTION OUTPUT ;
    USE SIGNAL ;
    SHAPE ABUTMENT ;
    PORT
      LAYER met2 ;
      RECT 44.090 652.380 44.230 652.800 ;
    END
  END rw0_rd_out[130]
  PIN rw0_rd_out[131]
    DIRECTION OUTPUT ;
    USE SIGNAL ;
    SHAPE ABUTMENT ;
    PORT
      LAYER met2 ;
      RECT 46.850 652.380 46.990 652.800 ;
    END
  END rw0_rd_out[131]
  PIN rw0_rd_out[132]
    DIRECTION OUTPUT ;
    USE SIGNAL ;
    SHAPE ABUTMENT ;
    PORT
      LAYER met2 ;
      RECT 49.610 652.380 49.750 652.800 ;
    END
  END rw0_rd_out[132]
  PIN rw0_rd_out[133]
    DIRECTION OUTPUT ;
    USE SIGNAL ;
    SHAPE ABUTMENT ;
    PORT
      LAYER met2 ;
      RECT 52.370 652.380 52.510 652.800 ;
    END
  END rw0_rd_out[133]
  PIN rw0_rd_out[134]
    DIRECTION OUTPUT ;
    USE SIGNAL ;
    SHAPE ABUTMENT ;
    PORT
      LAYER met2 ;
      RECT 55.130 652.380 55.270 652.800 ;
    END
  END rw0_rd_out[134]
  PIN rw0_rd_out[135]
    DIRECTION OUTPUT ;
    USE SIGNAL ;
    SHAPE ABUTMENT ;
    PORT
      LAYER met2 ;
      RECT 57.890 652.380 58.030 652.800 ;
    END
  END rw0_rd_out[135]
  PIN rw0_rd_out[136]
    DIRECTION OUTPUT ;
    USE SIGNAL ;
    SHAPE ABUTMENT ;
    PORT
      LAYER met2 ;
      RECT 60.650 652.380 60.790 652.800 ;
    END
  END rw0_rd_out[136]
  PIN rw0_rd_out[137]
    DIRECTION OUTPUT ;
    USE SIGNAL ;
    SHAPE ABUTMENT ;
    PORT
      LAYER met2 ;
      RECT 63.410 652.380 63.550 652.800 ;
    END
  END rw0_rd_out[137]
  PIN rw0_rd_out[138]
    DIRECTION OUTPUT ;
    USE SIGNAL ;
    SHAPE ABUTMENT ;
    PORT
      LAYER met2 ;
      RECT 66.170 652.380 66.310 652.800 ;
    END
  END rw0_rd_out[138]
  PIN rw0_rd_out[139]
    DIRECTION OUTPUT ;
    USE SIGNAL ;
    SHAPE ABUTMENT ;
    PORT
      LAYER met2 ;
      RECT 68.930 652.380 69.070 652.800 ;
    END
  END rw0_rd_out[139]
  PIN rw0_rd_out[140]
    DIRECTION OUTPUT ;
    USE SIGNAL ;
    SHAPE ABUTMENT ;
    PORT
      LAYER met2 ;
      RECT 71.690 652.380 71.830 652.800 ;
    END
  END rw0_rd_out[140]
  PIN rw0_rd_out[141]
    DIRECTION OUTPUT ;
    USE SIGNAL ;
    SHAPE ABUTMENT ;
    PORT
      LAYER met2 ;
      RECT 74.450 652.380 74.590 652.800 ;
    END
  END rw0_rd_out[141]
  PIN rw0_rd_out[142]
    DIRECTION OUTPUT ;
    USE SIGNAL ;
    SHAPE ABUTMENT ;
    PORT
      LAYER met2 ;
      RECT 77.210 652.380 77.350 652.800 ;
    END
  END rw0_rd_out[142]
  PIN rw0_rd_out[143]
    DIRECTION OUTPUT ;
    USE SIGNAL ;
    SHAPE ABUTMENT ;
    PORT
      LAYER met2 ;
      RECT 79.970 652.380 80.110 652.800 ;
    END
  END rw0_rd_out[143]
  PIN rw0_rd_out[144]
    DIRECTION OUTPUT ;
    USE SIGNAL ;
    SHAPE ABUTMENT ;
    PORT
      LAYER met2 ;
      RECT 82.730 652.380 82.870 652.800 ;
    END
  END rw0_rd_out[144]
  PIN rw0_rd_out[145]
    DIRECTION OUTPUT ;
    USE SIGNAL ;
    SHAPE ABUTMENT ;
    PORT
      LAYER met2 ;
      RECT 85.490 652.380 85.630 652.800 ;
    END
  END rw0_rd_out[145]
  PIN rw0_rd_out[146]
    DIRECTION OUTPUT ;
    USE SIGNAL ;
    SHAPE ABUTMENT ;
    PORT
      LAYER met2 ;
      RECT 88.250 652.380 88.390 652.800 ;
    END
  END rw0_rd_out[146]
  PIN rw0_rd_out[147]
    DIRECTION OUTPUT ;
    USE SIGNAL ;
    SHAPE ABUTMENT ;
    PORT
      LAYER met2 ;
      RECT 91.010 652.380 91.150 652.800 ;
    END
  END rw0_rd_out[147]
  PIN rw0_rd_out[148]
    DIRECTION OUTPUT ;
    USE SIGNAL ;
    SHAPE ABUTMENT ;
    PORT
      LAYER met2 ;
      RECT 93.770 652.380 93.910 652.800 ;
    END
  END rw0_rd_out[148]
  PIN rw0_rd_out[149]
    DIRECTION OUTPUT ;
    USE SIGNAL ;
    SHAPE ABUTMENT ;
    PORT
      LAYER met2 ;
      RECT 96.530 652.380 96.670 652.800 ;
    END
  END rw0_rd_out[149]
  PIN rw0_rd_out[150]
    DIRECTION OUTPUT ;
    USE SIGNAL ;
    SHAPE ABUTMENT ;
    PORT
      LAYER met2 ;
      RECT 99.290 652.380 99.430 652.800 ;
    END
  END rw0_rd_out[150]
  PIN rw0_rd_out[151]
    DIRECTION OUTPUT ;
    USE SIGNAL ;
    SHAPE ABUTMENT ;
    PORT
      LAYER met2 ;
      RECT 102.050 652.380 102.190 652.800 ;
    END
  END rw0_rd_out[151]
  PIN rw0_rd_out[152]
    DIRECTION OUTPUT ;
    USE SIGNAL ;
    SHAPE ABUTMENT ;
    PORT
      LAYER met2 ;
      RECT 104.810 652.380 104.950 652.800 ;
    END
  END rw0_rd_out[152]
  PIN rw0_rd_out[153]
    DIRECTION OUTPUT ;
    USE SIGNAL ;
    SHAPE ABUTMENT ;
    PORT
      LAYER met2 ;
      RECT 107.570 652.380 107.710 652.800 ;
    END
  END rw0_rd_out[153]
  PIN rw0_rd_out[154]
    DIRECTION OUTPUT ;
    USE SIGNAL ;
    SHAPE ABUTMENT ;
    PORT
      LAYER met2 ;
      RECT 110.330 652.380 110.470 652.800 ;
    END
  END rw0_rd_out[154]
  PIN rw0_rd_out[155]
    DIRECTION OUTPUT ;
    USE SIGNAL ;
    SHAPE ABUTMENT ;
    PORT
      LAYER met2 ;
      RECT 113.090 652.380 113.230 652.800 ;
    END
  END rw0_rd_out[155]
  PIN rw0_rd_out[156]
    DIRECTION OUTPUT ;
    USE SIGNAL ;
    SHAPE ABUTMENT ;
    PORT
      LAYER met2 ;
      RECT 115.850 652.380 115.990 652.800 ;
    END
  END rw0_rd_out[156]
  PIN rw0_rd_out[157]
    DIRECTION OUTPUT ;
    USE SIGNAL ;
    SHAPE ABUTMENT ;
    PORT
      LAYER met2 ;
      RECT 118.610 652.380 118.750 652.800 ;
    END
  END rw0_rd_out[157]
  PIN rw0_rd_out[158]
    DIRECTION OUTPUT ;
    USE SIGNAL ;
    SHAPE ABUTMENT ;
    PORT
      LAYER met2 ;
      RECT 121.370 652.380 121.510 652.800 ;
    END
  END rw0_rd_out[158]
  PIN rw0_rd_out[159]
    DIRECTION OUTPUT ;
    USE SIGNAL ;
    SHAPE ABUTMENT ;
    PORT
      LAYER met2 ;
      RECT 124.130 652.380 124.270 652.800 ;
    END
  END rw0_rd_out[159]
  PIN rw0_rd_out[160]
    DIRECTION OUTPUT ;
    USE SIGNAL ;
    SHAPE ABUTMENT ;
    PORT
      LAYER met2 ;
      RECT 126.890 652.380 127.030 652.800 ;
    END
  END rw0_rd_out[160]
  PIN rw0_rd_out[161]
    DIRECTION OUTPUT ;
    USE SIGNAL ;
    SHAPE ABUTMENT ;
    PORT
      LAYER met2 ;
      RECT 129.650 652.380 129.790 652.800 ;
    END
  END rw0_rd_out[161]
  PIN rw0_rd_out[162]
    DIRECTION OUTPUT ;
    USE SIGNAL ;
    SHAPE ABUTMENT ;
    PORT
      LAYER met2 ;
      RECT 132.410 652.380 132.550 652.800 ;
    END
  END rw0_rd_out[162]
  PIN rw0_rd_out[163]
    DIRECTION OUTPUT ;
    USE SIGNAL ;
    SHAPE ABUTMENT ;
    PORT
      LAYER met2 ;
      RECT 135.170 652.380 135.310 652.800 ;
    END
  END rw0_rd_out[163]
  PIN rw0_rd_out[164]
    DIRECTION OUTPUT ;
    USE SIGNAL ;
    SHAPE ABUTMENT ;
    PORT
      LAYER met2 ;
      RECT 137.930 652.380 138.070 652.800 ;
    END
  END rw0_rd_out[164]
  PIN rw0_rd_out[165]
    DIRECTION OUTPUT ;
    USE SIGNAL ;
    SHAPE ABUTMENT ;
    PORT
      LAYER met2 ;
      RECT 140.690 652.380 140.830 652.800 ;
    END
  END rw0_rd_out[165]
  PIN rw0_rd_out[166]
    DIRECTION OUTPUT ;
    USE SIGNAL ;
    SHAPE ABUTMENT ;
    PORT
      LAYER met2 ;
      RECT 143.450 652.380 143.590 652.800 ;
    END
  END rw0_rd_out[166]
  PIN rw0_rd_out[167]
    DIRECTION OUTPUT ;
    USE SIGNAL ;
    SHAPE ABUTMENT ;
    PORT
      LAYER met2 ;
      RECT 146.210 652.380 146.350 652.800 ;
    END
  END rw0_rd_out[167]
  PIN rw0_rd_out[168]
    DIRECTION OUTPUT ;
    USE SIGNAL ;
    SHAPE ABUTMENT ;
    PORT
      LAYER met2 ;
      RECT 148.970 652.380 149.110 652.800 ;
    END
  END rw0_rd_out[168]
  PIN rw0_rd_out[169]
    DIRECTION OUTPUT ;
    USE SIGNAL ;
    SHAPE ABUTMENT ;
    PORT
      LAYER met2 ;
      RECT 151.730 652.380 151.870 652.800 ;
    END
  END rw0_rd_out[169]
  PIN rw0_rd_out[170]
    DIRECTION OUTPUT ;
    USE SIGNAL ;
    SHAPE ABUTMENT ;
    PORT
      LAYER met2 ;
      RECT 154.490 652.380 154.630 652.800 ;
    END
  END rw0_rd_out[170]
  PIN rw0_rd_out[171]
    DIRECTION OUTPUT ;
    USE SIGNAL ;
    SHAPE ABUTMENT ;
    PORT
      LAYER met2 ;
      RECT 157.250 652.380 157.390 652.800 ;
    END
  END rw0_rd_out[171]
  PIN rw0_rd_out[172]
    DIRECTION OUTPUT ;
    USE SIGNAL ;
    SHAPE ABUTMENT ;
    PORT
      LAYER met2 ;
      RECT 160.010 652.380 160.150 652.800 ;
    END
  END rw0_rd_out[172]
  PIN rw0_rd_out[173]
    DIRECTION OUTPUT ;
    USE SIGNAL ;
    SHAPE ABUTMENT ;
    PORT
      LAYER met2 ;
      RECT 162.770 652.380 162.910 652.800 ;
    END
  END rw0_rd_out[173]
  PIN rw0_rd_out[174]
    DIRECTION OUTPUT ;
    USE SIGNAL ;
    SHAPE ABUTMENT ;
    PORT
      LAYER met2 ;
      RECT 165.530 652.380 165.670 652.800 ;
    END
  END rw0_rd_out[174]
  PIN rw0_rd_out[175]
    DIRECTION OUTPUT ;
    USE SIGNAL ;
    SHAPE ABUTMENT ;
    PORT
      LAYER met2 ;
      RECT 168.290 652.380 168.430 652.800 ;
    END
  END rw0_rd_out[175]
  PIN rw0_rd_out[176]
    DIRECTION OUTPUT ;
    USE SIGNAL ;
    SHAPE ABUTMENT ;
    PORT
      LAYER met2 ;
      RECT 171.050 652.380 171.190 652.800 ;
    END
  END rw0_rd_out[176]
  PIN rw0_rd_out[177]
    DIRECTION OUTPUT ;
    USE SIGNAL ;
    SHAPE ABUTMENT ;
    PORT
      LAYER met2 ;
      RECT 173.810 652.380 173.950 652.800 ;
    END
  END rw0_rd_out[177]
  PIN rw0_rd_out[178]
    DIRECTION OUTPUT ;
    USE SIGNAL ;
    SHAPE ABUTMENT ;
    PORT
      LAYER met2 ;
      RECT 176.570 652.380 176.710 652.800 ;
    END
  END rw0_rd_out[178]
  PIN rw0_rd_out[179]
    DIRECTION OUTPUT ;
    USE SIGNAL ;
    SHAPE ABUTMENT ;
    PORT
      LAYER met2 ;
      RECT 179.330 652.380 179.470 652.800 ;
    END
  END rw0_rd_out[179]
  PIN rw0_rd_out[180]
    DIRECTION OUTPUT ;
    USE SIGNAL ;
    SHAPE ABUTMENT ;
    PORT
      LAYER met2 ;
      RECT 182.090 652.380 182.230 652.800 ;
    END
  END rw0_rd_out[180]
  PIN rw0_rd_out[181]
    DIRECTION OUTPUT ;
    USE SIGNAL ;
    SHAPE ABUTMENT ;
    PORT
      LAYER met2 ;
      RECT 184.850 652.380 184.990 652.800 ;
    END
  END rw0_rd_out[181]
  PIN rw0_rd_out[182]
    DIRECTION OUTPUT ;
    USE SIGNAL ;
    SHAPE ABUTMENT ;
    PORT
      LAYER met2 ;
      RECT 187.610 652.380 187.750 652.800 ;
    END
  END rw0_rd_out[182]
  PIN rw0_rd_out[183]
    DIRECTION OUTPUT ;
    USE SIGNAL ;
    SHAPE ABUTMENT ;
    PORT
      LAYER met2 ;
      RECT 190.370 652.380 190.510 652.800 ;
    END
  END rw0_rd_out[183]
  PIN rw0_rd_out[184]
    DIRECTION OUTPUT ;
    USE SIGNAL ;
    SHAPE ABUTMENT ;
    PORT
      LAYER met2 ;
      RECT 193.130 652.380 193.270 652.800 ;
    END
  END rw0_rd_out[184]
  PIN rw0_rd_out[185]
    DIRECTION OUTPUT ;
    USE SIGNAL ;
    SHAPE ABUTMENT ;
    PORT
      LAYER met2 ;
      RECT 195.890 652.380 196.030 652.800 ;
    END
  END rw0_rd_out[185]
  PIN rw0_rd_out[186]
    DIRECTION OUTPUT ;
    USE SIGNAL ;
    SHAPE ABUTMENT ;
    PORT
      LAYER met2 ;
      RECT 198.650 652.380 198.790 652.800 ;
    END
  END rw0_rd_out[186]
  PIN rw0_rd_out[187]
    DIRECTION OUTPUT ;
    USE SIGNAL ;
    SHAPE ABUTMENT ;
    PORT
      LAYER met2 ;
      RECT 201.410 652.380 201.550 652.800 ;
    END
  END rw0_rd_out[187]
  PIN rw0_rd_out[188]
    DIRECTION OUTPUT ;
    USE SIGNAL ;
    SHAPE ABUTMENT ;
    PORT
      LAYER met2 ;
      RECT 204.170 652.380 204.310 652.800 ;
    END
  END rw0_rd_out[188]
  PIN rw0_rd_out[189]
    DIRECTION OUTPUT ;
    USE SIGNAL ;
    SHAPE ABUTMENT ;
    PORT
      LAYER met2 ;
      RECT 206.930 652.380 207.070 652.800 ;
    END
  END rw0_rd_out[189]
  PIN rw0_rd_out[190]
    DIRECTION OUTPUT ;
    USE SIGNAL ;
    SHAPE ABUTMENT ;
    PORT
      LAYER met2 ;
      RECT 209.690 652.380 209.830 652.800 ;
    END
  END rw0_rd_out[190]
  PIN rw0_rd_out[191]
    DIRECTION OUTPUT ;
    USE SIGNAL ;
    SHAPE ABUTMENT ;
    PORT
      LAYER met2 ;
      RECT 212.450 652.380 212.590 652.800 ;
    END
  END rw0_rd_out[191]
  PIN rw0_rd_out[192]
    DIRECTION OUTPUT ;
    USE SIGNAL ;
    SHAPE ABUTMENT ;
    PORT
      LAYER met2 ;
      RECT 215.210 652.380 215.350 652.800 ;
    END
  END rw0_rd_out[192]
  PIN rw0_rd_out[193]
    DIRECTION OUTPUT ;
    USE SIGNAL ;
    SHAPE ABUTMENT ;
    PORT
      LAYER met2 ;
      RECT 217.970 652.380 218.110 652.800 ;
    END
  END rw0_rd_out[193]
  PIN rw0_rd_out[194]
    DIRECTION OUTPUT ;
    USE SIGNAL ;
    SHAPE ABUTMENT ;
    PORT
      LAYER met2 ;
      RECT 220.730 652.380 220.870 652.800 ;
    END
  END rw0_rd_out[194]
  PIN rw0_rd_out[195]
    DIRECTION OUTPUT ;
    USE SIGNAL ;
    SHAPE ABUTMENT ;
    PORT
      LAYER met2 ;
      RECT 223.490 652.380 223.630 652.800 ;
    END
  END rw0_rd_out[195]
  PIN rw0_rd_out[196]
    DIRECTION OUTPUT ;
    USE SIGNAL ;
    SHAPE ABUTMENT ;
    PORT
      LAYER met2 ;
      RECT 226.250 652.380 226.390 652.800 ;
    END
  END rw0_rd_out[196]
  PIN rw0_rd_out[197]
    DIRECTION OUTPUT ;
    USE SIGNAL ;
    SHAPE ABUTMENT ;
    PORT
      LAYER met2 ;
      RECT 229.010 652.380 229.150 652.800 ;
    END
  END rw0_rd_out[197]
  PIN rw0_rd_out[198]
    DIRECTION OUTPUT ;
    USE SIGNAL ;
    SHAPE ABUTMENT ;
    PORT
      LAYER met2 ;
      RECT 231.770 652.380 231.910 652.800 ;
    END
  END rw0_rd_out[198]
  PIN rw0_rd_out[199]
    DIRECTION OUTPUT ;
    USE SIGNAL ;
    SHAPE ABUTMENT ;
    PORT
      LAYER met2 ;
      RECT 234.530 652.380 234.670 652.800 ;
    END
  END rw0_rd_out[199]
  PIN rw0_rd_out[200]
    DIRECTION OUTPUT ;
    USE SIGNAL ;
    SHAPE ABUTMENT ;
    PORT
      LAYER met2 ;
      RECT 237.290 652.380 237.430 652.800 ;
    END
  END rw0_rd_out[200]
  PIN rw0_rd_out[201]
    DIRECTION OUTPUT ;
    USE SIGNAL ;
    SHAPE ABUTMENT ;
    PORT
      LAYER met2 ;
      RECT 240.050 652.380 240.190 652.800 ;
    END
  END rw0_rd_out[201]
  PIN rw0_rd_out[202]
    DIRECTION OUTPUT ;
    USE SIGNAL ;
    SHAPE ABUTMENT ;
    PORT
      LAYER met2 ;
      RECT 242.810 652.380 242.950 652.800 ;
    END
  END rw0_rd_out[202]
  PIN rw0_rd_out[203]
    DIRECTION OUTPUT ;
    USE SIGNAL ;
    SHAPE ABUTMENT ;
    PORT
      LAYER met2 ;
      RECT 245.570 652.380 245.710 652.800 ;
    END
  END rw0_rd_out[203]
  PIN rw0_rd_out[204]
    DIRECTION OUTPUT ;
    USE SIGNAL ;
    SHAPE ABUTMENT ;
    PORT
      LAYER met2 ;
      RECT 248.330 652.380 248.470 652.800 ;
    END
  END rw0_rd_out[204]
  PIN rw0_rd_out[205]
    DIRECTION OUTPUT ;
    USE SIGNAL ;
    SHAPE ABUTMENT ;
    PORT
      LAYER met2 ;
      RECT 251.090 652.380 251.230 652.800 ;
    END
  END rw0_rd_out[205]
  PIN rw0_rd_out[206]
    DIRECTION OUTPUT ;
    USE SIGNAL ;
    SHAPE ABUTMENT ;
    PORT
      LAYER met2 ;
      RECT 253.850 652.380 253.990 652.800 ;
    END
  END rw0_rd_out[206]
  PIN rw0_rd_out[207]
    DIRECTION OUTPUT ;
    USE SIGNAL ;
    SHAPE ABUTMENT ;
    PORT
      LAYER met2 ;
      RECT 256.610 652.380 256.750 652.800 ;
    END
  END rw0_rd_out[207]
  PIN rw0_rd_out[208]
    DIRECTION OUTPUT ;
    USE SIGNAL ;
    SHAPE ABUTMENT ;
    PORT
      LAYER met2 ;
      RECT 259.370 652.380 259.510 652.800 ;
    END
  END rw0_rd_out[208]
  PIN rw0_rd_out[209]
    DIRECTION OUTPUT ;
    USE SIGNAL ;
    SHAPE ABUTMENT ;
    PORT
      LAYER met2 ;
      RECT 262.130 652.380 262.270 652.800 ;
    END
  END rw0_rd_out[209]
  PIN rw0_rd_out[210]
    DIRECTION OUTPUT ;
    USE SIGNAL ;
    SHAPE ABUTMENT ;
    PORT
      LAYER met2 ;
      RECT 264.890 652.380 265.030 652.800 ;
    END
  END rw0_rd_out[210]
  PIN rw0_rd_out[211]
    DIRECTION OUTPUT ;
    USE SIGNAL ;
    SHAPE ABUTMENT ;
    PORT
      LAYER met2 ;
      RECT 267.650 652.380 267.790 652.800 ;
    END
  END rw0_rd_out[211]
  PIN rw0_rd_out[212]
    DIRECTION OUTPUT ;
    USE SIGNAL ;
    SHAPE ABUTMENT ;
    PORT
      LAYER met2 ;
      RECT 270.410 652.380 270.550 652.800 ;
    END
  END rw0_rd_out[212]
  PIN rw0_rd_out[213]
    DIRECTION OUTPUT ;
    USE SIGNAL ;
    SHAPE ABUTMENT ;
    PORT
      LAYER met2 ;
      RECT 273.170 652.380 273.310 652.800 ;
    END
  END rw0_rd_out[213]
  PIN rw0_rd_out[214]
    DIRECTION OUTPUT ;
    USE SIGNAL ;
    SHAPE ABUTMENT ;
    PORT
      LAYER met2 ;
      RECT 275.930 652.380 276.070 652.800 ;
    END
  END rw0_rd_out[214]
  PIN rw0_rd_out[215]
    DIRECTION OUTPUT ;
    USE SIGNAL ;
    SHAPE ABUTMENT ;
    PORT
      LAYER met2 ;
      RECT 278.690 652.380 278.830 652.800 ;
    END
  END rw0_rd_out[215]
  PIN rw0_rd_out[216]
    DIRECTION OUTPUT ;
    USE SIGNAL ;
    SHAPE ABUTMENT ;
    PORT
      LAYER met2 ;
      RECT 281.450 652.380 281.590 652.800 ;
    END
  END rw0_rd_out[216]
  PIN rw0_rd_out[217]
    DIRECTION OUTPUT ;
    USE SIGNAL ;
    SHAPE ABUTMENT ;
    PORT
      LAYER met2 ;
      RECT 284.210 652.380 284.350 652.800 ;
    END
  END rw0_rd_out[217]
  PIN rw0_rd_out[218]
    DIRECTION OUTPUT ;
    USE SIGNAL ;
    SHAPE ABUTMENT ;
    PORT
      LAYER met2 ;
      RECT 286.970 652.380 287.110 652.800 ;
    END
  END rw0_rd_out[218]
  PIN rw0_rd_out[219]
    DIRECTION OUTPUT ;
    USE SIGNAL ;
    SHAPE ABUTMENT ;
    PORT
      LAYER met2 ;
      RECT 289.730 652.380 289.870 652.800 ;
    END
  END rw0_rd_out[219]
  PIN rw0_rd_out[220]
    DIRECTION OUTPUT ;
    USE SIGNAL ;
    SHAPE ABUTMENT ;
    PORT
      LAYER met2 ;
      RECT 292.490 652.380 292.630 652.800 ;
    END
  END rw0_rd_out[220]
  PIN rw0_rd_out[221]
    DIRECTION OUTPUT ;
    USE SIGNAL ;
    SHAPE ABUTMENT ;
    PORT
      LAYER met2 ;
      RECT 295.250 652.380 295.390 652.800 ;
    END
  END rw0_rd_out[221]
  PIN rw0_rd_out[222]
    DIRECTION OUTPUT ;
    USE SIGNAL ;
    SHAPE ABUTMENT ;
    PORT
      LAYER met2 ;
      RECT 298.010 652.380 298.150 652.800 ;
    END
  END rw0_rd_out[222]
  PIN rw0_rd_out[223]
    DIRECTION OUTPUT ;
    USE SIGNAL ;
    SHAPE ABUTMENT ;
    PORT
      LAYER met2 ;
      RECT 300.770 652.380 300.910 652.800 ;
    END
  END rw0_rd_out[223]
  PIN rw0_rd_out[224]
    DIRECTION OUTPUT ;
    USE SIGNAL ;
    SHAPE ABUTMENT ;
    PORT
      LAYER met2 ;
      RECT 303.530 652.380 303.670 652.800 ;
    END
  END rw0_rd_out[224]
  PIN rw0_rd_out[225]
    DIRECTION OUTPUT ;
    USE SIGNAL ;
    SHAPE ABUTMENT ;
    PORT
      LAYER met2 ;
      RECT 306.290 652.380 306.430 652.800 ;
    END
  END rw0_rd_out[225]
  PIN rw0_rd_out[226]
    DIRECTION OUTPUT ;
    USE SIGNAL ;
    SHAPE ABUTMENT ;
    PORT
      LAYER met2 ;
      RECT 309.050 652.380 309.190 652.800 ;
    END
  END rw0_rd_out[226]
  PIN rw0_rd_out[227]
    DIRECTION OUTPUT ;
    USE SIGNAL ;
    SHAPE ABUTMENT ;
    PORT
      LAYER met2 ;
      RECT 311.810 652.380 311.950 652.800 ;
    END
  END rw0_rd_out[227]
  PIN rw0_rd_out[228]
    DIRECTION OUTPUT ;
    USE SIGNAL ;
    SHAPE ABUTMENT ;
    PORT
      LAYER met2 ;
      RECT 314.570 652.380 314.710 652.800 ;
    END
  END rw0_rd_out[228]
  PIN rw0_rd_out[229]
    DIRECTION OUTPUT ;
    USE SIGNAL ;
    SHAPE ABUTMENT ;
    PORT
      LAYER met2 ;
      RECT 317.330 652.380 317.470 652.800 ;
    END
  END rw0_rd_out[229]
  PIN r0_rd_out[0]
    DIRECTION OUTPUT ;
    USE SIGNAL ;
    SHAPE ABUTMENT ;
    PORT
      LAYER met2 ;
      RECT 425.890 0.000 426.030 0.420 ;
    END
  END r0_rd_out[0]
  PIN r0_rd_out[1]
    DIRECTION OUTPUT ;
    USE SIGNAL ;
    SHAPE ABUTMENT ;
    PORT
      LAYER met2 ;
      RECT 427.730 0.000 427.870 0.420 ;
    END
  END r0_rd_out[1]
  PIN r0_rd_out[2]
    DIRECTION OUTPUT ;
    USE SIGNAL ;
    SHAPE ABUTMENT ;
    PORT
      LAYER met2 ;
      RECT 429.570 0.000 429.710 0.420 ;
    END
  END r0_rd_out[2]
  PIN r0_rd_out[3]
    DIRECTION OUTPUT ;
    USE SIGNAL ;
    SHAPE ABUTMENT ;
    PORT
      LAYER met2 ;
      RECT 431.410 0.000 431.550 0.420 ;
    END
  END r0_rd_out[3]
  PIN r0_rd_out[4]
    DIRECTION OUTPUT ;
    USE SIGNAL ;
    SHAPE ABUTMENT ;
    PORT
      LAYER met2 ;
      RECT 433.250 0.000 433.390 0.420 ;
    END
  END r0_rd_out[4]
  PIN r0_rd_out[5]
    DIRECTION OUTPUT ;
    USE SIGNAL ;
    SHAPE ABUTMENT ;
    PORT
      LAYER met2 ;
      RECT 435.090 0.000 435.230 0.420 ;
    END
  END r0_rd_out[5]
  PIN r0_rd_out[6]
    DIRECTION OUTPUT ;
    USE SIGNAL ;
    SHAPE ABUTMENT ;
    PORT
      LAYER met2 ;
      RECT 436.930 0.000 437.070 0.420 ;
    END
  END r0_rd_out[6]
  PIN r0_rd_out[7]
    DIRECTION OUTPUT ;
    USE SIGNAL ;
    SHAPE ABUTMENT ;
    PORT
      LAYER met2 ;
      RECT 438.770 0.000 438.910 0.420 ;
    END
  END r0_rd_out[7]
  PIN r0_rd_out[8]
    DIRECTION OUTPUT ;
    USE SIGNAL ;
    SHAPE ABUTMENT ;
    PORT
      LAYER met2 ;
      RECT 440.610 0.000 440.750 0.420 ;
    END
  END r0_rd_out[8]
  PIN r0_rd_out[9]
    DIRECTION OUTPUT ;
    USE SIGNAL ;
    SHAPE ABUTMENT ;
    PORT
      LAYER met2 ;
      RECT 442.450 0.000 442.590 0.420 ;
    END
  END r0_rd_out[9]
  PIN r0_rd_out[10]
    DIRECTION OUTPUT ;
    USE SIGNAL ;
    SHAPE ABUTMENT ;
    PORT
      LAYER met2 ;
      RECT 444.290 0.000 444.430 0.420 ;
    END
  END r0_rd_out[10]
  PIN r0_rd_out[11]
    DIRECTION OUTPUT ;
    USE SIGNAL ;
    SHAPE ABUTMENT ;
    PORT
      LAYER met2 ;
      RECT 446.130 0.000 446.270 0.420 ;
    END
  END r0_rd_out[11]
  PIN r0_rd_out[12]
    DIRECTION OUTPUT ;
    USE SIGNAL ;
    SHAPE ABUTMENT ;
    PORT
      LAYER met2 ;
      RECT 447.970 0.000 448.110 0.420 ;
    END
  END r0_rd_out[12]
  PIN r0_rd_out[13]
    DIRECTION OUTPUT ;
    USE SIGNAL ;
    SHAPE ABUTMENT ;
    PORT
      LAYER met2 ;
      RECT 449.810 0.000 449.950 0.420 ;
    END
  END r0_rd_out[13]
  PIN r0_rd_out[14]
    DIRECTION OUTPUT ;
    USE SIGNAL ;
    SHAPE ABUTMENT ;
    PORT
      LAYER met2 ;
      RECT 451.650 0.000 451.790 0.420 ;
    END
  END r0_rd_out[14]
  PIN r0_rd_out[15]
    DIRECTION OUTPUT ;
    USE SIGNAL ;
    SHAPE ABUTMENT ;
    PORT
      LAYER met2 ;
      RECT 453.490 0.000 453.630 0.420 ;
    END
  END r0_rd_out[15]
  PIN r0_rd_out[16]
    DIRECTION OUTPUT ;
    USE SIGNAL ;
    SHAPE ABUTMENT ;
    PORT
      LAYER met2 ;
      RECT 455.330 0.000 455.470 0.420 ;
    END
  END r0_rd_out[16]
  PIN r0_rd_out[17]
    DIRECTION OUTPUT ;
    USE SIGNAL ;
    SHAPE ABUTMENT ;
    PORT
      LAYER met2 ;
      RECT 457.170 0.000 457.310 0.420 ;
    END
  END r0_rd_out[17]
  PIN r0_rd_out[18]
    DIRECTION OUTPUT ;
    USE SIGNAL ;
    SHAPE ABUTMENT ;
    PORT
      LAYER met2 ;
      RECT 459.010 0.000 459.150 0.420 ;
    END
  END r0_rd_out[18]
  PIN r0_rd_out[19]
    DIRECTION OUTPUT ;
    USE SIGNAL ;
    SHAPE ABUTMENT ;
    PORT
      LAYER met2 ;
      RECT 460.850 0.000 460.990 0.420 ;
    END
  END r0_rd_out[19]
  PIN r0_rd_out[20]
    DIRECTION OUTPUT ;
    USE SIGNAL ;
    SHAPE ABUTMENT ;
    PORT
      LAYER met2 ;
      RECT 462.690 0.000 462.830 0.420 ;
    END
  END r0_rd_out[20]
  PIN r0_rd_out[21]
    DIRECTION OUTPUT ;
    USE SIGNAL ;
    SHAPE ABUTMENT ;
    PORT
      LAYER met2 ;
      RECT 464.530 0.000 464.670 0.420 ;
    END
  END r0_rd_out[21]
  PIN r0_rd_out[22]
    DIRECTION OUTPUT ;
    USE SIGNAL ;
    SHAPE ABUTMENT ;
    PORT
      LAYER met2 ;
      RECT 466.370 0.000 466.510 0.420 ;
    END
  END r0_rd_out[22]
  PIN r0_rd_out[23]
    DIRECTION OUTPUT ;
    USE SIGNAL ;
    SHAPE ABUTMENT ;
    PORT
      LAYER met2 ;
      RECT 468.210 0.000 468.350 0.420 ;
    END
  END r0_rd_out[23]
  PIN r0_rd_out[24]
    DIRECTION OUTPUT ;
    USE SIGNAL ;
    SHAPE ABUTMENT ;
    PORT
      LAYER met2 ;
      RECT 470.050 0.000 470.190 0.420 ;
    END
  END r0_rd_out[24]
  PIN r0_rd_out[25]
    DIRECTION OUTPUT ;
    USE SIGNAL ;
    SHAPE ABUTMENT ;
    PORT
      LAYER met2 ;
      RECT 471.890 0.000 472.030 0.420 ;
    END
  END r0_rd_out[25]
  PIN r0_rd_out[26]
    DIRECTION OUTPUT ;
    USE SIGNAL ;
    SHAPE ABUTMENT ;
    PORT
      LAYER met2 ;
      RECT 473.730 0.000 473.870 0.420 ;
    END
  END r0_rd_out[26]
  PIN r0_rd_out[27]
    DIRECTION OUTPUT ;
    USE SIGNAL ;
    SHAPE ABUTMENT ;
    PORT
      LAYER met2 ;
      RECT 475.570 0.000 475.710 0.420 ;
    END
  END r0_rd_out[27]
  PIN r0_rd_out[28]
    DIRECTION OUTPUT ;
    USE SIGNAL ;
    SHAPE ABUTMENT ;
    PORT
      LAYER met2 ;
      RECT 477.410 0.000 477.550 0.420 ;
    END
  END r0_rd_out[28]
  PIN r0_rd_out[29]
    DIRECTION OUTPUT ;
    USE SIGNAL ;
    SHAPE ABUTMENT ;
    PORT
      LAYER met2 ;
      RECT 479.250 0.000 479.390 0.420 ;
    END
  END r0_rd_out[29]
  PIN r0_rd_out[30]
    DIRECTION OUTPUT ;
    USE SIGNAL ;
    SHAPE ABUTMENT ;
    PORT
      LAYER met2 ;
      RECT 481.090 0.000 481.230 0.420 ;
    END
  END r0_rd_out[30]
  PIN r0_rd_out[31]
    DIRECTION OUTPUT ;
    USE SIGNAL ;
    SHAPE ABUTMENT ;
    PORT
      LAYER met2 ;
      RECT 482.930 0.000 483.070 0.420 ;
    END
  END r0_rd_out[31]
  PIN r0_rd_out[32]
    DIRECTION OUTPUT ;
    USE SIGNAL ;
    SHAPE ABUTMENT ;
    PORT
      LAYER met2 ;
      RECT 484.770 0.000 484.910 0.420 ;
    END
  END r0_rd_out[32]
  PIN r0_rd_out[33]
    DIRECTION OUTPUT ;
    USE SIGNAL ;
    SHAPE ABUTMENT ;
    PORT
      LAYER met2 ;
      RECT 486.610 0.000 486.750 0.420 ;
    END
  END r0_rd_out[33]
  PIN r0_rd_out[34]
    DIRECTION OUTPUT ;
    USE SIGNAL ;
    SHAPE ABUTMENT ;
    PORT
      LAYER met2 ;
      RECT 488.450 0.000 488.590 0.420 ;
    END
  END r0_rd_out[34]
  PIN r0_rd_out[35]
    DIRECTION OUTPUT ;
    USE SIGNAL ;
    SHAPE ABUTMENT ;
    PORT
      LAYER met2 ;
      RECT 490.290 0.000 490.430 0.420 ;
    END
  END r0_rd_out[35]
  PIN r0_rd_out[36]
    DIRECTION OUTPUT ;
    USE SIGNAL ;
    SHAPE ABUTMENT ;
    PORT
      LAYER met2 ;
      RECT 492.130 0.000 492.270 0.420 ;
    END
  END r0_rd_out[36]
  PIN r0_rd_out[37]
    DIRECTION OUTPUT ;
    USE SIGNAL ;
    SHAPE ABUTMENT ;
    PORT
      LAYER met2 ;
      RECT 493.970 0.000 494.110 0.420 ;
    END
  END r0_rd_out[37]
  PIN r0_rd_out[38]
    DIRECTION OUTPUT ;
    USE SIGNAL ;
    SHAPE ABUTMENT ;
    PORT
      LAYER met2 ;
      RECT 495.810 0.000 495.950 0.420 ;
    END
  END r0_rd_out[38]
  PIN r0_rd_out[39]
    DIRECTION OUTPUT ;
    USE SIGNAL ;
    SHAPE ABUTMENT ;
    PORT
      LAYER met2 ;
      RECT 497.650 0.000 497.790 0.420 ;
    END
  END r0_rd_out[39]
  PIN r0_rd_out[40]
    DIRECTION OUTPUT ;
    USE SIGNAL ;
    SHAPE ABUTMENT ;
    PORT
      LAYER met2 ;
      RECT 499.490 0.000 499.630 0.420 ;
    END
  END r0_rd_out[40]
  PIN r0_rd_out[41]
    DIRECTION OUTPUT ;
    USE SIGNAL ;
    SHAPE ABUTMENT ;
    PORT
      LAYER met2 ;
      RECT 501.330 0.000 501.470 0.420 ;
    END
  END r0_rd_out[41]
  PIN r0_rd_out[42]
    DIRECTION OUTPUT ;
    USE SIGNAL ;
    SHAPE ABUTMENT ;
    PORT
      LAYER met2 ;
      RECT 503.170 0.000 503.310 0.420 ;
    END
  END r0_rd_out[42]
  PIN r0_rd_out[43]
    DIRECTION OUTPUT ;
    USE SIGNAL ;
    SHAPE ABUTMENT ;
    PORT
      LAYER met2 ;
      RECT 505.010 0.000 505.150 0.420 ;
    END
  END r0_rd_out[43]
  PIN r0_rd_out[44]
    DIRECTION OUTPUT ;
    USE SIGNAL ;
    SHAPE ABUTMENT ;
    PORT
      LAYER met2 ;
      RECT 506.850 0.000 506.990 0.420 ;
    END
  END r0_rd_out[44]
  PIN r0_rd_out[45]
    DIRECTION OUTPUT ;
    USE SIGNAL ;
    SHAPE ABUTMENT ;
    PORT
      LAYER met2 ;
      RECT 508.690 0.000 508.830 0.420 ;
    END
  END r0_rd_out[45]
  PIN r0_rd_out[46]
    DIRECTION OUTPUT ;
    USE SIGNAL ;
    SHAPE ABUTMENT ;
    PORT
      LAYER met2 ;
      RECT 510.530 0.000 510.670 0.420 ;
    END
  END r0_rd_out[46]
  PIN r0_rd_out[47]
    DIRECTION OUTPUT ;
    USE SIGNAL ;
    SHAPE ABUTMENT ;
    PORT
      LAYER met2 ;
      RECT 512.370 0.000 512.510 0.420 ;
    END
  END r0_rd_out[47]
  PIN r0_rd_out[48]
    DIRECTION OUTPUT ;
    USE SIGNAL ;
    SHAPE ABUTMENT ;
    PORT
      LAYER met2 ;
      RECT 514.210 0.000 514.350 0.420 ;
    END
  END r0_rd_out[48]
  PIN r0_rd_out[49]
    DIRECTION OUTPUT ;
    USE SIGNAL ;
    SHAPE ABUTMENT ;
    PORT
      LAYER met2 ;
      RECT 516.050 0.000 516.190 0.420 ;
    END
  END r0_rd_out[49]
  PIN r0_rd_out[50]
    DIRECTION OUTPUT ;
    USE SIGNAL ;
    SHAPE ABUTMENT ;
    PORT
      LAYER met2 ;
      RECT 517.890 0.000 518.030 0.420 ;
    END
  END r0_rd_out[50]
  PIN r0_rd_out[51]
    DIRECTION OUTPUT ;
    USE SIGNAL ;
    SHAPE ABUTMENT ;
    PORT
      LAYER met2 ;
      RECT 519.730 0.000 519.870 0.420 ;
    END
  END r0_rd_out[51]
  PIN r0_rd_out[52]
    DIRECTION OUTPUT ;
    USE SIGNAL ;
    SHAPE ABUTMENT ;
    PORT
      LAYER met2 ;
      RECT 521.570 0.000 521.710 0.420 ;
    END
  END r0_rd_out[52]
  PIN r0_rd_out[53]
    DIRECTION OUTPUT ;
    USE SIGNAL ;
    SHAPE ABUTMENT ;
    PORT
      LAYER met2 ;
      RECT 523.410 0.000 523.550 0.420 ;
    END
  END r0_rd_out[53]
  PIN r0_rd_out[54]
    DIRECTION OUTPUT ;
    USE SIGNAL ;
    SHAPE ABUTMENT ;
    PORT
      LAYER met2 ;
      RECT 525.250 0.000 525.390 0.420 ;
    END
  END r0_rd_out[54]
  PIN r0_rd_out[55]
    DIRECTION OUTPUT ;
    USE SIGNAL ;
    SHAPE ABUTMENT ;
    PORT
      LAYER met2 ;
      RECT 527.090 0.000 527.230 0.420 ;
    END
  END r0_rd_out[55]
  PIN r0_rd_out[56]
    DIRECTION OUTPUT ;
    USE SIGNAL ;
    SHAPE ABUTMENT ;
    PORT
      LAYER met2 ;
      RECT 528.930 0.000 529.070 0.420 ;
    END
  END r0_rd_out[56]
  PIN r0_rd_out[57]
    DIRECTION OUTPUT ;
    USE SIGNAL ;
    SHAPE ABUTMENT ;
    PORT
      LAYER met2 ;
      RECT 530.770 0.000 530.910 0.420 ;
    END
  END r0_rd_out[57]
  PIN r0_rd_out[58]
    DIRECTION OUTPUT ;
    USE SIGNAL ;
    SHAPE ABUTMENT ;
    PORT
      LAYER met2 ;
      RECT 532.610 0.000 532.750 0.420 ;
    END
  END r0_rd_out[58]
  PIN r0_rd_out[59]
    DIRECTION OUTPUT ;
    USE SIGNAL ;
    SHAPE ABUTMENT ;
    PORT
      LAYER met2 ;
      RECT 534.450 0.000 534.590 0.420 ;
    END
  END r0_rd_out[59]
  PIN r0_rd_out[60]
    DIRECTION OUTPUT ;
    USE SIGNAL ;
    SHAPE ABUTMENT ;
    PORT
      LAYER met2 ;
      RECT 536.290 0.000 536.430 0.420 ;
    END
  END r0_rd_out[60]
  PIN r0_rd_out[61]
    DIRECTION OUTPUT ;
    USE SIGNAL ;
    SHAPE ABUTMENT ;
    PORT
      LAYER met2 ;
      RECT 538.130 0.000 538.270 0.420 ;
    END
  END r0_rd_out[61]
  PIN r0_rd_out[62]
    DIRECTION OUTPUT ;
    USE SIGNAL ;
    SHAPE ABUTMENT ;
    PORT
      LAYER met2 ;
      RECT 539.970 0.000 540.110 0.420 ;
    END
  END r0_rd_out[62]
  PIN r0_rd_out[63]
    DIRECTION OUTPUT ;
    USE SIGNAL ;
    SHAPE ABUTMENT ;
    PORT
      LAYER met2 ;
      RECT 541.810 0.000 541.950 0.420 ;
    END
  END r0_rd_out[63]
  PIN r0_rd_out[64]
    DIRECTION OUTPUT ;
    USE SIGNAL ;
    SHAPE ABUTMENT ;
    PORT
      LAYER met2 ;
      RECT 543.650 0.000 543.790 0.420 ;
    END
  END r0_rd_out[64]
  PIN r0_rd_out[65]
    DIRECTION OUTPUT ;
    USE SIGNAL ;
    SHAPE ABUTMENT ;
    PORT
      LAYER met2 ;
      RECT 545.490 0.000 545.630 0.420 ;
    END
  END r0_rd_out[65]
  PIN r0_rd_out[66]
    DIRECTION OUTPUT ;
    USE SIGNAL ;
    SHAPE ABUTMENT ;
    PORT
      LAYER met2 ;
      RECT 547.330 0.000 547.470 0.420 ;
    END
  END r0_rd_out[66]
  PIN r0_rd_out[67]
    DIRECTION OUTPUT ;
    USE SIGNAL ;
    SHAPE ABUTMENT ;
    PORT
      LAYER met2 ;
      RECT 549.170 0.000 549.310 0.420 ;
    END
  END r0_rd_out[67]
  PIN r0_rd_out[68]
    DIRECTION OUTPUT ;
    USE SIGNAL ;
    SHAPE ABUTMENT ;
    PORT
      LAYER met2 ;
      RECT 551.010 0.000 551.150 0.420 ;
    END
  END r0_rd_out[68]
  PIN r0_rd_out[69]
    DIRECTION OUTPUT ;
    USE SIGNAL ;
    SHAPE ABUTMENT ;
    PORT
      LAYER met2 ;
      RECT 552.850 0.000 552.990 0.420 ;
    END
  END r0_rd_out[69]
  PIN r0_rd_out[70]
    DIRECTION OUTPUT ;
    USE SIGNAL ;
    SHAPE ABUTMENT ;
    PORT
      LAYER met2 ;
      RECT 554.690 0.000 554.830 0.420 ;
    END
  END r0_rd_out[70]
  PIN r0_rd_out[71]
    DIRECTION OUTPUT ;
    USE SIGNAL ;
    SHAPE ABUTMENT ;
    PORT
      LAYER met2 ;
      RECT 556.530 0.000 556.670 0.420 ;
    END
  END r0_rd_out[71]
  PIN r0_rd_out[72]
    DIRECTION OUTPUT ;
    USE SIGNAL ;
    SHAPE ABUTMENT ;
    PORT
      LAYER met2 ;
      RECT 558.370 0.000 558.510 0.420 ;
    END
  END r0_rd_out[72]
  PIN r0_rd_out[73]
    DIRECTION OUTPUT ;
    USE SIGNAL ;
    SHAPE ABUTMENT ;
    PORT
      LAYER met2 ;
      RECT 560.210 0.000 560.350 0.420 ;
    END
  END r0_rd_out[73]
  PIN r0_rd_out[74]
    DIRECTION OUTPUT ;
    USE SIGNAL ;
    SHAPE ABUTMENT ;
    PORT
      LAYER met2 ;
      RECT 562.050 0.000 562.190 0.420 ;
    END
  END r0_rd_out[74]
  PIN r0_rd_out[75]
    DIRECTION OUTPUT ;
    USE SIGNAL ;
    SHAPE ABUTMENT ;
    PORT
      LAYER met2 ;
      RECT 563.890 0.000 564.030 0.420 ;
    END
  END r0_rd_out[75]
  PIN r0_rd_out[76]
    DIRECTION OUTPUT ;
    USE SIGNAL ;
    SHAPE ABUTMENT ;
    PORT
      LAYER met2 ;
      RECT 565.730 0.000 565.870 0.420 ;
    END
  END r0_rd_out[76]
  PIN r0_rd_out[77]
    DIRECTION OUTPUT ;
    USE SIGNAL ;
    SHAPE ABUTMENT ;
    PORT
      LAYER met2 ;
      RECT 567.570 0.000 567.710 0.420 ;
    END
  END r0_rd_out[77]
  PIN r0_rd_out[78]
    DIRECTION OUTPUT ;
    USE SIGNAL ;
    SHAPE ABUTMENT ;
    PORT
      LAYER met2 ;
      RECT 569.410 0.000 569.550 0.420 ;
    END
  END r0_rd_out[78]
  PIN r0_rd_out[79]
    DIRECTION OUTPUT ;
    USE SIGNAL ;
    SHAPE ABUTMENT ;
    PORT
      LAYER met2 ;
      RECT 571.250 0.000 571.390 0.420 ;
    END
  END r0_rd_out[79]
  PIN r0_rd_out[80]
    DIRECTION OUTPUT ;
    USE SIGNAL ;
    SHAPE ABUTMENT ;
    PORT
      LAYER met2 ;
      RECT 573.090 0.000 573.230 0.420 ;
    END
  END r0_rd_out[80]
  PIN r0_rd_out[81]
    DIRECTION OUTPUT ;
    USE SIGNAL ;
    SHAPE ABUTMENT ;
    PORT
      LAYER met2 ;
      RECT 574.930 0.000 575.070 0.420 ;
    END
  END r0_rd_out[81]
  PIN r0_rd_out[82]
    DIRECTION OUTPUT ;
    USE SIGNAL ;
    SHAPE ABUTMENT ;
    PORT
      LAYER met2 ;
      RECT 576.770 0.000 576.910 0.420 ;
    END
  END r0_rd_out[82]
  PIN r0_rd_out[83]
    DIRECTION OUTPUT ;
    USE SIGNAL ;
    SHAPE ABUTMENT ;
    PORT
      LAYER met2 ;
      RECT 578.610 0.000 578.750 0.420 ;
    END
  END r0_rd_out[83]
  PIN r0_rd_out[84]
    DIRECTION OUTPUT ;
    USE SIGNAL ;
    SHAPE ABUTMENT ;
    PORT
      LAYER met2 ;
      RECT 580.450 0.000 580.590 0.420 ;
    END
  END r0_rd_out[84]
  PIN r0_rd_out[85]
    DIRECTION OUTPUT ;
    USE SIGNAL ;
    SHAPE ABUTMENT ;
    PORT
      LAYER met2 ;
      RECT 582.290 0.000 582.430 0.420 ;
    END
  END r0_rd_out[85]
  PIN r0_rd_out[86]
    DIRECTION OUTPUT ;
    USE SIGNAL ;
    SHAPE ABUTMENT ;
    PORT
      LAYER met2 ;
      RECT 584.130 0.000 584.270 0.420 ;
    END
  END r0_rd_out[86]
  PIN r0_rd_out[87]
    DIRECTION OUTPUT ;
    USE SIGNAL ;
    SHAPE ABUTMENT ;
    PORT
      LAYER met2 ;
      RECT 585.970 0.000 586.110 0.420 ;
    END
  END r0_rd_out[87]
  PIN r0_rd_out[88]
    DIRECTION OUTPUT ;
    USE SIGNAL ;
    SHAPE ABUTMENT ;
    PORT
      LAYER met2 ;
      RECT 587.810 0.000 587.950 0.420 ;
    END
  END r0_rd_out[88]
  PIN r0_rd_out[89]
    DIRECTION OUTPUT ;
    USE SIGNAL ;
    SHAPE ABUTMENT ;
    PORT
      LAYER met2 ;
      RECT 589.650 0.000 589.790 0.420 ;
    END
  END r0_rd_out[89]
  PIN r0_rd_out[90]
    DIRECTION OUTPUT ;
    USE SIGNAL ;
    SHAPE ABUTMENT ;
    PORT
      LAYER met2 ;
      RECT 591.490 0.000 591.630 0.420 ;
    END
  END r0_rd_out[90]
  PIN r0_rd_out[91]
    DIRECTION OUTPUT ;
    USE SIGNAL ;
    SHAPE ABUTMENT ;
    PORT
      LAYER met2 ;
      RECT 593.330 0.000 593.470 0.420 ;
    END
  END r0_rd_out[91]
  PIN r0_rd_out[92]
    DIRECTION OUTPUT ;
    USE SIGNAL ;
    SHAPE ABUTMENT ;
    PORT
      LAYER met2 ;
      RECT 595.170 0.000 595.310 0.420 ;
    END
  END r0_rd_out[92]
  PIN r0_rd_out[93]
    DIRECTION OUTPUT ;
    USE SIGNAL ;
    SHAPE ABUTMENT ;
    PORT
      LAYER met2 ;
      RECT 597.010 0.000 597.150 0.420 ;
    END
  END r0_rd_out[93]
  PIN r0_rd_out[94]
    DIRECTION OUTPUT ;
    USE SIGNAL ;
    SHAPE ABUTMENT ;
    PORT
      LAYER met2 ;
      RECT 598.850 0.000 598.990 0.420 ;
    END
  END r0_rd_out[94]
  PIN r0_rd_out[95]
    DIRECTION OUTPUT ;
    USE SIGNAL ;
    SHAPE ABUTMENT ;
    PORT
      LAYER met2 ;
      RECT 600.690 0.000 600.830 0.420 ;
    END
  END r0_rd_out[95]
  PIN r0_rd_out[96]
    DIRECTION OUTPUT ;
    USE SIGNAL ;
    SHAPE ABUTMENT ;
    PORT
      LAYER met2 ;
      RECT 602.530 0.000 602.670 0.420 ;
    END
  END r0_rd_out[96]
  PIN r0_rd_out[97]
    DIRECTION OUTPUT ;
    USE SIGNAL ;
    SHAPE ABUTMENT ;
    PORT
      LAYER met2 ;
      RECT 604.370 0.000 604.510 0.420 ;
    END
  END r0_rd_out[97]
  PIN r0_rd_out[98]
    DIRECTION OUTPUT ;
    USE SIGNAL ;
    SHAPE ABUTMENT ;
    PORT
      LAYER met2 ;
      RECT 606.210 0.000 606.350 0.420 ;
    END
  END r0_rd_out[98]
  PIN r0_rd_out[99]
    DIRECTION OUTPUT ;
    USE SIGNAL ;
    SHAPE ABUTMENT ;
    PORT
      LAYER met2 ;
      RECT 608.050 0.000 608.190 0.420 ;
    END
  END r0_rd_out[99]
  PIN r0_rd_out[100]
    DIRECTION OUTPUT ;
    USE SIGNAL ;
    SHAPE ABUTMENT ;
    PORT
      LAYER met2 ;
      RECT 609.890 0.000 610.030 0.420 ;
    END
  END r0_rd_out[100]
  PIN r0_rd_out[101]
    DIRECTION OUTPUT ;
    USE SIGNAL ;
    SHAPE ABUTMENT ;
    PORT
      LAYER met2 ;
      RECT 611.730 0.000 611.870 0.420 ;
    END
  END r0_rd_out[101]
  PIN r0_rd_out[102]
    DIRECTION OUTPUT ;
    USE SIGNAL ;
    SHAPE ABUTMENT ;
    PORT
      LAYER met2 ;
      RECT 613.570 0.000 613.710 0.420 ;
    END
  END r0_rd_out[102]
  PIN r0_rd_out[103]
    DIRECTION OUTPUT ;
    USE SIGNAL ;
    SHAPE ABUTMENT ;
    PORT
      LAYER met2 ;
      RECT 615.410 0.000 615.550 0.420 ;
    END
  END r0_rd_out[103]
  PIN r0_rd_out[104]
    DIRECTION OUTPUT ;
    USE SIGNAL ;
    SHAPE ABUTMENT ;
    PORT
      LAYER met2 ;
      RECT 617.250 0.000 617.390 0.420 ;
    END
  END r0_rd_out[104]
  PIN r0_rd_out[105]
    DIRECTION OUTPUT ;
    USE SIGNAL ;
    SHAPE ABUTMENT ;
    PORT
      LAYER met2 ;
      RECT 619.090 0.000 619.230 0.420 ;
    END
  END r0_rd_out[105]
  PIN r0_rd_out[106]
    DIRECTION OUTPUT ;
    USE SIGNAL ;
    SHAPE ABUTMENT ;
    PORT
      LAYER met2 ;
      RECT 620.930 0.000 621.070 0.420 ;
    END
  END r0_rd_out[106]
  PIN r0_rd_out[107]
    DIRECTION OUTPUT ;
    USE SIGNAL ;
    SHAPE ABUTMENT ;
    PORT
      LAYER met2 ;
      RECT 622.770 0.000 622.910 0.420 ;
    END
  END r0_rd_out[107]
  PIN r0_rd_out[108]
    DIRECTION OUTPUT ;
    USE SIGNAL ;
    SHAPE ABUTMENT ;
    PORT
      LAYER met2 ;
      RECT 624.610 0.000 624.750 0.420 ;
    END
  END r0_rd_out[108]
  PIN r0_rd_out[109]
    DIRECTION OUTPUT ;
    USE SIGNAL ;
    SHAPE ABUTMENT ;
    PORT
      LAYER met2 ;
      RECT 626.450 0.000 626.590 0.420 ;
    END
  END r0_rd_out[109]
  PIN r0_rd_out[110]
    DIRECTION OUTPUT ;
    USE SIGNAL ;
    SHAPE ABUTMENT ;
    PORT
      LAYER met2 ;
      RECT 628.290 0.000 628.430 0.420 ;
    END
  END r0_rd_out[110]
  PIN r0_rd_out[111]
    DIRECTION OUTPUT ;
    USE SIGNAL ;
    SHAPE ABUTMENT ;
    PORT
      LAYER met2 ;
      RECT 630.130 0.000 630.270 0.420 ;
    END
  END r0_rd_out[111]
  PIN r0_rd_out[112]
    DIRECTION OUTPUT ;
    USE SIGNAL ;
    SHAPE ABUTMENT ;
    PORT
      LAYER met2 ;
      RECT 631.970 0.000 632.110 0.420 ;
    END
  END r0_rd_out[112]
  PIN r0_rd_out[113]
    DIRECTION OUTPUT ;
    USE SIGNAL ;
    SHAPE ABUTMENT ;
    PORT
      LAYER met2 ;
      RECT 633.810 0.000 633.950 0.420 ;
    END
  END r0_rd_out[113]
  PIN r0_rd_out[114]
    DIRECTION OUTPUT ;
    USE SIGNAL ;
    SHAPE ABUTMENT ;
    PORT
      LAYER met2 ;
      RECT 635.650 0.000 635.790 0.420 ;
    END
  END r0_rd_out[114]
  PIN r0_rd_out[115]
    DIRECTION OUTPUT ;
    USE SIGNAL ;
    SHAPE ABUTMENT ;
    PORT
      LAYER met2 ;
      RECT 320.090 652.380 320.230 652.800 ;
    END
  END r0_rd_out[115]
  PIN r0_rd_out[116]
    DIRECTION OUTPUT ;
    USE SIGNAL ;
    SHAPE ABUTMENT ;
    PORT
      LAYER met2 ;
      RECT 322.850 652.380 322.990 652.800 ;
    END
  END r0_rd_out[116]
  PIN r0_rd_out[117]
    DIRECTION OUTPUT ;
    USE SIGNAL ;
    SHAPE ABUTMENT ;
    PORT
      LAYER met2 ;
      RECT 325.610 652.380 325.750 652.800 ;
    END
  END r0_rd_out[117]
  PIN r0_rd_out[118]
    DIRECTION OUTPUT ;
    USE SIGNAL ;
    SHAPE ABUTMENT ;
    PORT
      LAYER met2 ;
      RECT 328.370 652.380 328.510 652.800 ;
    END
  END r0_rd_out[118]
  PIN r0_rd_out[119]
    DIRECTION OUTPUT ;
    USE SIGNAL ;
    SHAPE ABUTMENT ;
    PORT
      LAYER met2 ;
      RECT 331.130 652.380 331.270 652.800 ;
    END
  END r0_rd_out[119]
  PIN r0_rd_out[120]
    DIRECTION OUTPUT ;
    USE SIGNAL ;
    SHAPE ABUTMENT ;
    PORT
      LAYER met2 ;
      RECT 333.890 652.380 334.030 652.800 ;
    END
  END r0_rd_out[120]
  PIN r0_rd_out[121]
    DIRECTION OUTPUT ;
    USE SIGNAL ;
    SHAPE ABUTMENT ;
    PORT
      LAYER met2 ;
      RECT 336.650 652.380 336.790 652.800 ;
    END
  END r0_rd_out[121]
  PIN r0_rd_out[122]
    DIRECTION OUTPUT ;
    USE SIGNAL ;
    SHAPE ABUTMENT ;
    PORT
      LAYER met2 ;
      RECT 339.410 652.380 339.550 652.800 ;
    END
  END r0_rd_out[122]
  PIN r0_rd_out[123]
    DIRECTION OUTPUT ;
    USE SIGNAL ;
    SHAPE ABUTMENT ;
    PORT
      LAYER met2 ;
      RECT 342.170 652.380 342.310 652.800 ;
    END
  END r0_rd_out[123]
  PIN r0_rd_out[124]
    DIRECTION OUTPUT ;
    USE SIGNAL ;
    SHAPE ABUTMENT ;
    PORT
      LAYER met2 ;
      RECT 344.930 652.380 345.070 652.800 ;
    END
  END r0_rd_out[124]
  PIN r0_rd_out[125]
    DIRECTION OUTPUT ;
    USE SIGNAL ;
    SHAPE ABUTMENT ;
    PORT
      LAYER met2 ;
      RECT 347.690 652.380 347.830 652.800 ;
    END
  END r0_rd_out[125]
  PIN r0_rd_out[126]
    DIRECTION OUTPUT ;
    USE SIGNAL ;
    SHAPE ABUTMENT ;
    PORT
      LAYER met2 ;
      RECT 350.450 652.380 350.590 652.800 ;
    END
  END r0_rd_out[126]
  PIN r0_rd_out[127]
    DIRECTION OUTPUT ;
    USE SIGNAL ;
    SHAPE ABUTMENT ;
    PORT
      LAYER met2 ;
      RECT 353.210 652.380 353.350 652.800 ;
    END
  END r0_rd_out[127]
  PIN r0_rd_out[128]
    DIRECTION OUTPUT ;
    USE SIGNAL ;
    SHAPE ABUTMENT ;
    PORT
      LAYER met2 ;
      RECT 355.970 652.380 356.110 652.800 ;
    END
  END r0_rd_out[128]
  PIN r0_rd_out[129]
    DIRECTION OUTPUT ;
    USE SIGNAL ;
    SHAPE ABUTMENT ;
    PORT
      LAYER met2 ;
      RECT 358.730 652.380 358.870 652.800 ;
    END
  END r0_rd_out[129]
  PIN r0_rd_out[130]
    DIRECTION OUTPUT ;
    USE SIGNAL ;
    SHAPE ABUTMENT ;
    PORT
      LAYER met2 ;
      RECT 361.490 652.380 361.630 652.800 ;
    END
  END r0_rd_out[130]
  PIN r0_rd_out[131]
    DIRECTION OUTPUT ;
    USE SIGNAL ;
    SHAPE ABUTMENT ;
    PORT
      LAYER met2 ;
      RECT 364.250 652.380 364.390 652.800 ;
    END
  END r0_rd_out[131]
  PIN r0_rd_out[132]
    DIRECTION OUTPUT ;
    USE SIGNAL ;
    SHAPE ABUTMENT ;
    PORT
      LAYER met2 ;
      RECT 367.010 652.380 367.150 652.800 ;
    END
  END r0_rd_out[132]
  PIN r0_rd_out[133]
    DIRECTION OUTPUT ;
    USE SIGNAL ;
    SHAPE ABUTMENT ;
    PORT
      LAYER met2 ;
      RECT 369.770 652.380 369.910 652.800 ;
    END
  END r0_rd_out[133]
  PIN r0_rd_out[134]
    DIRECTION OUTPUT ;
    USE SIGNAL ;
    SHAPE ABUTMENT ;
    PORT
      LAYER met2 ;
      RECT 372.530 652.380 372.670 652.800 ;
    END
  END r0_rd_out[134]
  PIN r0_rd_out[135]
    DIRECTION OUTPUT ;
    USE SIGNAL ;
    SHAPE ABUTMENT ;
    PORT
      LAYER met2 ;
      RECT 375.290 652.380 375.430 652.800 ;
    END
  END r0_rd_out[135]
  PIN r0_rd_out[136]
    DIRECTION OUTPUT ;
    USE SIGNAL ;
    SHAPE ABUTMENT ;
    PORT
      LAYER met2 ;
      RECT 378.050 652.380 378.190 652.800 ;
    END
  END r0_rd_out[136]
  PIN r0_rd_out[137]
    DIRECTION OUTPUT ;
    USE SIGNAL ;
    SHAPE ABUTMENT ;
    PORT
      LAYER met2 ;
      RECT 380.810 652.380 380.950 652.800 ;
    END
  END r0_rd_out[137]
  PIN r0_rd_out[138]
    DIRECTION OUTPUT ;
    USE SIGNAL ;
    SHAPE ABUTMENT ;
    PORT
      LAYER met2 ;
      RECT 383.570 652.380 383.710 652.800 ;
    END
  END r0_rd_out[138]
  PIN r0_rd_out[139]
    DIRECTION OUTPUT ;
    USE SIGNAL ;
    SHAPE ABUTMENT ;
    PORT
      LAYER met2 ;
      RECT 386.330 652.380 386.470 652.800 ;
    END
  END r0_rd_out[139]
  PIN r0_rd_out[140]
    DIRECTION OUTPUT ;
    USE SIGNAL ;
    SHAPE ABUTMENT ;
    PORT
      LAYER met2 ;
      RECT 389.090 652.380 389.230 652.800 ;
    END
  END r0_rd_out[140]
  PIN r0_rd_out[141]
    DIRECTION OUTPUT ;
    USE SIGNAL ;
    SHAPE ABUTMENT ;
    PORT
      LAYER met2 ;
      RECT 391.850 652.380 391.990 652.800 ;
    END
  END r0_rd_out[141]
  PIN r0_rd_out[142]
    DIRECTION OUTPUT ;
    USE SIGNAL ;
    SHAPE ABUTMENT ;
    PORT
      LAYER met2 ;
      RECT 394.610 652.380 394.750 652.800 ;
    END
  END r0_rd_out[142]
  PIN r0_rd_out[143]
    DIRECTION OUTPUT ;
    USE SIGNAL ;
    SHAPE ABUTMENT ;
    PORT
      LAYER met2 ;
      RECT 397.370 652.380 397.510 652.800 ;
    END
  END r0_rd_out[143]
  PIN r0_rd_out[144]
    DIRECTION OUTPUT ;
    USE SIGNAL ;
    SHAPE ABUTMENT ;
    PORT
      LAYER met2 ;
      RECT 400.130 652.380 400.270 652.800 ;
    END
  END r0_rd_out[144]
  PIN r0_rd_out[145]
    DIRECTION OUTPUT ;
    USE SIGNAL ;
    SHAPE ABUTMENT ;
    PORT
      LAYER met2 ;
      RECT 402.890 652.380 403.030 652.800 ;
    END
  END r0_rd_out[145]
  PIN r0_rd_out[146]
    DIRECTION OUTPUT ;
    USE SIGNAL ;
    SHAPE ABUTMENT ;
    PORT
      LAYER met2 ;
      RECT 405.650 652.380 405.790 652.800 ;
    END
  END r0_rd_out[146]
  PIN r0_rd_out[147]
    DIRECTION OUTPUT ;
    USE SIGNAL ;
    SHAPE ABUTMENT ;
    PORT
      LAYER met2 ;
      RECT 408.410 652.380 408.550 652.800 ;
    END
  END r0_rd_out[147]
  PIN r0_rd_out[148]
    DIRECTION OUTPUT ;
    USE SIGNAL ;
    SHAPE ABUTMENT ;
    PORT
      LAYER met2 ;
      RECT 411.170 652.380 411.310 652.800 ;
    END
  END r0_rd_out[148]
  PIN r0_rd_out[149]
    DIRECTION OUTPUT ;
    USE SIGNAL ;
    SHAPE ABUTMENT ;
    PORT
      LAYER met2 ;
      RECT 413.930 652.380 414.070 652.800 ;
    END
  END r0_rd_out[149]
  PIN r0_rd_out[150]
    DIRECTION OUTPUT ;
    USE SIGNAL ;
    SHAPE ABUTMENT ;
    PORT
      LAYER met2 ;
      RECT 416.690 652.380 416.830 652.800 ;
    END
  END r0_rd_out[150]
  PIN r0_rd_out[151]
    DIRECTION OUTPUT ;
    USE SIGNAL ;
    SHAPE ABUTMENT ;
    PORT
      LAYER met2 ;
      RECT 419.450 652.380 419.590 652.800 ;
    END
  END r0_rd_out[151]
  PIN r0_rd_out[152]
    DIRECTION OUTPUT ;
    USE SIGNAL ;
    SHAPE ABUTMENT ;
    PORT
      LAYER met2 ;
      RECT 422.210 652.380 422.350 652.800 ;
    END
  END r0_rd_out[152]
  PIN r0_rd_out[153]
    DIRECTION OUTPUT ;
    USE SIGNAL ;
    SHAPE ABUTMENT ;
    PORT
      LAYER met2 ;
      RECT 424.970 652.380 425.110 652.800 ;
    END
  END r0_rd_out[153]
  PIN r0_rd_out[154]
    DIRECTION OUTPUT ;
    USE SIGNAL ;
    SHAPE ABUTMENT ;
    PORT
      LAYER met2 ;
      RECT 427.730 652.380 427.870 652.800 ;
    END
  END r0_rd_out[154]
  PIN r0_rd_out[155]
    DIRECTION OUTPUT ;
    USE SIGNAL ;
    SHAPE ABUTMENT ;
    PORT
      LAYER met2 ;
      RECT 430.490 652.380 430.630 652.800 ;
    END
  END r0_rd_out[155]
  PIN r0_rd_out[156]
    DIRECTION OUTPUT ;
    USE SIGNAL ;
    SHAPE ABUTMENT ;
    PORT
      LAYER met2 ;
      RECT 433.250 652.380 433.390 652.800 ;
    END
  END r0_rd_out[156]
  PIN r0_rd_out[157]
    DIRECTION OUTPUT ;
    USE SIGNAL ;
    SHAPE ABUTMENT ;
    PORT
      LAYER met2 ;
      RECT 436.010 652.380 436.150 652.800 ;
    END
  END r0_rd_out[157]
  PIN r0_rd_out[158]
    DIRECTION OUTPUT ;
    USE SIGNAL ;
    SHAPE ABUTMENT ;
    PORT
      LAYER met2 ;
      RECT 438.770 652.380 438.910 652.800 ;
    END
  END r0_rd_out[158]
  PIN r0_rd_out[159]
    DIRECTION OUTPUT ;
    USE SIGNAL ;
    SHAPE ABUTMENT ;
    PORT
      LAYER met2 ;
      RECT 441.530 652.380 441.670 652.800 ;
    END
  END r0_rd_out[159]
  PIN r0_rd_out[160]
    DIRECTION OUTPUT ;
    USE SIGNAL ;
    SHAPE ABUTMENT ;
    PORT
      LAYER met2 ;
      RECT 444.290 652.380 444.430 652.800 ;
    END
  END r0_rd_out[160]
  PIN r0_rd_out[161]
    DIRECTION OUTPUT ;
    USE SIGNAL ;
    SHAPE ABUTMENT ;
    PORT
      LAYER met2 ;
      RECT 447.050 652.380 447.190 652.800 ;
    END
  END r0_rd_out[161]
  PIN r0_rd_out[162]
    DIRECTION OUTPUT ;
    USE SIGNAL ;
    SHAPE ABUTMENT ;
    PORT
      LAYER met2 ;
      RECT 449.810 652.380 449.950 652.800 ;
    END
  END r0_rd_out[162]
  PIN r0_rd_out[163]
    DIRECTION OUTPUT ;
    USE SIGNAL ;
    SHAPE ABUTMENT ;
    PORT
      LAYER met2 ;
      RECT 452.570 652.380 452.710 652.800 ;
    END
  END r0_rd_out[163]
  PIN r0_rd_out[164]
    DIRECTION OUTPUT ;
    USE SIGNAL ;
    SHAPE ABUTMENT ;
    PORT
      LAYER met2 ;
      RECT 455.330 652.380 455.470 652.800 ;
    END
  END r0_rd_out[164]
  PIN r0_rd_out[165]
    DIRECTION OUTPUT ;
    USE SIGNAL ;
    SHAPE ABUTMENT ;
    PORT
      LAYER met2 ;
      RECT 458.090 652.380 458.230 652.800 ;
    END
  END r0_rd_out[165]
  PIN r0_rd_out[166]
    DIRECTION OUTPUT ;
    USE SIGNAL ;
    SHAPE ABUTMENT ;
    PORT
      LAYER met2 ;
      RECT 460.850 652.380 460.990 652.800 ;
    END
  END r0_rd_out[166]
  PIN r0_rd_out[167]
    DIRECTION OUTPUT ;
    USE SIGNAL ;
    SHAPE ABUTMENT ;
    PORT
      LAYER met2 ;
      RECT 463.610 652.380 463.750 652.800 ;
    END
  END r0_rd_out[167]
  PIN r0_rd_out[168]
    DIRECTION OUTPUT ;
    USE SIGNAL ;
    SHAPE ABUTMENT ;
    PORT
      LAYER met2 ;
      RECT 466.370 652.380 466.510 652.800 ;
    END
  END r0_rd_out[168]
  PIN r0_rd_out[169]
    DIRECTION OUTPUT ;
    USE SIGNAL ;
    SHAPE ABUTMENT ;
    PORT
      LAYER met2 ;
      RECT 469.130 652.380 469.270 652.800 ;
    END
  END r0_rd_out[169]
  PIN r0_rd_out[170]
    DIRECTION OUTPUT ;
    USE SIGNAL ;
    SHAPE ABUTMENT ;
    PORT
      LAYER met2 ;
      RECT 471.890 652.380 472.030 652.800 ;
    END
  END r0_rd_out[170]
  PIN r0_rd_out[171]
    DIRECTION OUTPUT ;
    USE SIGNAL ;
    SHAPE ABUTMENT ;
    PORT
      LAYER met2 ;
      RECT 474.650 652.380 474.790 652.800 ;
    END
  END r0_rd_out[171]
  PIN r0_rd_out[172]
    DIRECTION OUTPUT ;
    USE SIGNAL ;
    SHAPE ABUTMENT ;
    PORT
      LAYER met2 ;
      RECT 477.410 652.380 477.550 652.800 ;
    END
  END r0_rd_out[172]
  PIN r0_rd_out[173]
    DIRECTION OUTPUT ;
    USE SIGNAL ;
    SHAPE ABUTMENT ;
    PORT
      LAYER met2 ;
      RECT 480.170 652.380 480.310 652.800 ;
    END
  END r0_rd_out[173]
  PIN r0_rd_out[174]
    DIRECTION OUTPUT ;
    USE SIGNAL ;
    SHAPE ABUTMENT ;
    PORT
      LAYER met2 ;
      RECT 482.930 652.380 483.070 652.800 ;
    END
  END r0_rd_out[174]
  PIN r0_rd_out[175]
    DIRECTION OUTPUT ;
    USE SIGNAL ;
    SHAPE ABUTMENT ;
    PORT
      LAYER met2 ;
      RECT 485.690 652.380 485.830 652.800 ;
    END
  END r0_rd_out[175]
  PIN r0_rd_out[176]
    DIRECTION OUTPUT ;
    USE SIGNAL ;
    SHAPE ABUTMENT ;
    PORT
      LAYER met2 ;
      RECT 488.450 652.380 488.590 652.800 ;
    END
  END r0_rd_out[176]
  PIN r0_rd_out[177]
    DIRECTION OUTPUT ;
    USE SIGNAL ;
    SHAPE ABUTMENT ;
    PORT
      LAYER met2 ;
      RECT 491.210 652.380 491.350 652.800 ;
    END
  END r0_rd_out[177]
  PIN r0_rd_out[178]
    DIRECTION OUTPUT ;
    USE SIGNAL ;
    SHAPE ABUTMENT ;
    PORT
      LAYER met2 ;
      RECT 493.970 652.380 494.110 652.800 ;
    END
  END r0_rd_out[178]
  PIN r0_rd_out[179]
    DIRECTION OUTPUT ;
    USE SIGNAL ;
    SHAPE ABUTMENT ;
    PORT
      LAYER met2 ;
      RECT 496.730 652.380 496.870 652.800 ;
    END
  END r0_rd_out[179]
  PIN r0_rd_out[180]
    DIRECTION OUTPUT ;
    USE SIGNAL ;
    SHAPE ABUTMENT ;
    PORT
      LAYER met2 ;
      RECT 499.490 652.380 499.630 652.800 ;
    END
  END r0_rd_out[180]
  PIN r0_rd_out[181]
    DIRECTION OUTPUT ;
    USE SIGNAL ;
    SHAPE ABUTMENT ;
    PORT
      LAYER met2 ;
      RECT 502.250 652.380 502.390 652.800 ;
    END
  END r0_rd_out[181]
  PIN r0_rd_out[182]
    DIRECTION OUTPUT ;
    USE SIGNAL ;
    SHAPE ABUTMENT ;
    PORT
      LAYER met2 ;
      RECT 505.010 652.380 505.150 652.800 ;
    END
  END r0_rd_out[182]
  PIN r0_rd_out[183]
    DIRECTION OUTPUT ;
    USE SIGNAL ;
    SHAPE ABUTMENT ;
    PORT
      LAYER met2 ;
      RECT 507.770 652.380 507.910 652.800 ;
    END
  END r0_rd_out[183]
  PIN r0_rd_out[184]
    DIRECTION OUTPUT ;
    USE SIGNAL ;
    SHAPE ABUTMENT ;
    PORT
      LAYER met2 ;
      RECT 510.530 652.380 510.670 652.800 ;
    END
  END r0_rd_out[184]
  PIN r0_rd_out[185]
    DIRECTION OUTPUT ;
    USE SIGNAL ;
    SHAPE ABUTMENT ;
    PORT
      LAYER met2 ;
      RECT 513.290 652.380 513.430 652.800 ;
    END
  END r0_rd_out[185]
  PIN r0_rd_out[186]
    DIRECTION OUTPUT ;
    USE SIGNAL ;
    SHAPE ABUTMENT ;
    PORT
      LAYER met2 ;
      RECT 516.050 652.380 516.190 652.800 ;
    END
  END r0_rd_out[186]
  PIN r0_rd_out[187]
    DIRECTION OUTPUT ;
    USE SIGNAL ;
    SHAPE ABUTMENT ;
    PORT
      LAYER met2 ;
      RECT 518.810 652.380 518.950 652.800 ;
    END
  END r0_rd_out[187]
  PIN r0_rd_out[188]
    DIRECTION OUTPUT ;
    USE SIGNAL ;
    SHAPE ABUTMENT ;
    PORT
      LAYER met2 ;
      RECT 521.570 652.380 521.710 652.800 ;
    END
  END r0_rd_out[188]
  PIN r0_rd_out[189]
    DIRECTION OUTPUT ;
    USE SIGNAL ;
    SHAPE ABUTMENT ;
    PORT
      LAYER met2 ;
      RECT 524.330 652.380 524.470 652.800 ;
    END
  END r0_rd_out[189]
  PIN r0_rd_out[190]
    DIRECTION OUTPUT ;
    USE SIGNAL ;
    SHAPE ABUTMENT ;
    PORT
      LAYER met2 ;
      RECT 527.090 652.380 527.230 652.800 ;
    END
  END r0_rd_out[190]
  PIN r0_rd_out[191]
    DIRECTION OUTPUT ;
    USE SIGNAL ;
    SHAPE ABUTMENT ;
    PORT
      LAYER met2 ;
      RECT 529.850 652.380 529.990 652.800 ;
    END
  END r0_rd_out[191]
  PIN r0_rd_out[192]
    DIRECTION OUTPUT ;
    USE SIGNAL ;
    SHAPE ABUTMENT ;
    PORT
      LAYER met2 ;
      RECT 532.610 652.380 532.750 652.800 ;
    END
  END r0_rd_out[192]
  PIN r0_rd_out[193]
    DIRECTION OUTPUT ;
    USE SIGNAL ;
    SHAPE ABUTMENT ;
    PORT
      LAYER met2 ;
      RECT 535.370 652.380 535.510 652.800 ;
    END
  END r0_rd_out[193]
  PIN r0_rd_out[194]
    DIRECTION OUTPUT ;
    USE SIGNAL ;
    SHAPE ABUTMENT ;
    PORT
      LAYER met2 ;
      RECT 538.130 652.380 538.270 652.800 ;
    END
  END r0_rd_out[194]
  PIN r0_rd_out[195]
    DIRECTION OUTPUT ;
    USE SIGNAL ;
    SHAPE ABUTMENT ;
    PORT
      LAYER met2 ;
      RECT 540.890 652.380 541.030 652.800 ;
    END
  END r0_rd_out[195]
  PIN r0_rd_out[196]
    DIRECTION OUTPUT ;
    USE SIGNAL ;
    SHAPE ABUTMENT ;
    PORT
      LAYER met2 ;
      RECT 543.650 652.380 543.790 652.800 ;
    END
  END r0_rd_out[196]
  PIN r0_rd_out[197]
    DIRECTION OUTPUT ;
    USE SIGNAL ;
    SHAPE ABUTMENT ;
    PORT
      LAYER met2 ;
      RECT 546.410 652.380 546.550 652.800 ;
    END
  END r0_rd_out[197]
  PIN r0_rd_out[198]
    DIRECTION OUTPUT ;
    USE SIGNAL ;
    SHAPE ABUTMENT ;
    PORT
      LAYER met2 ;
      RECT 549.170 652.380 549.310 652.800 ;
    END
  END r0_rd_out[198]
  PIN r0_rd_out[199]
    DIRECTION OUTPUT ;
    USE SIGNAL ;
    SHAPE ABUTMENT ;
    PORT
      LAYER met2 ;
      RECT 551.930 652.380 552.070 652.800 ;
    END
  END r0_rd_out[199]
  PIN r0_rd_out[200]
    DIRECTION OUTPUT ;
    USE SIGNAL ;
    SHAPE ABUTMENT ;
    PORT
      LAYER met2 ;
      RECT 554.690 652.380 554.830 652.800 ;
    END
  END r0_rd_out[200]
  PIN r0_rd_out[201]
    DIRECTION OUTPUT ;
    USE SIGNAL ;
    SHAPE ABUTMENT ;
    PORT
      LAYER met2 ;
      RECT 557.450 652.380 557.590 652.800 ;
    END
  END r0_rd_out[201]
  PIN r0_rd_out[202]
    DIRECTION OUTPUT ;
    USE SIGNAL ;
    SHAPE ABUTMENT ;
    PORT
      LAYER met2 ;
      RECT 560.210 652.380 560.350 652.800 ;
    END
  END r0_rd_out[202]
  PIN r0_rd_out[203]
    DIRECTION OUTPUT ;
    USE SIGNAL ;
    SHAPE ABUTMENT ;
    PORT
      LAYER met2 ;
      RECT 562.970 652.380 563.110 652.800 ;
    END
  END r0_rd_out[203]
  PIN r0_rd_out[204]
    DIRECTION OUTPUT ;
    USE SIGNAL ;
    SHAPE ABUTMENT ;
    PORT
      LAYER met2 ;
      RECT 565.730 652.380 565.870 652.800 ;
    END
  END r0_rd_out[204]
  PIN r0_rd_out[205]
    DIRECTION OUTPUT ;
    USE SIGNAL ;
    SHAPE ABUTMENT ;
    PORT
      LAYER met2 ;
      RECT 568.490 652.380 568.630 652.800 ;
    END
  END r0_rd_out[205]
  PIN r0_rd_out[206]
    DIRECTION OUTPUT ;
    USE SIGNAL ;
    SHAPE ABUTMENT ;
    PORT
      LAYER met2 ;
      RECT 571.250 652.380 571.390 652.800 ;
    END
  END r0_rd_out[206]
  PIN r0_rd_out[207]
    DIRECTION OUTPUT ;
    USE SIGNAL ;
    SHAPE ABUTMENT ;
    PORT
      LAYER met2 ;
      RECT 574.010 652.380 574.150 652.800 ;
    END
  END r0_rd_out[207]
  PIN r0_rd_out[208]
    DIRECTION OUTPUT ;
    USE SIGNAL ;
    SHAPE ABUTMENT ;
    PORT
      LAYER met2 ;
      RECT 576.770 652.380 576.910 652.800 ;
    END
  END r0_rd_out[208]
  PIN r0_rd_out[209]
    DIRECTION OUTPUT ;
    USE SIGNAL ;
    SHAPE ABUTMENT ;
    PORT
      LAYER met2 ;
      RECT 579.530 652.380 579.670 652.800 ;
    END
  END r0_rd_out[209]
  PIN r0_rd_out[210]
    DIRECTION OUTPUT ;
    USE SIGNAL ;
    SHAPE ABUTMENT ;
    PORT
      LAYER met2 ;
      RECT 582.290 652.380 582.430 652.800 ;
    END
  END r0_rd_out[210]
  PIN r0_rd_out[211]
    DIRECTION OUTPUT ;
    USE SIGNAL ;
    SHAPE ABUTMENT ;
    PORT
      LAYER met2 ;
      RECT 585.050 652.380 585.190 652.800 ;
    END
  END r0_rd_out[211]
  PIN r0_rd_out[212]
    DIRECTION OUTPUT ;
    USE SIGNAL ;
    SHAPE ABUTMENT ;
    PORT
      LAYER met2 ;
      RECT 587.810 652.380 587.950 652.800 ;
    END
  END r0_rd_out[212]
  PIN r0_rd_out[213]
    DIRECTION OUTPUT ;
    USE SIGNAL ;
    SHAPE ABUTMENT ;
    PORT
      LAYER met2 ;
      RECT 590.570 652.380 590.710 652.800 ;
    END
  END r0_rd_out[213]
  PIN r0_rd_out[214]
    DIRECTION OUTPUT ;
    USE SIGNAL ;
    SHAPE ABUTMENT ;
    PORT
      LAYER met2 ;
      RECT 593.330 652.380 593.470 652.800 ;
    END
  END r0_rd_out[214]
  PIN r0_rd_out[215]
    DIRECTION OUTPUT ;
    USE SIGNAL ;
    SHAPE ABUTMENT ;
    PORT
      LAYER met2 ;
      RECT 596.090 652.380 596.230 652.800 ;
    END
  END r0_rd_out[215]
  PIN r0_rd_out[216]
    DIRECTION OUTPUT ;
    USE SIGNAL ;
    SHAPE ABUTMENT ;
    PORT
      LAYER met2 ;
      RECT 598.850 652.380 598.990 652.800 ;
    END
  END r0_rd_out[216]
  PIN r0_rd_out[217]
    DIRECTION OUTPUT ;
    USE SIGNAL ;
    SHAPE ABUTMENT ;
    PORT
      LAYER met2 ;
      RECT 601.610 652.380 601.750 652.800 ;
    END
  END r0_rd_out[217]
  PIN r0_rd_out[218]
    DIRECTION OUTPUT ;
    USE SIGNAL ;
    SHAPE ABUTMENT ;
    PORT
      LAYER met2 ;
      RECT 604.370 652.380 604.510 652.800 ;
    END
  END r0_rd_out[218]
  PIN r0_rd_out[219]
    DIRECTION OUTPUT ;
    USE SIGNAL ;
    SHAPE ABUTMENT ;
    PORT
      LAYER met2 ;
      RECT 607.130 652.380 607.270 652.800 ;
    END
  END r0_rd_out[219]
  PIN r0_rd_out[220]
    DIRECTION OUTPUT ;
    USE SIGNAL ;
    SHAPE ABUTMENT ;
    PORT
      LAYER met2 ;
      RECT 609.890 652.380 610.030 652.800 ;
    END
  END r0_rd_out[220]
  PIN r0_rd_out[221]
    DIRECTION OUTPUT ;
    USE SIGNAL ;
    SHAPE ABUTMENT ;
    PORT
      LAYER met2 ;
      RECT 612.650 652.380 612.790 652.800 ;
    END
  END r0_rd_out[221]
  PIN r0_rd_out[222]
    DIRECTION OUTPUT ;
    USE SIGNAL ;
    SHAPE ABUTMENT ;
    PORT
      LAYER met2 ;
      RECT 615.410 652.380 615.550 652.800 ;
    END
  END r0_rd_out[222]
  PIN r0_rd_out[223]
    DIRECTION OUTPUT ;
    USE SIGNAL ;
    SHAPE ABUTMENT ;
    PORT
      LAYER met2 ;
      RECT 618.170 652.380 618.310 652.800 ;
    END
  END r0_rd_out[223]
  PIN r0_rd_out[224]
    DIRECTION OUTPUT ;
    USE SIGNAL ;
    SHAPE ABUTMENT ;
    PORT
      LAYER met2 ;
      RECT 620.930 652.380 621.070 652.800 ;
    END
  END r0_rd_out[224]
  PIN r0_rd_out[225]
    DIRECTION OUTPUT ;
    USE SIGNAL ;
    SHAPE ABUTMENT ;
    PORT
      LAYER met2 ;
      RECT 623.690 652.380 623.830 652.800 ;
    END
  END r0_rd_out[225]
  PIN r0_rd_out[226]
    DIRECTION OUTPUT ;
    USE SIGNAL ;
    SHAPE ABUTMENT ;
    PORT
      LAYER met2 ;
      RECT 626.450 652.380 626.590 652.800 ;
    END
  END r0_rd_out[226]
  PIN r0_rd_out[227]
    DIRECTION OUTPUT ;
    USE SIGNAL ;
    SHAPE ABUTMENT ;
    PORT
      LAYER met2 ;
      RECT 629.210 652.380 629.350 652.800 ;
    END
  END r0_rd_out[227]
  PIN r0_rd_out[228]
    DIRECTION OUTPUT ;
    USE SIGNAL ;
    SHAPE ABUTMENT ;
    PORT
      LAYER met2 ;
      RECT 631.970 652.380 632.110 652.800 ;
    END
  END r0_rd_out[228]
  PIN r0_rd_out[229]
    DIRECTION OUTPUT ;
    USE SIGNAL ;
    SHAPE ABUTMENT ;
    PORT
      LAYER met2 ;
      RECT 634.730 652.380 634.870 652.800 ;
    END
  END r0_rd_out[229]
  PIN rw0_addr_in[0]
    DIRECTION INPUT ;
    USE SIGNAL ;
    SHAPE ABUTMENT ;
    PORT
      LAYER met3 ;
      RECT 0.000 556.090 0.900 556.390 ;
    END
  END rw0_addr_in[0]
  PIN rw0_addr_in[1]
    DIRECTION INPUT ;
    USE SIGNAL ;
    SHAPE ABUTMENT ;
    PORT
      LAYER met3 ;
      RECT 0.000 565.610 0.900 565.910 ;
    END
  END rw0_addr_in[1]
  PIN rw0_addr_in[2]
    DIRECTION INPUT ;
    USE SIGNAL ;
    SHAPE ABUTMENT ;
    PORT
      LAYER met3 ;
      RECT 0.000 575.130 0.900 575.430 ;
    END
  END rw0_addr_in[2]
  PIN rw0_addr_in[3]
    DIRECTION INPUT ;
    USE SIGNAL ;
    SHAPE ABUTMENT ;
    PORT
      LAYER met3 ;
      RECT 0.000 584.650 0.900 584.950 ;
    END
  END rw0_addr_in[3]
  PIN rw0_addr_in[4]
    DIRECTION INPUT ;
    USE SIGNAL ;
    SHAPE ABUTMENT ;
    PORT
      LAYER met3 ;
      RECT 705.200 546.570 706.100 546.870 ;
    END
  END rw0_addr_in[4]
  PIN rw0_addr_in[5]
    DIRECTION INPUT ;
    USE SIGNAL ;
    SHAPE ABUTMENT ;
    PORT
      LAYER met3 ;
      RECT 705.200 556.090 706.100 556.390 ;
    END
  END rw0_addr_in[5]
  PIN rw0_addr_in[6]
    DIRECTION INPUT ;
    USE SIGNAL ;
    SHAPE ABUTMENT ;
    PORT
      LAYER met3 ;
      RECT 705.200 565.610 706.100 565.910 ;
    END
  END rw0_addr_in[6]
  PIN r0_addr_in[0]
    DIRECTION INPUT ;
    USE SIGNAL ;
    SHAPE ABUTMENT ;
    PORT
      LAYER met3 ;
      RECT 0.000 594.170 0.900 594.470 ;
    END
  END r0_addr_in[0]
  PIN r0_addr_in[1]
    DIRECTION INPUT ;
    USE SIGNAL ;
    SHAPE ABUTMENT ;
    PORT
      LAYER met3 ;
      RECT 0.000 603.690 0.900 603.990 ;
    END
  END r0_addr_in[1]
  PIN r0_addr_in[2]
    DIRECTION INPUT ;
    USE SIGNAL ;
    SHAPE ABUTMENT ;
    PORT
      LAYER met3 ;
      RECT 0.000 613.210 0.900 613.510 ;
    END
  END r0_addr_in[2]
  PIN r0_addr_in[3]
    DIRECTION INPUT ;
    USE SIGNAL ;
    SHAPE ABUTMENT ;
    PORT
      LAYER met3 ;
      RECT 0.000 622.730 0.900 623.030 ;
    END
  END r0_addr_in[3]
  PIN r0_addr_in[4]
    DIRECTION INPUT ;
    USE SIGNAL ;
    SHAPE ABUTMENT ;
    PORT
      LAYER met3 ;
      RECT 705.200 575.130 706.100 575.430 ;
    END
  END r0_addr_in[4]
  PIN r0_addr_in[5]
    DIRECTION INPUT ;
    USE SIGNAL ;
    SHAPE ABUTMENT ;
    PORT
      LAYER met3 ;
      RECT 705.200 584.650 706.100 584.950 ;
    END
  END r0_addr_in[5]
  PIN r0_addr_in[6]
    DIRECTION INPUT ;
    USE SIGNAL ;
    SHAPE ABUTMENT ;
    PORT
      LAYER met3 ;
      RECT 705.200 594.170 706.100 594.470 ;
    END
  END r0_addr_in[6]
  PIN rw0_we_in
    DIRECTION INPUT ;
    USE SIGNAL ;
    SHAPE ABUTMENT ;
    PORT
      LAYER met2 ;
      RECT 637.490 652.380 637.630 652.800 ;
    END
  END rw0_we_in
  PIN rw0_ce_in
    DIRECTION INPUT ;
    USE SIGNAL ;
    SHAPE ABUTMENT ;
    PORT
      LAYER met2 ;
      RECT 640.250 652.380 640.390 652.800 ;
    END
  END rw0_ce_in
  PIN rw0_clk
    DIRECTION INPUT ;
    USE SIGNAL ;
    SHAPE ABUTMENT ;
    PORT
      LAYER met2 ;
      RECT 643.010 652.380 643.150 652.800 ;
    END
  END rw0_clk
  PIN r0_ce_in
    DIRECTION INPUT ;
    USE SIGNAL ;
    SHAPE ABUTMENT ;
    PORT
      LAYER met2 ;
      RECT 645.770 652.380 645.910 652.800 ;
    END
  END r0_ce_in
  PIN r0_clk
    DIRECTION INPUT ;
    USE SIGNAL ;
    SHAPE ABUTMENT ;
    PORT
      LAYER met2 ;
      RECT 648.530 652.380 648.670 652.800 ;
    END
  END r0_clk
  PIN VSS
    DIRECTION INOUT ;
    USE GROUND ;
    PORT
      LAYER met4 ;
      RECT 2.160 4.080 3.360 648.720 ;
      RECT 13.040 4.080 14.240 648.720 ;
      RECT 23.920 4.080 25.120 648.720 ;
      RECT 34.800 4.080 36.000 648.720 ;
      RECT 45.680 4.080 46.880 648.720 ;
      RECT 56.560 4.080 57.760 648.720 ;
      RECT 67.440 4.080 68.640 648.720 ;
      RECT 78.320 4.080 79.520 648.720 ;
      RECT 89.200 4.080 90.400 648.720 ;
      RECT 100.080 4.080 101.280 648.720 ;
      RECT 110.960 4.080 112.160 648.720 ;
      RECT 121.840 4.080 123.040 648.720 ;
      RECT 132.720 4.080 133.920 648.720 ;
      RECT 143.600 4.080 144.800 648.720 ;
      RECT 154.480 4.080 155.680 648.720 ;
      RECT 165.360 4.080 166.560 648.720 ;
      RECT 176.240 4.080 177.440 648.720 ;
      RECT 187.120 4.080 188.320 648.720 ;
      RECT 198.000 4.080 199.200 648.720 ;
      RECT 208.880 4.080 210.080 648.720 ;
      RECT 219.760 4.080 220.960 648.720 ;
      RECT 230.640 4.080 231.840 648.720 ;
      RECT 241.520 4.080 242.720 648.720 ;
      RECT 252.400 4.080 253.600 648.720 ;
      RECT 263.280 4.080 264.480 648.720 ;
      RECT 274.160 4.080 275.360 648.720 ;
      RECT 285.040 4.080 286.240 648.720 ;
      RECT 295.920 4.080 297.120 648.720 ;
      RECT 306.800 4.080 308.000 648.720 ;
      RECT 317.680 4.080 318.880 648.720 ;
      RECT 328.560 4.080 329.760 648.720 ;
      RECT 339.440 4.080 340.640 648.720 ;
      RECT 350.320 4.080 351.520 648.720 ;
      RECT 361.200 4.080 362.400 648.720 ;
      RECT 372.080 4.080 373.280 648.720 ;
      RECT 382.960 4.080 384.160 648.720 ;
      RECT 393.840 4.080 395.040 648.720 ;
      RECT 404.720 4.080 405.920 648.720 ;
      RECT 415.600 4.080 416.800 648.720 ;
      RECT 426.480 4.080 427.680 648.720 ;
      RECT 437.360 4.080 438.560 648.720 ;
      RECT 448.240 4.080 449.440 648.720 ;
      RECT 459.120 4.080 460.320 648.720 ;
      RECT 470.000 4.080 471.200 648.720 ;
      RECT 480.880 4.080 482.080 648.720 ;
      RECT 491.760 4.080 492.960 648.720 ;
      RECT 502.640 4.080 503.840 648.720 ;
      RECT 513.520 4.080 514.720 648.720 ;
      RECT 524.400 4.080 525.600 648.720 ;
      RECT 535.280 4.080 536.480 648.720 ;
      RECT 546.160 4.080 547.360 648.720 ;
      RECT 557.040 4.080 558.240 648.720 ;
      RECT 567.920 4.080 569.120 648.720 ;
      RECT 578.800 4.080 580.000 648.720 ;
      RECT 589.680 4.080 590.880 648.720 ;
      RECT 600.560 4.080 601.760 648.720 ;
      RECT 611.440 4.080 612.640 648.720 ;
      RECT 622.320 4.080 623.520 648.720 ;
      RECT 633.200 4.080 634.400 648.720 ;
      RECT 644.080 4.080 645.280 648.720 ;
      RECT 654.960 4.080 656.160 648.720 ;
      RECT 665.840 4.080 667.040 648.720 ;
      RECT 676.720 4.080 677.920 648.720 ;
      RECT 687.600 4.080 688.800 648.720 ;
      RECT 698.480 4.080 699.680 648.720 ;
    END
  END VSS
  PIN VDD
    DIRECTION INOUT ;
    USE POWER ;
    PORT
      LAYER met4 ;
      RECT 2.160 4.080 3.360 648.720 ;
      RECT 13.040 4.080 14.240 648.720 ;
      RECT 23.920 4.080 25.120 648.720 ;
      RECT 34.800 4.080 36.000 648.720 ;
      RECT 45.680 4.080 46.880 648.720 ;
      RECT 56.560 4.080 57.760 648.720 ;
      RECT 67.440 4.080 68.640 648.720 ;
      RECT 78.320 4.080 79.520 648.720 ;
      RECT 89.200 4.080 90.400 648.720 ;
      RECT 100.080 4.080 101.280 648.720 ;
      RECT 110.960 4.080 112.160 648.720 ;
      RECT 121.840 4.080 123.040 648.720 ;
      RECT 132.720 4.080 133.920 648.720 ;
      RECT 143.600 4.080 144.800 648.720 ;
      RECT 154.480 4.080 155.680 648.720 ;
      RECT 165.360 4.080 166.560 648.720 ;
      RECT 176.240 4.080 177.440 648.720 ;
      RECT 187.120 4.080 188.320 648.720 ;
      RECT 198.000 4.080 199.200 648.720 ;
      RECT 208.880 4.080 210.080 648.720 ;
      RECT 219.760 4.080 220.960 648.720 ;
      RECT 230.640 4.080 231.840 648.720 ;
      RECT 241.520 4.080 242.720 648.720 ;
      RECT 252.400 4.080 253.600 648.720 ;
      RECT 263.280 4.080 264.480 648.720 ;
      RECT 274.160 4.080 275.360 648.720 ;
      RECT 285.040 4.080 286.240 648.720 ;
      RECT 295.920 4.080 297.120 648.720 ;
      RECT 306.800 4.080 308.000 648.720 ;
      RECT 317.680 4.080 318.880 648.720 ;
      RECT 328.560 4.080 329.760 648.720 ;
      RECT 339.440 4.080 340.640 648.720 ;
      RECT 350.320 4.080 351.520 648.720 ;
      RECT 361.200 4.080 362.400 648.720 ;
      RECT 372.080 4.080 373.280 648.720 ;
      RECT 382.960 4.080 384.160 648.720 ;
      RECT 393.840 4.080 395.040 648.720 ;
      RECT 404.720 4.080 405.920 648.720 ;
      RECT 415.600 4.080 416.800 648.720 ;
      RECT 426.480 4.080 427.680 648.720 ;
      RECT 437.360 4.080 438.560 648.720 ;
      RECT 448.240 4.080 449.440 648.720 ;
      RECT 459.120 4.080 460.320 648.720 ;
      RECT 470.000 4.080 471.200 648.720 ;
      RECT 480.880 4.080 482.080 648.720 ;
      RECT 491.760 4.080 492.960 648.720 ;
      RECT 502.640 4.080 503.840 648.720 ;
      RECT 513.520 4.080 514.720 648.720 ;
      RECT 524.400 4.080 525.600 648.720 ;
      RECT 535.280 4.080 536.480 648.720 ;
      RECT 546.160 4.080 547.360 648.720 ;
      RECT 557.040 4.080 558.240 648.720 ;
      RECT 567.920 4.080 569.120 648.720 ;
      RECT 578.800 4.080 580.000 648.720 ;
      RECT 589.680 4.080 590.880 648.720 ;
      RECT 600.560 4.080 601.760 648.720 ;
      RECT 611.440 4.080 612.640 648.720 ;
      RECT 622.320 4.080 623.520 648.720 ;
      RECT 633.200 4.080 634.400 648.720 ;
      RECT 644.080 4.080 645.280 648.720 ;
      RECT 654.960 4.080 656.160 648.720 ;
      RECT 665.840 4.080 667.040 648.720 ;
      RECT 676.720 4.080 677.920 648.720 ;
      RECT 687.600 4.080 688.800 648.720 ;
      RECT 698.480 4.080 699.680 648.720 ;
    END
  END VDD
  OBS
    LAYER met1 ;
    RECT 0 0 706.100 652.800 ;
    LAYER met2 ;
    RECT 0 0 706.100 652.800 ;
    LAYER met3 ;
    RECT 0 0 706.100 652.800 ;
    LAYER met4 ;
    RECT 0 0 706.100 652.800 ;
  END
END fakeram130_1rw1r_230w128d

END LIBRARY
